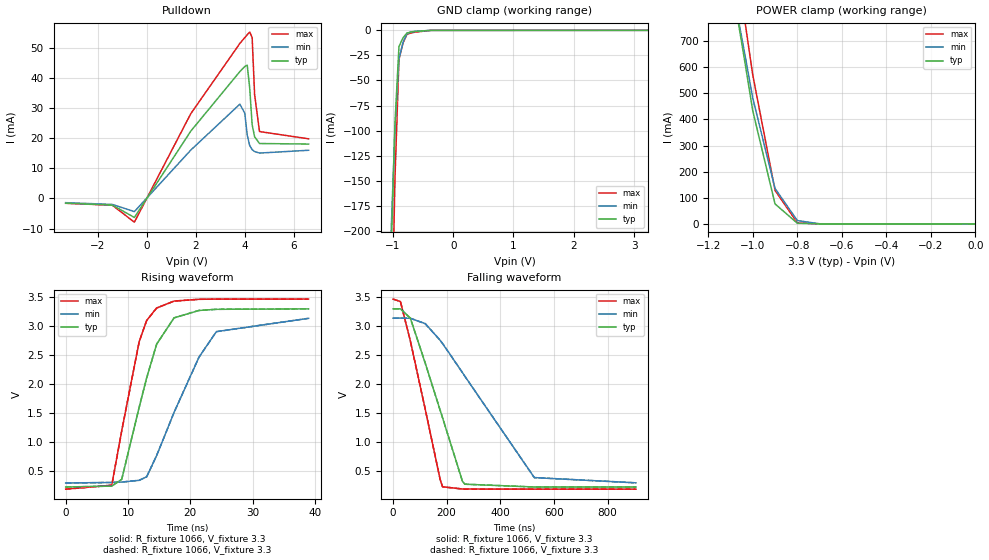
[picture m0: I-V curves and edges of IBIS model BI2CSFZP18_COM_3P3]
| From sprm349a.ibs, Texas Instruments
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|   Model Cell BI2CSFZP18_COM_3P3
[Model]   BI2CSFZP18_COM_3P3
Model_type   I/O_open_drain
Polarity   Non-Inverting
Enable   Active-Low
Vinl =  0.99
Vinh =  2.31
Cref =  400pF
Rref =  1.066k
Vref =  1.8V
Vmeas =  1.65
C_comp   1.488594p   1.343646p   1.625598p
[Model Spec]
Vinl   0.99   0.942   1.041
Vinh   2.31   2.198   2.429
[Temperature Range]   25   105   0
[Voltage Range]   3.3   3.14   3.47
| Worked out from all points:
|   slope of the pulldown table from 0 to 0.495 V, typ, clamps not added: 76.9 ohm
|   GND clamp passes 1 mA (typ) near -0.62 V on its own axis
|   POWER clamp passes 1 mA (typ) near -0.73 V on its own axis
|   rising waveform, R_fixture 1066, V_fixture 3.3: 20-80 % time 4.47ns typ, 6.96ns min, 3.58ns max; typ from 0.221 V to 3.3 V
|   rising waveform, R_fixture 1066, V_fixture 3.3: 20-80 % time 4.47ns typ, 6.96ns min, 3.58ns max; typ from 0.221 V to 3.3 V
|   falling waveform, R_fixture 1066, V_fixture 3.3: 20-80 % time 126ns typ, 248ns min, 92.5ns max; typ from 3.3 V to 0.221 V
|   falling waveform, R_fixture 1066, V_fixture 3.3: 20-80 % time 126ns typ, 248ns min, 92.5ns max; typ from 3.3 V to 0.221 V
[POWER_clamp]
|   voltage   I(typ)   I(min)   I(max)
-3.3V     15.05A     13.75A     15.99A
-1.067V   781.2mA    793mA      954.4mA
-1.033V   606.9mA    637.3mA    762.2mA
-1V       432.7mA    481.5mA    570mA
-900mV    76.75mA    135.8mA    128.5mA
-800mV    2.774mA    12.97mA    4.49mA
-700mV    66.53uA    739.3uA    77.17uA
-11.55fV  40.21nA    28.69nA    188.6nA
[Pulldown]
|   voltage   I(typ)   I(min)   I(max)
-3.3V     -1.585mA   -1.413mA   -1.619mA
-1.4V     -2.214mA   -1.997mA   -2.244mA
-500mV    -6.316mA   -4.377mA   -7.884mA
1.8V      22.32mA    16.03mA    28.1mA
3.8V      42.06mA    31.25mA    51.39mA
4V        43.73mA    28.23mA    53.32mA
4.1V      44.15mA    20.94mA    54.26mA
4.2V      36.62mA    17.54mA    55.14mA
4.3V      24.45mA    16.18mA    53.34mA
4.4V      20.43mA    15.54mA    34.42mA
4.6V      18.2mA     15.03mA    22.16mA
6.6V      18.02mA    15.96mA    19.76mA
[GND_clamp]
|   voltage   I(typ)   I(min)   I(max)
-3.3V     -17.3A     -15.81A    -18.24A
-1.033V   -228.3mA   -206mA     -345.7mA
-966.7mV  -93.1mA    -99.19mA   -148.6mA
-900mV    -16.17mA   -28.6mA    -29.03mA
-833.3mV  -7.484mA   -12.28mA   -12.72mA
-766.7mV  -2.666mA   -3.264mA   -3.923mA
-700mV    -1.72mA    -1.56mA    -2.645mA
-633.3mV  -1.119mA   -1.016mA   -1.818mA
-366.7mV  -16.93uA   -31.45uA   -52.75uA
3.233V    39.65nA    29.26nA    179.4nA
[Ramp]
| variable   typ   min   max
dV/dt_f   1.855402/0.1268571u   1.714812/0.249363u   1.982765/92.97102n
dV/dt_r  21.68196m/1.223917n   14.55153m/2.251652n   24.65348m/0.9062145n
R_load = 1.066k
[Rising Waveform]
R_fixture = 1066
V_fixture = 3.3
V_fixture_min = 3.14
V_fixture_max = 3.47
|   time   V(typ)   V(min)   V(max)
0s        220.8mV    289.7mV    183.5mV
7.4ns     236.5mV    299.5mV    251.6mV
9ns       354.2mV    306mV      1.193V
11.8ns    1.598V     336.9mV    2.733V
13ns      2.105V     396.7mV    3.099V
14.6ns    2.689V     763.2mV    3.315V
17.4ns    3.145V     1.51V      3.435V
21.4ns    3.273V     2.465V     3.466V
24.2ns    3.293V     2.907V     3.469V
39ns      3.3V       3.137V     3.47V
[Rising Waveform]
R_fixture = 1066
V_fixture = 3.3
V_fixture_min = 3.14
V_fixture_max = 3.47
|   time   V(typ)   V(min)   V(max)
0s        220.8mV    289.7mV    183.5mV
7.4ns     236.5mV    299.5mV    251.6mV
9ns       354.2mV    306mV      1.193V
11.8ns    1.598V     336.9mV    2.733V
13ns      2.105V     396.7mV    3.099V
14.6ns    2.689V     763.2mV    3.315V
17.4ns    3.145V     1.51V      3.435V
21.4ns    3.273V     2.465V     3.466V
24.2ns    3.293V     2.907V     3.469V
39ns      3.3V       3.137V     3.47V
[Falling Waveform]
R_fixture = 1066
V_fixture = 3.3
V_fixture_min = 3.14
V_fixture_max = 3.47
|   time   V(typ)   V(min)   V(max)
0s        3.3V       3.14V      3.47V
27.6ns    3.302V     3.141V     3.427V
64.4ns    3.141V     3.138V     2.75V
120ns     2.363V     3.045V     1.566V
175.4ns   1.551V     2.759V     356mV
184.6ns   1.419V     2.702V     224.4mV
258.6ns   321.1mV    2.2V       186.3mV
267.8ns   269.4mV    2.135V     185.8mV
526.6ns   221mV      383.5mV    183.5mV
905.4ns   220.8mV    292.9mV    183.5mV
[Falling Waveform]
R_fixture = 1066
V_fixture = 3.3
V_fixture_min = 3.14
V_fixture_max = 3.47
|   time   V(typ)   V(min)   V(max)
0s        3.3V       3.14V      3.47V
27.6ns    3.302V     3.141V     3.427V
64.4ns    3.141V     3.138V     2.75V
120ns     2.363V     3.045V     1.566V
175.4ns   1.551V     2.759V     356mV
184.6ns   1.419V     2.702V     224.4mV
258.6ns   321.1mV    2.2V       186.3mV
267.8ns   269.4mV    2.135V     185.8mV
526.6ns   221mV      383.5mV    183.5mV
905.4ns   220.8mV    292.9mV    183.5mV
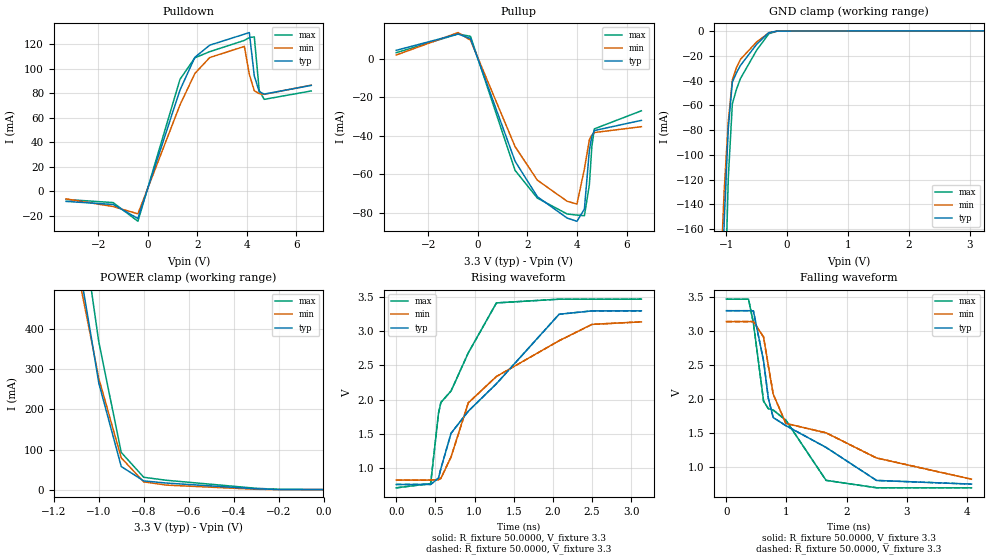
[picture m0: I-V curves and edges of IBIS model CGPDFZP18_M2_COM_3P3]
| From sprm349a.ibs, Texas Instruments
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|BUFFER OPERATING IN NORMAL MODE AT IND TEMP
|IND AND COM ARE TWO TEMP MODES WITH DIFF TEMP RANGE
|PI IS PULLDOWN PIN.
|   Model Cell CGPDFZP18_M2_COM_3P3
[Model]   CGPDFZP18_M2_COM_3P3
Model_type   I/O
Polarity   Non-Inverting
Enable   Active-Low
Vinl =  0.8
Vinh =  2.0
Cref =  10.0000pF
Rref =  50.0000
Vref =  1.5V
Vmeas =  1.5
C_comp   2.231182p   2.070767p   2.288404p
[Temperature Range]   25   105   0
[Voltage Range]   3.3   3.14   3.47
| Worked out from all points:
|   slope of the pulldown table from 0 to 0.495 V, typ, clamps not added: 14.8 ohm
|   slope of the pullup table from 0 to 0.495 V, typ, clamps not added: 25.3 ohm
|   GND clamp passes 1 mA (typ) near -0.27 V on its own axis
|   POWER clamp passes 1 mA (typ) near -0.24 V on its own axis
|   rising waveform, R_fixture 50.0000, V_fixture 3.3: 20-80 % time 1.07ns typ, 1.09ns min, 526ps max; typ from 0.758 V to 3.3 V
|   rising waveform, R_fixture 50.0000, V_fixture 3.3: 20-80 % time 1.07ns typ, 1.09ns min, 526ps max; typ from 0.758 V to 3.3 V
|   falling waveform, R_fixture 50.0000, V_fixture 3.3: 20-80 % time 1.11ns typ, 1.51ns min, 844ps max; typ from 3.3 V to 0.755 V
|   falling waveform, R_fixture 50.0000, V_fixture 3.3: 20-80 % time 1.11ns typ, 1.51ns min, 844ps max; typ from 3.3 V to 0.755 V
[POWER_clamp]
|   voltage   I(typ)   I(min)   I(max)
-3.3V     9.989A     8.641A     10.98A
-1.1V     604.8mA    564.8mA    758mA
-1.067V   491.9mA    469.1mA    628.3mA
-1.033V   379.1mA    373.5mA    498.7mA
-1V       266.2mA    277.8mA    369mA
-900mV    57.71mA    79.31mA    92.84mA
-800mV    21.76mA    19.36mA    30.85mA
-700mV    16.48mA    11.32mA    23.4mA
-300mV    2.029mA    849.9uA    3.357mA
-200mV    392.4uA    158.3uA    756.2uA
-11.55fV  102.4uA    62.72uA    147.1uA
[Pulldown]
|   voltage   I(typ)   I(min)   I(max)
-3.3V     -8.456mA   -6.412mA   -6.88mA
-1.4V     -10.96mA   -12.65mA   -9.431mA
-400mV    -22.4mA    -18.63mA   -24.71mA
1.3V      82.47mA    70.34mA    91.2mA
1.9V      109.2mA    95.96mA    108.8mA
2.5V      119.1mA    109mA      113.8mA
3.9V      128.1mA    118.1mA    123mA
4.1V      129.4mA    95.25mA    125.3mA
4.3V      94.04mA    81.92mA    125.9mA
4.5V      81.16mA    79.48mA    82.05mA
4.7V      79.16mA    78.96mA    74.86mA
6.6V      86.26mA    86.47mA    81.73mA
[Pullup]
|   voltage   I(typ)   I(min)   I(max)
-3.3V     4.286mA    1.847mA    3.065mA
-800mV    12.73mA    13.5mA     12.77mA
-300mV    10.41mA    9.538mA    11.56mA
1.5V      -53.19mA   -45.63mA   -57.95mA
2.4V      -71.6mA    -63.02mA   -72.32mA
3.6V      -82.66mA   -73.94mA   -80.54mA
4V        -84.35mA   -75.4mA    -81.13mA
4.3V      -77.99mA   -57.15mA   -81.46mA
4.5V      -47.49mA   -42.07mA   -65.43mA
4.6V      -40.38mA   -39.67mA   -45.58mA
4.7V      -37.3mA    -38.33mA   -36.43mA
6.6V      -32.02mA   -35.3mA    -27.05mA
[GND_clamp]
|   voltage   I(typ)   I(min)   I(max)
-3.3V     -13.5A     -11.63A    -14.67A
-1.1V     -264.6mA   -203.9mA   -421mA
-1.033V   -153.2mA   -128.3mA   -240mA
-966.7mV  -78.84mA   -73.47mA   -119.3mA
-900mV    -41.39mA   -39.57mA   -58.92mA
-833.3mV  -33.86mA   -29.78mA   -47.28mA
-766.7mV  -27.82mA   -22.88mA   -38.44mA
-500mV    -10.72mA   -8.846mA   -15.5mA
-300mV    -1.324mA   -1.478mA   -2.222mA
-166.7mV  -97.17uA   -154.9uA   -180.7uA
-100mV    -31.73uA   -28.57uA   -80.76uA
3.233V    102.2uA    74.43uA    145.9uA
[Ramp]
| variable   typ   min   max
dV/dt_f   1.526672/1.114159n   1.396267/1.538971n   1.660851/0.8434568n
dV/dt_r   1.293742/1.220363n   1.17001/1.321445n   1.422753/0.6798938n
R_load = 50
[Rising Waveform]
R_fixture = 50.0000
V_fixture = 3.3
V_fixture_min = 3.14
V_fixture_max = 3.47
|   time   V(typ)   V(min)   V(max)
0s        758.4mV    823.3mV    709.3mV
440ps     759.6mV    823.7mV    772.1mV
540ps     852.1mV    829.5mV    1.799V
570ps     988.9mV    846.9mV    1.957V
700ps     1.507V     1.161V     2.125V
920ps     1.829V     1.951V     2.682V
1.28ns    2.232V     2.338V     3.413V
2.08ns    3.247V     2.86V      3.467V
2.5ns     3.296V     3.099V     3.467V
3.13ns    3.297V     3.136V     3.468V
[Rising Waveform]
R_fixture = 50.0000
V_fixture = 3.3
V_fixture_min = 3.14
V_fixture_max = 3.47
|   time   V(typ)   V(min)   V(max)
0s        758.4mV    823.3mV    709.3mV
440ps     759.6mV    823.7mV    772.1mV
540ps     852.1mV    829.5mV    1.799V
570ps     988.9mV    846.9mV    1.957V
700ps     1.507V     1.161V     2.125V
920ps     1.829V     1.951V     2.682V
1.28ns    2.232V     2.338V     3.413V
2.08ns    3.247V     2.86V      3.467V
2.5ns     3.296V     3.099V     3.467V
3.13ns    3.297V     3.136V     3.468V
[Falling Waveform]
R_fixture = 50.0000
V_fixture = 3.3
V_fixture_min = 3.14
V_fixture_max = 3.47
|   time   V(typ)   V(min)   V(max)
0s        3.298V     3.139V     3.468V
370ps     3.298V     3.139V     3.467V
450ps     3.296V     3.139V     3.121V
620ps     2.559V     2.911V     1.971V
700ps     2.009V     2.486V     1.861V
780ps     1.731V     2.076V     1.841V
990ps     1.613V     1.645V     1.693V
1.66ns    1.293V     1.507V     809.9mV
2.5ns     808.7mV    1.138V     701.2mV
4.08ns    754.7mV    827.1mV    699.9mV
[Falling Waveform]
R_fixture = 50.0000
V_fixture = 3.3
V_fixture_min = 3.14
V_fixture_max = 3.47
|   time   V(typ)   V(min)   V(max)
0s        3.298V     3.139V     3.468V
370ps     3.298V     3.139V     3.467V
450ps     3.296V     3.139V     3.121V
620ps     2.559V     2.911V     1.971V
700ps     2.009V     2.486V     1.861V
780ps     1.731V     2.076V     1.841V
990ps     1.613V     1.645V     1.693V
1.66ns    1.293V     1.507V     809.9mV
2.5ns     808.7mV    1.138V     701.2mV
4.08ns    754.7mV    827.1mV    699.9mV
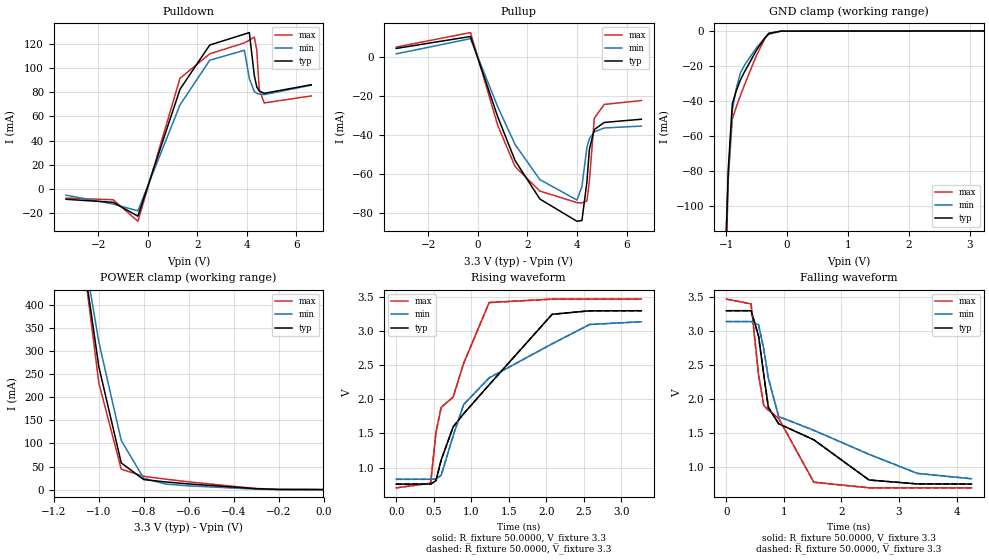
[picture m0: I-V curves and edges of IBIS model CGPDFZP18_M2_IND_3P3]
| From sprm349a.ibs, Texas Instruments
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|   Model Cell CGPDFZP18_M2_IND_3P3
[Model]   CGPDFZP18_M2_IND_3P3
Model_type   I/O
Polarity   Non-Inverting
Enable   Active-Low
Vinl =  0.8
Vinh =  2.0
Cref =  10.0000pF
Rref =  50.0000
Vref =  1.5V
Vmeas =  1.5
C_comp   2.231182p   2.070688p   2.311083p
[Temperature Range]   25   125   -40
[Voltage Range]   3.3   3.14   3.47
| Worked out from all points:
|   slope of the pulldown table from 0 to 0.495 V, typ, clamps not added: 14.8 ohm
|   slope of the pullup table from 0 to 0.495 V, typ, clamps not added: 25.3 ohm
|   GND clamp passes 1 mA (typ) near -0.27 V on its own axis
|   POWER clamp passes 1 mA (typ) near -0.24 V on its own axis
|   rising waveform, R_fixture 50.0000, V_fixture 3.3: 20-80 % time 1.06ns typ, 1.14ns min, 507ps max; typ from 0.759 V to 3.3 V
|   rising waveform, R_fixture 50.0000, V_fixture 3.3: 20-80 % time 1.06ns typ, 1.14ns min, 507ps max; typ from 0.759 V to 3.3 V
|   falling waveform, R_fixture 50.0000, V_fixture 3.3: 20-80 % time 1.11ns typ, 1.59ns min, 719ps max; typ from 3.3 V to 0.755 V
|   falling waveform, R_fixture 50.0000, V_fixture 3.3: 20-80 % time 1.11ns typ, 1.59ns min, 719ps max; typ from 3.3 V to 0.755 V
[POWER_clamp]
|   voltage   I(typ)   I(min)   I(max)
-3.3V     9.989A     8.515A     11.3A
-1.067V   491.9mA    510.8mA    488.4mA
-1.033V   379.1mA    415.3mA    359.7mA
-1V       266.2mA    319.7mA    231mA
-900mV    57.71mA    106.4mA    44.24mA
-800mV    21.75mA    24.35mA    28.73mA
-700mV    16.48mA    11.91mA    22.61mA
-600mV    12.37mA    8.231mA    16.78mA
-300mV    2.026mA    990.7uA    2.509mA
-200mV    389.8uA    196.9uA    460.9uA
-11.55fV  99.83uA    62.74uA    165uA
[Pulldown]
|   voltage   I(typ)   I(min)   I(max)
-3.3V     -8.447mA   -5.044mA   -7.456mA
-1.4V     -10.95mA   -12.3mA    -8.83mA
-400mV    -22.39mA   -18.01mA   -26.63mA
1.3V      82.43mA    69.53mA    91.5mA
2.5V      119mA      106.4mA    111.7mA
3.9V      128mA      114.7mA    120.8mA
4.1V      129.3mA    91.31mA    123mA
4.3V      93.96mA    80.57mA    125.6mA
4.4V      84.37mA    79.15mA    115mA
4.5V      81.1mA     78.45mA    82.37mA
4.7V      79.1mA     78.02mA    71.14mA
6.6V      86.2mA     85.83mA    76.96mA
[Pullup]
|   voltage   I(typ)   I(min)   I(max)
-3.3V     4.286mA    1.496mA    4.988mA
-300mV    10.41mA    9.296mA    12.42mA
800mV     -30.78mA   -25.65mA   -35.19mA
1.5V      -53.19mA   -44.94mA   -56.28mA
2.5V      -72.91mA   -62.97mA   -68.85mA
4V        -84.34mA   -73.44mA   -74.76mA
4.2V      -83.95mA   -66.45mA   -74.95mA
4.4V      -64.26mA   -46.53mA   -73.94mA
4.5V      -47.49mA   -42.04mA   -63.86mA
4.7V      -37.3mA    -38.48mA   -31.51mA
5.1V      -33.66mA   -36.49mA   -24.42mA
6.6V      -32.01mA   -35.52mA   -22.44mA
[GND_clamp]
|   voltage   I(typ)   I(min)   I(max)
-3.3V     -13.5A     -11.41A    -15.22A
-1.033V   -153.2mA   -142mA     -175.6mA
-966.7mV  -78.84mA   -82.94mA   -84.21mA
-900mV    -41.39mA   -45.29mA   -49.98mA
-833.3mV  -33.86mA   -32.48mA   -43.1mA
-766.7mV  -27.82mA   -23.87mA   -36.67mA
-700mV    -23.25mA   -19.45mA   -30.66mA
-500mV    -10.72mA   -9.351mA   -13.63mA
-366.7mV  -3.934mA   -3.986mA   -4.53mA
-300mV    -1.324mA   -1.811mA   -1.163mA
-100mV    -31.61uA   -39.44uA   -46.87uA
3.233V    99.59uA    80.68uA    164.5uA
[Ramp]
| variable   typ   min   max
dV/dt_f   1.526544/1.113073n   1.393242/1.618247n   1.66137/0.7197431n
dV/dt_r   1.293759/1.219096n   1.164049/1.393901n   1.410053/0.6646706n
R_load = 50
[Rising Waveform]
R_fixture = 50.0000
V_fixture = 3.3
V_fixture_min = 3.14
V_fixture_max = 3.47
|   time   V(typ)   V(min)   V(max)
0s        758.6mV    829.2mV    704.1mV
460ps     760.2mV    830mV      772.5mV
530ps     808.8mV    834mV      1.519V
600ps     1.112V     888.9mV    1.883V
760ps     1.597V     1.468V     2.034V
900ps     1.79V      1.925V     2.528V
1.24ns    2.213V     2.314V     3.417V
2.08ns    3.245V     2.813V     3.467V
2.58ns    3.296V     3.096V     3.467V
3.27ns    3.297V     3.136V     3.467V
[Rising Waveform]
R_fixture = 50.0000
V_fixture = 3.3
V_fixture_min = 3.14
V_fixture_max = 3.47
|   time   V(typ)   V(min)   V(max)
0s        758.6mV    829.2mV    704.1mV
460ps     760.2mV    830mV      772.5mV
530ps     808.8mV    834mV      1.519V
600ps     1.112V     888.9mV    1.883V
760ps     1.597V     1.468V     2.034V
900ps     1.79V      1.925V     2.528V
1.24ns    2.213V     2.314V     3.417V
2.08ns    3.245V     2.813V     3.467V
2.58ns    3.296V     3.096V     3.467V
3.27ns    3.297V     3.136V     3.467V
[Falling Waveform]
R_fixture = 50.0000
V_fixture = 3.3
V_fixture_min = 3.14
V_fixture_max = 3.47
|   time   V(typ)   V(min)   V(max)
0s        3.298V     3.139V     3.468V
430ps     3.298V     3.139V     3.398V
560ps     2.926V     3.092V     2.358V
650ps     2.361V     2.739V     1.909V
730ps     1.881V     2.306V     1.841V
910ps     1.639V     1.745V     1.718V
1.52ns    1.404V     1.543V     781.3mV
2.48ns    813.9mV    1.191V     699.3mV
3.32ns    756.7mV    911mV      698.9mV
4.26ns    754.8mV    832.7mV    698.8mV
[Falling Waveform]
R_fixture = 50.0000
V_fixture = 3.3
V_fixture_min = 3.14
V_fixture_max = 3.47
|   time   V(typ)   V(min)   V(max)
0s        3.298V     3.139V     3.468V
430ps     3.298V     3.139V     3.398V
560ps     2.926V     3.092V     2.358V
650ps     2.361V     2.739V     1.909V
730ps     1.881V     2.306V     1.841V
910ps     1.639V     1.745V     1.718V
1.52ns    1.404V     1.543V     781.3mV
2.48ns    813.9mV    1.191V     699.3mV
3.32ns    756.7mV    911mV      698.9mV
4.26ns    754.8mV    832.7mV    698.8mV
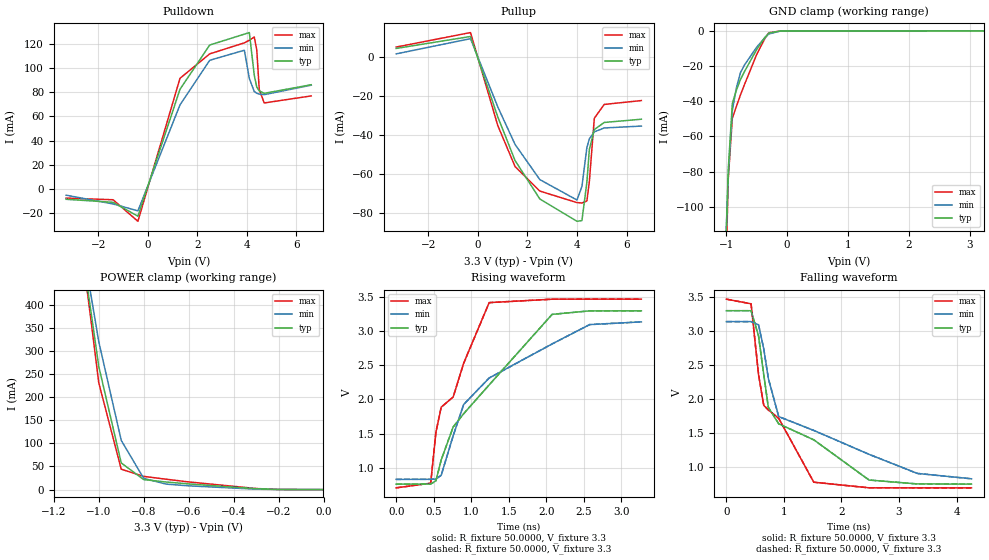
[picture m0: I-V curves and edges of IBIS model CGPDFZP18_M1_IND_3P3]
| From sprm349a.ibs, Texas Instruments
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|   Model Cell CGPDFZP18_M1_IND_3P3
[Model]   CGPDFZP18_M1_IND_3P3
Model_type   I/O
Polarity   Non-Inverting
Enable   Active-Low
Vinl =  0.8
Vinh =  2.0
Cref =  10.0000pF
Rref =  50.0000
Vref =  1.5V
Vmeas =  1.5
C_comp   2.231182p   2.070688p   2.311083p
[Temperature Range]   25   125   -40
[Voltage Range]   3.3   3.14   3.47
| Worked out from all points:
|   slope of the pulldown table from 0 to 0.495 V, typ, clamps not added: 14.8 ohm
|   slope of the pullup table from 0 to 0.495 V, typ, clamps not added: 25.3 ohm
|   GND clamp passes 1 mA (typ) near -0.28 V on its own axis
|   POWER clamp passes 1 mA (typ) near -0.24 V on its own axis
|   rising waveform, R_fixture 50.0000, V_fixture 3.3: 20-80 % time 1.06ns typ, 1.14ns min, 507ps max; typ from 0.76 V to 3.3 V
|   rising waveform, R_fixture 50.0000, V_fixture 3.3: 20-80 % time 1.06ns typ, 1.14ns min, 507ps max; typ from 0.76 V to 3.3 V
|   falling waveform, R_fixture 50.0000, V_fixture 3.3: 20-80 % time 1.11ns typ, 1.59ns min, 719ps max; typ from 3.3 V to 0.756 V
|   falling waveform, R_fixture 50.0000, V_fixture 3.3: 20-80 % time 1.11ns typ, 1.59ns min, 719ps max; typ from 3.3 V to 0.756 V
[POWER_clamp]
|   voltage   I(typ)   I(min)   I(max)
-3.3V     9.989A     8.515A     11.3A
-1.067V   491.9mA    510.8mA    488.3mA
-1.033V   379mA      415.2mA    359.6mA
-1V       266.2mA    319.7mA    230.9mA
-900mV    57.62mA    106.4mA    44.09mA
-800mV    21.66mA    24.29mA    28.58mA
-700mV    16.38mA    11.85mA    22.45mA
-600mV    12.27mA    8.172mA    16.62mA
-300mV    1.929mA    931.9uA    2.35mA
-200mV    292.8uA    138.1uA    301.8uA
-11.55fV  2.899uA    3.969uA    5.984uA
[Pulldown]
|   voltage   I(typ)   I(min)   I(max)
-3.3V     -8.447mA   -5.044mA   -7.456mA
-1.4V     -10.95mA   -12.3mA    -8.83mA
-400mV    -22.4mA    -18.01mA   -26.63mA
1.3V      82.43mA    69.53mA    91.5mA
2.5V      119mA      106.4mA    111.7mA
3.9V      128mA      114.7mA    120.8mA
4.1V      129.3mA    91.31mA    123mA
4.3V      93.96mA    80.57mA    125.6mA
4.4V      84.37mA    79.15mA    115mA
4.5V      81.1mA     78.45mA    82.37mA
4.7V      79.1mA     78.02mA    71.14mA
6.6V      86.2mA     85.83mA    76.96mA
[Pullup]
|   voltage   I(typ)   I(min)   I(max)
-3.3V     4.286mA    1.496mA    4.988mA
-300mV    10.41mA    9.296mA    12.42mA
800mV     -30.78mA   -25.65mA   -35.19mA
1.5V      -53.19mA   -44.94mA   -56.28mA
2.5V      -72.91mA   -62.97mA   -68.85mA
4V        -84.34mA   -73.43mA   -74.76mA
4.2V      -83.95mA   -66.45mA   -74.95mA
4.4V      -64.26mA   -46.53mA   -73.94mA
4.5V      -47.49mA   -42.04mA   -63.85mA
4.7V      -37.3mA    -38.48mA   -31.51mA
5.1V      -33.66mA   -36.49mA   -24.42mA
6.6V      -32.01mA   -35.52mA   -22.44mA
[GND_clamp]
|   voltage   I(typ)   I(min)   I(max)
-3.3V     -13.5A     -11.41A    -15.22A
-1.033V   -153.2mA   -141.9mA   -175.4mA
-966.7mV  -78.76mA   -82.92mA   -84.05mA
-900mV    -41.29mA   -45.27mA   -49.79mA
-833.3mV  -33.75mA   -32.45mA   -42.92mA
-766.7mV  -27.7mA    -23.83mA   -36.48mA
-700mV    -23.13mA   -19.4mA    -30.49mA
-500mV    -10.62mA   -9.294mA   -13.49mA
-366.7mV  -3.864mA   -3.942mA   -4.427mA
-300mV    -1.267mA   -1.775mA   -1.079mA
-100mV    -13.31uA   -28.11uA   -19.56uA
3.233V    2.696uA    21.88uA    5.645uA
[Ramp]
| variable   typ   min   max
dV/dt_f   1.526863/1.113107n   1.39345/1.618004n   1.66186/0.7200728n
dV/dt_r   1.294858/1.218775n   1.164769/1.393565n   1.411889/0.6642447n
R_load = 50
[Rising Waveform]
R_fixture = 50.0000
V_fixture = 3.3
V_fixture_min = 3.14
V_fixture_max = 3.47
|   time   V(typ)   V(min)   V(max)
0s        759.7mV    830mV      705.6mV
460ps     761.3mV    830.7mV    774mV
530ps     809.9mV    834.8mV    1.522V
600ps     1.114V     889.7mV    1.887V
760ps     1.598V     1.469V     2.037V
900ps     1.792V     1.927V     2.532V
1.24ns    2.214V     2.315V     3.419V
2.08ns    3.247V     2.814V     3.469V
2.58ns    3.298V     3.097V     3.47V
3.27ns    3.299V     3.137V     3.47V
[Rising Waveform]
R_fixture = 50.0000
V_fixture = 3.3
V_fixture_min = 3.14
V_fixture_max = 3.47
|   time   V(typ)   V(min)   V(max)
0s        759.7mV    830mV      705.6mV
460ps     761.3mV    830.7mV    774mV
530ps     809.9mV    834.8mV    1.522V
600ps     1.114V     889.7mV    1.887V
760ps     1.598V     1.469V     2.037V
900ps     1.792V     1.927V     2.532V
1.24ns    2.214V     2.315V     3.419V
2.08ns    3.247V     2.814V     3.469V
2.58ns    3.298V     3.097V     3.47V
3.27ns    3.299V     3.137V     3.47V
[Falling Waveform]
R_fixture = 50.0000
V_fixture = 3.3
V_fixture_min = 3.14
V_fixture_max = 3.47
|   time   V(typ)   V(min)   V(max)
0s        3.3V       3.14V      3.47V
430ps     3.3V       3.14V      3.401V
560ps     2.928V     3.093V     2.36V
650ps     2.363V     2.74V      1.911V
730ps     1.883V     2.307V     1.844V
910ps     1.64V      1.746V     1.721V
1.52ns    1.405V     1.543V     783.1mV
2.48ns    815mV      1.192V     700.8mV
3.32ns    757.7mV    911.8mV    700.3mV
4.26ns    755.8mV    833.5mV    700.2mV
[Falling Waveform]
R_fixture = 50.0000
V_fixture = 3.3
V_fixture_min = 3.14
V_fixture_max = 3.47
|   time   V(typ)   V(min)   V(max)
0s        3.3V       3.14V      3.47V
430ps     3.3V       3.14V      3.401V
560ps     2.928V     3.093V     2.36V
650ps     2.363V     2.74V      1.911V
730ps     1.883V     2.307V     1.844V
910ps     1.64V      1.746V     1.721V
1.52ns    1.405V     1.543V     783.1mV
2.48ns    815mV      1.192V     700.8mV
3.32ns    757.7mV    911.8mV    700.3mV
4.26ns    755.8mV    833.5mV    700.2mV
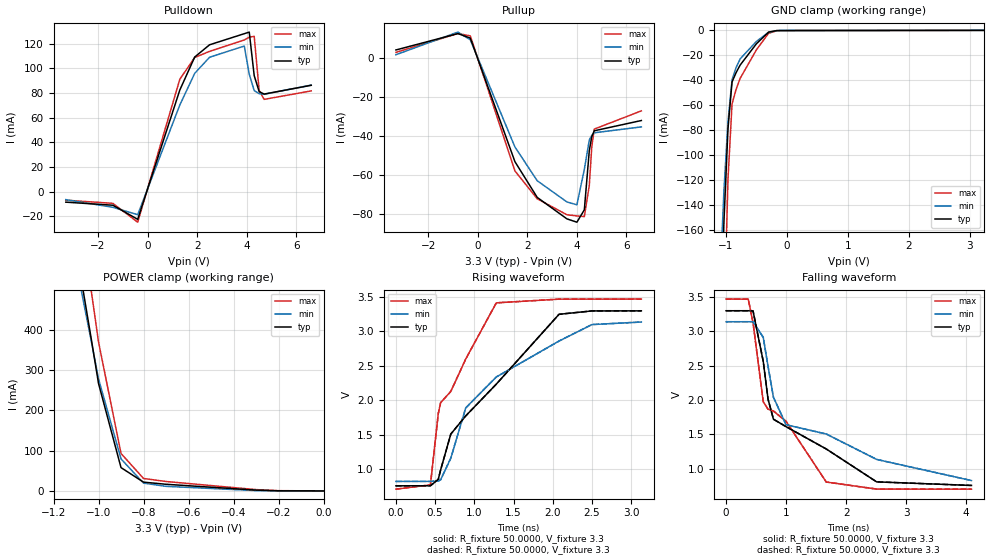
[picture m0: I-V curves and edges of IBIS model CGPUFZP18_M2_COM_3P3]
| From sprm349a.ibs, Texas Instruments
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|BUFFER OPERATING IN NORMAL MODE AT IND TEMP
|IND AND COM ARE TWO TEMP MODES WITH  DIFF TEMP RANGE
|PI IS PULLUP PIN.
|   Model Cell CGPUFZP18_M2_COM_3P3
[Model]   CGPUFZP18_M2_COM_3P3
Model_type   I/O
Polarity   Non-Inverting
Enable   Active-Low
Vinl =  0.8
Vinh =  2.0
Cref =  10.0000pF
Rref =  50.0000
Vref =  1.5V
Vmeas =  1.5
C_comp   2.224866p   2.063663p   2.283104p
[Temperature Range]   25   105   0
[Voltage Range]   3.3   3.14   3.47
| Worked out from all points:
|   slope of the pulldown table from 0 to 0.495 V, typ, clamps not added: 14.8 ohm
|   slope of the pullup table from 0 to 0.495 V, typ, clamps not added: 25.3 ohm
|   GND clamp passes 1 mA (typ) near -0.27 V on its own axis
|   POWER clamp passes 1 mA (typ) near -0.24 V on its own axis
|   rising waveform, R_fixture 50.0000, V_fixture 3.3: 20-80 % time 1.07ns typ, 1.09ns min, 526ps max; typ from 0.761 V to 3.3 V
|   rising waveform, R_fixture 50.0000, V_fixture 3.3: 20-80 % time 1.07ns typ, 1.09ns min, 526ps max; typ from 0.761 V to 3.3 V
|   falling waveform, R_fixture 50.0000, V_fixture 3.3: 20-80 % time 1.11ns typ, 1.52ns min, 844ps max; typ from 3.3 V to 0.757 V
|   falling waveform, R_fixture 50.0000, V_fixture 3.3: 20-80 % time 1.11ns typ, 1.52ns min, 844ps max; typ from 3.3 V to 0.757 V
[POWER_clamp]
|   voltage   I(typ)   I(min)   I(max)
-3.3V     9.989A     8.641A     10.98A
-1.1V     604.8mA    564.9mA    758mA
-1.067V   492mA      469.2mA    628.4mA
-1.033V   379.1mA    373.5mA    498.7mA
-1V       266.3mA    277.8mA    369.1mA
-900mV    57.75mA    79.33mA    92.87mA
-800mV    21.77mA    19.37mA    30.86mA
-700mV    16.49mA    11.32mA    23.39mA
-300mV    1.972mA    816.1uA    3.271mA
-200mV    320.7uA    115.3uA    651.6uA
-11.55fV  2.899uA    2.516uA    6.988uA
[Pulldown]
|   voltage   I(typ)   I(min)   I(max)
-3.3V     -8.456mA   -6.412mA   -6.88mA
-1.4V     -10.96mA   -12.65mA   -9.431mA
-400mV    -22.4mA    -18.63mA   -24.71mA
1.3V      82.47mA    70.34mA    91.21mA
1.9V      109.2mA    95.96mA    108.8mA
2.5V      119.1mA    109mA      113.8mA
3.9V      128.1mA    118.1mA    123mA
4.1V      129.4mA    95.25mA    125.3mA
4.3V      94.04mA    81.92mA    125.9mA
4.5V      81.16mA    79.48mA    82.05mA
4.7V      79.15mA    78.96mA    74.86mA
6.6V      86.26mA    86.47mA    81.72mA
[Pullup]
|   voltage   I(typ)   I(min)   I(max)
-3.3V     4.286mA    1.848mA    3.065mA
-800mV    12.73mA    13.5mA     12.77mA
-300mV    10.41mA    9.538mA    11.56mA
1.5V      -53.19mA   -45.63mA   -57.95mA
2.4V      -71.6mA    -63.02mA   -72.32mA
3.6V      -82.66mA   -73.95mA   -80.54mA
4V        -84.35mA   -75.4mA    -81.13mA
4.3V      -78mA      -57.15mA   -81.46mA
4.5V      -47.49mA   -42.07mA   -65.43mA
4.6V      -40.38mA   -39.67mA   -45.57mA
4.7V      -37.3mA    -38.33mA   -36.43mA
6.6V      -32.02mA   -35.3mA    -27.05mA
[GND_clamp]
|   voltage   I(typ)   I(min)   I(max)
-3.3V     -13.5A     -11.63A    -14.67A
-1.1V     -264.6mA   -203.8mA   -420.9mA
-1.033V   -153.2mA   -128.2mA   -240mA
-966.7mV  -78.78mA   -73.4mA    -119.3mA
-900mV    -41.35mA   -39.51mA   -58.88mA
-833.3mV  -33.83mA   -29.74mA   -47.26mA
-766.7mV  -27.8mA    -22.85mA   -38.43mA
-500mV    -10.75mA   -8.851mA   -15.57mA
-300mV    -1.401mA   -1.51mA    -2.335mA
-166.7mV  -200.5uA   -204.3uA   -327.5uA
-100mV    -147.8uA   -86.41uA   -243.9uA
3.233V    -6.103uA   22.14uA    -32.71uA
[Ramp]
| variable   typ   min   max
dV/dt_f   1.526002/1.114528n   1.395878/1.539021n   1.660072/0.8438863n
dV/dt_r   1.295241/1.21899n   1.170964/1.320117n   1.424794/0.6791072n
R_load = 50
[Rising Waveform]
R_fixture = 50.0000
V_fixture = 3.3
V_fixture_min = 3.14
V_fixture_max = 3.47
|   time   V(typ)   V(min)   V(max)
0s        761.1mV    825.1mV    712.7mV
440ps     762.3mV    825.5mV    775.2mV
540ps     854.8mV    831.3mV    1.808V
570ps     991.7mV    848.8mV    1.967V
700ps     1.512V     1.163V     2.131V
890ps     1.775V     1.891V     2.6V
1.28ns    2.236V     2.34V      3.415V
2.08ns    3.249V     2.861V     3.469V
2.5ns     3.298V     3.1V       3.469V
3.13ns    3.299V     3.137V     3.47V
[Rising Waveform]
R_fixture = 50.0000
V_fixture = 3.3
V_fixture_min = 3.14
V_fixture_max = 3.47
|   time   V(typ)   V(min)   V(max)
0s        761.1mV    825.1mV    712.7mV
440ps     762.3mV    825.5mV    775.2mV
540ps     854.8mV    831.3mV    1.808V
570ps     991.7mV    848.8mV    1.967V
700ps     1.512V     1.163V     2.131V
890ps     1.775V     1.891V     2.6V
1.28ns    2.236V     2.34V      3.415V
2.08ns    3.249V     2.861V     3.469V
2.5ns     3.298V     3.1V       3.469V
3.13ns    3.299V     3.137V     3.47V
[Falling Waveform]
R_fixture = 50.0000
V_fixture = 3.3
V_fixture_min = 3.14
V_fixture_max = 3.47
|   time   V(typ)   V(min)   V(max)
0s        3.3V       3.14V      3.47V
370ps     3.3V       3.14V      3.469V
450ps     3.297V     3.14V      3.125V
620ps     2.562V     2.913V     1.976V
700ps     2.013V     2.489V     1.867V
790ps     1.721V     2.04V      1.84V
1ns       1.613V     1.641V     1.691V
1.67ns    1.288V     1.506V     807.2mV
2.51ns    809.3mV    1.136V     704.5mV
4.09ns    757.5mV    828.4mV    703.2mV
[Falling Waveform]
R_fixture = 50.0000
V_fixture = 3.3
V_fixture_min = 3.14
V_fixture_max = 3.47
|   time   V(typ)   V(min)   V(max)
0s        3.3V       3.14V      3.47V
370ps     3.3V       3.14V      3.469V
450ps     3.297V     3.14V      3.125V
620ps     2.562V     2.913V     1.976V
700ps     2.013V     2.489V     1.867V
790ps     1.721V     2.04V      1.84V
1ns       1.613V     1.641V     1.691V
1.67ns    1.288V     1.506V     807.2mV
2.51ns    809.3mV    1.136V     704.5mV
4.09ns    757.5mV    828.4mV    703.2mV
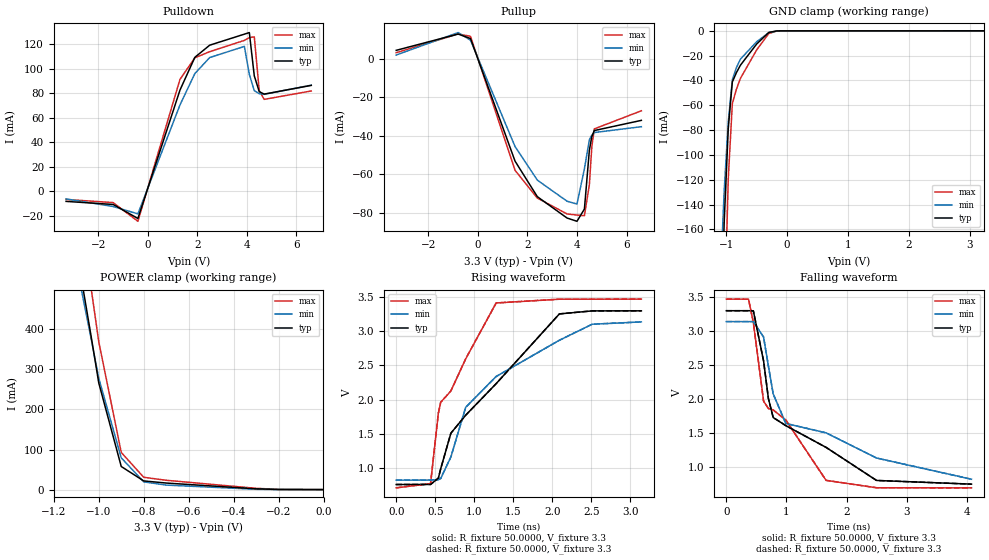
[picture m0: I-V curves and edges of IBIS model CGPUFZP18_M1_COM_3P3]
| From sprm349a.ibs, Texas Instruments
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|   Model Cell CGPUFZP18_M1_COM_3P3
[Model]   CGPUFZP18_M1_COM_3P3
Model_type   I/O
Polarity   Non-Inverting
Enable   Active-Low
Vinl =  0.8
Vinh =  2.0
Cref =  10.0000pF
Rref =  50.0000
Vref =  1.5V
Vmeas =  1.5
C_comp   2.224866p   2.063663p   2.283104p
[Temperature Range]   25   105   0
[Voltage Range]   3.3   3.14   3.47
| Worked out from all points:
|   slope of the pulldown table from 0 to 0.495 V, typ, clamps not added: 14.8 ohm
|   slope of the pullup table from 0 to 0.495 V, typ, clamps not added: 25.3 ohm
|   GND clamp passes 1 mA (typ) near -0.28 V on its own axis
|   POWER clamp passes 1 mA (typ) near -0.24 V on its own axis
|   rising waveform, R_fixture 50.0000, V_fixture 3.3: 20-80 % time 1.07ns typ, 1.09ns min, 527ps max; typ from 0.759 V to 3.3 V
|   rising waveform, R_fixture 50.0000, V_fixture 3.3: 20-80 % time 1.07ns typ, 1.09ns min, 527ps max; typ from 0.759 V to 3.3 V
|   falling waveform, R_fixture 50.0000, V_fixture 3.3: 20-80 % time 1.11ns typ, 1.51ns min, 844ps max; typ from 3.3 V to 0.756 V
|   falling waveform, R_fixture 50.0000, V_fixture 3.3: 20-80 % time 1.11ns typ, 1.51ns min, 844ps max; typ from 3.3 V to 0.756 V
[POWER_clamp]
|   voltage   I(typ)   I(min)   I(max)
-3.3V     9.989A     8.641A     10.98A
-1.1V     604.8mA    564.9mA    758mA
-1.067V   491.9mA    469.2mA    628.3mA
-1.033V   379.1mA    373.5mA    498.6mA
-1V       266.2mA    277.8mA    369mA
-900mV    57.67mA    79.31mA    92.76mA
-800mV    21.68mA    19.33mA    30.74mA
-700mV    16.4mA     11.27mA    23.28mA
-300mV    1.93mA     789.8uA    3.217mA
-200mV    292.9uA    98.03uA    616.1uA
-11.55fV  2.899uA    2.516uA    6.989uA
[Pulldown]
|   voltage   I(typ)   I(min)   I(max)
-3.3V     -8.456mA   -6.412mA   -6.88mA
-1.4V     -10.96mA   -12.65mA   -9.431mA
-400mV    -22.4mA    -18.63mA   -24.71mA
1.3V      82.47mA    70.34mA    91.21mA
1.9V      109.2mA    95.96mA    108.8mA
2.5V      119.1mA    109mA      113.8mA
3.9V      128.1mA    118.1mA    123mA
4.1V      129.4mA    95.25mA    125.3mA
4.3V      94.03mA    81.92mA    125.9mA
4.5V      81.16mA    79.48mA    82.05mA
4.7V      79.15mA    78.96mA    74.85mA
6.6V      86.26mA    86.47mA    81.72mA
[Pullup]
|   voltage   I(typ)   I(min)   I(max)
-3.3V     4.286mA    1.848mA    3.065mA
-800mV    12.73mA    13.5mA     12.77mA
-300mV    10.41mA    9.538mA    11.56mA
1.5V      -53.19mA   -45.63mA   -57.95mA
2.4V      -71.6mA    -63.02mA   -72.32mA
3.6V      -82.66mA   -73.95mA   -80.54mA
4V        -84.35mA   -75.4mA    -81.13mA
4.3V      -77.99mA   -57.15mA   -81.46mA
4.5V      -47.49mA   -42.07mA   -65.42mA
4.6V      -40.38mA   -39.67mA   -45.57mA
4.7V      -37.3mA    -38.33mA   -36.43mA
6.6V      -32.02mA   -35.3mA    -27.05mA
[GND_clamp]
|   voltage   I(typ)   I(min)   I(max)
-3.3V     -13.5A     -11.63A    -14.67A
-1.1V     -264.5mA   -203.8mA   -420.8mA
-1.033V   -153.1mA   -128.1mA   -239.8mA
-966.7mV  -78.66mA   -73.34mA   -119.1mA
-900mV    -41.22mA   -39.45mA   -58.71mA
-833.3mV  -33.7mA    -29.68mA   -47.08mA
-766.7mV  -27.67mA   -22.78mA   -38.25mA
-500mV    -10.62mA   -8.781mA   -15.38mA
-300mV    -1.267mA   -1.44mA    -2.148mA
-166.7mV  -65.66uA   -134.5uA   -139.9uA
-100mV    -13.04uA   -16.59uA   -56.37uA
3.233V    2.696uA    14.19uA    5.949uA
[Ramp]
| variable   typ   min   max
dV/dt_f   1.527007/1.114153n   1.396481/1.538757n   1.661306/0.8434225n
dV/dt_r   1.29488/1.21961n   1.170741/1.320598n   1.424305/0.6798213n
R_load = 50
[Rising Waveform]
R_fixture = 50.0000
V_fixture = 3.3
V_fixture_min = 3.14
V_fixture_max = 3.47
|   time   V(typ)   V(min)   V(max)
0s        759.5mV    824.1mV    710.6mV
440ps     760.6mV    824.5mV    772.9mV
540ps     852.9mV    830.3mV    1.804V
570ps     989.8mV    847.7mV    1.962V
700ps     1.509V     1.162V     2.127V
890ps     1.773V     1.889V     2.597V
1.28ns    2.234V     2.339V     3.414V
2.09ns    3.254V     2.869V     3.469V
2.51ns    3.298V     3.103V     3.469V
3.14ns    3.299V     3.137V     3.47V
[Rising Waveform]
R_fixture = 50.0000
V_fixture = 3.3
V_fixture_min = 3.14
V_fixture_max = 3.47
|   time   V(typ)   V(min)   V(max)
0s        759.5mV    824.1mV    710.6mV
440ps     760.6mV    824.5mV    772.9mV
540ps     852.9mV    830.3mV    1.804V
570ps     989.8mV    847.7mV    1.962V
700ps     1.509V     1.162V     2.127V
890ps     1.773V     1.889V     2.597V
1.28ns    2.234V     2.339V     3.414V
2.09ns    3.254V     2.869V     3.469V
2.51ns    3.298V     3.103V     3.469V
3.14ns    3.299V     3.137V     3.47V
[Falling Waveform]
R_fixture = 50.0000
V_fixture = 3.3
V_fixture_min = 3.14
V_fixture_max = 3.47
|   time   V(typ)   V(min)   V(max)
0s        3.3V       3.14V      3.47V
370ps     3.3V       3.14V      3.469V
450ps     3.297V     3.14V      3.125V
620ps     2.562V     2.913V     1.974V
700ps     2.012V     2.489V     1.865V
780ps     1.733V     2.079V     1.844V
990ps     1.614V     1.646V     1.696V
1.66ns    1.295V     1.508V     811.3mV
2.5ns     809.8mV    1.139V     702.5mV
4.08ns    755.8mV    827.8mV    701.2mV
[Falling Waveform]
R_fixture = 50.0000
V_fixture = 3.3
V_fixture_min = 3.14
V_fixture_max = 3.47
|   time   V(typ)   V(min)   V(max)
0s        3.3V       3.14V      3.47V
370ps     3.3V       3.14V      3.469V
450ps     3.297V     3.14V      3.125V
620ps     2.562V     2.913V     1.974V
700ps     2.012V     2.489V     1.865V
780ps     1.733V     2.079V     1.844V
990ps     1.614V     1.646V     1.696V
1.66ns    1.295V     1.508V     811.3mV
2.5ns     809.8mV    1.139V     702.5mV
4.08ns    755.8mV    827.8mV    701.2mV
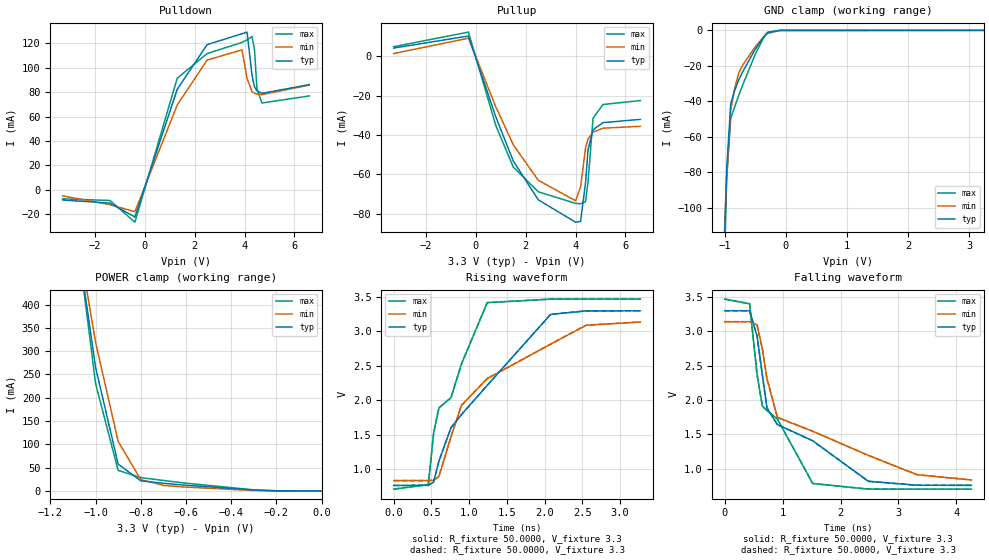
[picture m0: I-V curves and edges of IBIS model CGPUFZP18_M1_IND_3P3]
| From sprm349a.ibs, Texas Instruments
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|   Model Cell CGPUFZP18_M1_IND_3P3
[Model]   CGPUFZP18_M1_IND_3P3
Model_type   I/O
Polarity   Non-Inverting
Enable   Active-Low
Vinl =  0.8
Vinh =  2.0
Cref =  10.0000pF
Rref =  50.0000
Vref =  1.5V
Vmeas =  1.5
C_comp   2.224866p   2.063469p   2.306731p
[Temperature Range]   25   125   -40
[Voltage Range]   3.3   3.14   3.47
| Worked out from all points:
|   slope of the pulldown table from 0 to 0.495 V, typ, clamps not added: 14.8 ohm
|   slope of the pullup table from 0 to 0.495 V, typ, clamps not added: 25.3 ohm
|   GND clamp passes 1 mA (typ) near -0.28 V on its own axis
|   POWER clamp passes 1 mA (typ) near -0.24 V on its own axis
|   rising waveform, R_fixture 50.0000, V_fixture 3.3: 20-80 % time 1.06ns typ, 1.14ns min, 508ps max; typ from 0.76 V to 3.3 V
|   rising waveform, R_fixture 50.0000, V_fixture 3.3: 20-80 % time 1.06ns typ, 1.14ns min, 508ps max; typ from 0.76 V to 3.3 V
|   falling waveform, R_fixture 50.0000, V_fixture 3.3: 20-80 % time 1.11ns typ, 1.59ns min, 719ps max; typ from 3.3 V to 0.756 V
|   falling waveform, R_fixture 50.0000, V_fixture 3.3: 20-80 % time 1.11ns typ, 1.59ns min, 719ps max; typ from 3.3 V to 0.756 V
[POWER_clamp]
|   voltage   I(typ)   I(min)   I(max)
-3.3V     9.989A     8.515A     11.31A
-1.067V   491.9mA    510.8mA    488.3mA
-1.033V   379.1mA    415.3mA    359.6mA
-1V       266.2mA    319.8mA    231mA
-900mV    57.67mA    106.4mA    44.12mA
-800mV    21.68mA    24.33mA    28.6mA
-700mV    16.4mA     11.87mA    22.47mA
-600mV    12.28mA    8.18mA     16.63mA
-300mV    1.93mA     932.1uA    2.351mA
-200mV    292.9uA    138.2uA    301.8uA
-11.55fV  2.9uA      3.97uA     5.984uA
[Pulldown]
|   voltage   I(typ)   I(min)   I(max)
-3.3V     -8.447mA   -5.043mA   -7.456mA
-1.4V     -10.95mA   -12.3mA    -8.83mA
-400mV    -22.4mA    -18.01mA   -26.63mA
1.3V      82.43mA    69.53mA    91.5mA
2.5V      119mA      106.4mA    111.7mA
3.9V      128mA      114.7mA    120.8mA
4.1V      129.3mA    91.31mA    123mA
4.3V      93.96mA    80.57mA    125.6mA
4.4V      84.37mA    79.15mA    115mA
4.5V      81.1mA     78.45mA    82.36mA
4.7V      79.09mA    78.02mA    71.14mA
6.6V      86.19mA    85.82mA    76.95mA
[Pullup]
|   voltage   I(typ)   I(min)   I(max)
-3.3V     4.286mA    1.496mA    4.989mA
-300mV    10.41mA    9.296mA    12.42mA
800mV     -30.78mA   -25.65mA   -35.19mA
1.5V      -53.19mA   -44.94mA   -56.28mA
2.5V      -72.91mA   -62.97mA   -68.85mA
4V        -84.34mA   -73.44mA   -74.76mA
4.2V      -83.95mA   -66.45mA   -74.95mA
4.4V      -64.26mA   -46.53mA   -73.94mA
4.5V      -47.49mA   -42.04mA   -63.86mA
4.7V      -37.3mA    -38.48mA   -31.51mA
5.1V      -33.66mA   -36.49mA   -24.42mA
6.6V      -32.01mA   -35.52mA   -22.44mA
[GND_clamp]
|   voltage   I(typ)   I(min)   I(max)
-3.3V     -13.5A     -11.41A    -15.22A
-1.033V   -153.1mA   -141.8mA   -175.3mA
-966.7mV  -78.66mA   -82.81mA   -83.96mA
-900mV    -41.22mA   -45.17mA   -49.73mA
-833.3mV  -33.7mA    -32.38mA   -42.87mA
-766.7mV  -27.67mA   -23.78mA   -36.45mA
-700mV    -23.11mA   -19.37mA   -30.46mA
-500mV    -10.62mA   -9.29mA    -13.49mA
-366.7mV  -3.863mA   -3.941mA   -4.426mA
-300mV    -1.267mA   -1.775mA   -1.078mA
-100mV    -13.04uA   -28.1uA    -18.91uA
3.233V    2.696uA    21.88uA    5.645uA
[Ramp]
| variable   typ   min   max
dV/dt_f   1.526866/1.113051n   1.393453/1.61805n   1.661864/0.7198011n
dV/dt_r   1.294868/1.218347n   1.164769/1.393058n   1.411905/0.6645727n
R_load = 50
[Rising Waveform]
R_fixture = 50.0000
V_fixture = 3.3
V_fixture_min = 3.14
V_fixture_max = 3.47
|   time   V(typ)   V(min)   V(max)
0s        759.7mV    830mV      705.6mV
460ps     761.3mV    830.7mV    773.4mV
530ps     809.7mV    834.8mV    1.524V
600ps     1.114V     889.7mV    1.888V
760ps     1.599V     1.469V     2.037V
900ps     1.792V     1.926V     2.53V
1.24ns    2.214V     2.314V     3.418V
2.08ns    3.247V     2.814V     3.469V
2.55ns    3.298V     3.089V     3.47V
3.27ns    3.299V     3.137V     3.47V
[Rising Waveform]
R_fixture = 50.0000
V_fixture = 3.3
V_fixture_min = 3.14
V_fixture_max = 3.47
|   time   V(typ)   V(min)   V(max)
0s        759.7mV    830mV      705.6mV
460ps     761.3mV    830.7mV    773.4mV
530ps     809.7mV    834.8mV    1.524V
600ps     1.114V     889.7mV    1.888V
760ps     1.599V     1.469V     2.037V
900ps     1.792V     1.926V     2.53V
1.24ns    2.214V     2.314V     3.418V
2.08ns    3.247V     2.814V     3.469V
2.55ns    3.298V     3.089V     3.47V
3.27ns    3.299V     3.137V     3.47V
[Falling Waveform]
R_fixture = 50.0000
V_fixture = 3.3
V_fixture_min = 3.14
V_fixture_max = 3.47
|   time   V(typ)   V(min)   V(max)
0s        3.3V       3.14V      3.47V
430ps     3.3V       3.14V      3.401V
560ps     2.929V     3.093V     2.363V
650ps     2.364V     2.742V     1.912V
730ps     1.884V     2.309V     1.844V
910ps     1.641V     1.746V     1.722V
1.52ns    1.405V     1.544V     783mV
2.48ns    814.9mV    1.192V     700.8mV
3.32ns    757.7mV    911.8mV    700.3mV
4.26ns    755.8mV    833.5mV    700.2mV
[Falling Waveform]
R_fixture = 50.0000
V_fixture = 3.3
V_fixture_min = 3.14
V_fixture_max = 3.47
|   time   V(typ)   V(min)   V(max)
0s        3.3V       3.14V      3.47V
430ps     3.3V       3.14V      3.401V
560ps     2.929V     3.093V     2.363V
650ps     2.364V     2.742V     1.912V
730ps     1.884V     2.309V     1.844V
910ps     1.641V     1.746V     1.722V
1.52ns    1.405V     1.544V     783mV
2.48ns    814.9mV    1.192V     700.8mV
3.32ns    757.7mV    911.8mV    700.3mV
4.26ns    755.8mV    833.5mV    700.2mV
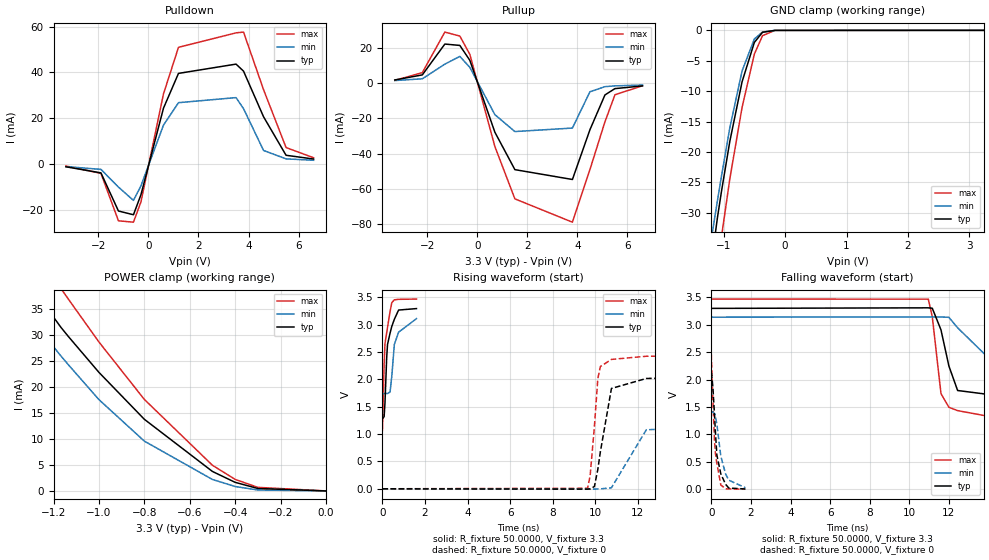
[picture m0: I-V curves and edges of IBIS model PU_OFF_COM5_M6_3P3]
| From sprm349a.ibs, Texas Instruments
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|PU_ON_IND5_M3_3P3BUFFER OPERATING AT 100UA IN SLOWEST MODE WITH INDTEMP AT
| PLUS OR MINUS 5PERCENT VDDS WITH PULLDOWN ON
|COM AND IND ARE TWO DIFFERENT TEMP MODES
|COM IS 25,0,105(NOM,STRONG,WEAK)
|IND IS 25,-40,125(NOM,STRONG,WEAK)
|   Model Cell PU_OFF_COM5_M6_3P3
|PU_OFF_COM5_M6_3P3
[Model]   PU_OFF_COM5_M6_3P3
Model_type   I/O
Polarity   Non-Inverting
Enable   Active-Low
Vinl =  0.8V
Vinh =  2V
Cref =  15.0000pF
Rref =  100.0000M
Vref =  0V
Vmeas =  1.65
C_comp   2.519588p   2.445246p   2.584934p
[Model Spec]
Vinl   0.8V   0.8V   0.8V
Vinh   2V   2V   2V
[Temperature Range]   25   105   0
[Voltage Range]   3.3   3.14   3.47
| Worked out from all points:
|   slope of the pulldown table from 0 to 0.495 V, typ, clamps not added: 24.1 ohm
|   slope of the pullup table from 0 to 0.495 V, typ, clamps not added: 24.3 ohm
|   GND clamp passes 1 mA (typ) near -0.44 V on its own axis
|   POWER clamp passes 1 mA (typ) near -0.34 V on its own axis
|   rising waveform, R_fixture 50.0000, V_fixture 3.3: 20-80 % time 257ps typ, 302ps min, 226ps max; typ from 1.28 V to 3.29 V
|   rising waveform, R_fixture 50.0000, V_fixture 0: 20-80 % time 495ps typ, 2.36ns min, 289ps max; typ from 0 V to 2.12 V
|   falling waveform, R_fixture 50.0000, V_fixture 3.3: 20-80 % time 3.47ns typ, 15.5ns min, 602ps max; typ from 3.3 V to 1.28 V
|   falling waveform, R_fixture 50.0000, V_fixture 0: 20-80 % time 272ps typ, 399ps min, 231ps max; typ from 2.13 V to 0.005 V
[POWER_clamp]
|   voltage   I(typ)   I(min)   I(max)
-3.3V     190.9mA    146.8mA    233.2mA
-1.4V     46.49mA    38.72mA    55.95mA
-1.367V   44.17mA    36.85mA    53.27mA
-1.267V   37.42mA    31.31mA    45.61mA
-1.167V   31.42mA    25.92mA    38.88mA
-1.133V   29.6mA     24.17mA    36.77mA
-1V       22.79mA    17.55mA    28.63mA
-800mV    13.77mA    9.575mA    17.59mA
-500mV    3.742mA    2.2mA      4.932mA
-400mV    1.65mA     851uA      2.218mA
-300mV    469.7uA    179.7uA    684.1uA
0V        124.7nA    166.8nA    588.5nA
[Pulldown]
|   voltage   I(typ)   I(min)   I(max)
-3.3V     -1.263mA   -1.167mA   -922.1uA
-1.9V     -3.924mA   -2.399mA   -4.147mA
-1.2V     -20.61mA   -10.14mA   -24.89mA
-600mV    -22.25mA   -15.98mA   -25.5mA
-300mV    -13.47mA   -9.578mA   -16.6mA
600mV     24.37mA    16.97mA    30.6mA
1.2V      39.59mA    26.78mA    51mA
3.5V      43.65mA    29mA       57.32mA
3.8V      40.58mA    24.17mA    57.66mA
4.6V      20.62mA    5.881mA    32.48mA
5.5V      3.772mA    2.2mA      7.146mA
6.6V      2.132mA    1.586mA    2.693mA
[Pullup]
|   voltage   I(typ)   I(min)   I(max)
-3.3V     1.672mA    1.34mA     1.437mA
-2.2V     4.543mA    2.334mA    5.823mA
-1.3V     21.99mA    10.63mA    28.76mA
-700mV    21.21mA    15.01mA    26.51mA
-300mV    12.75mA    8.771mA    16.13mA
700mV     -27.88mA   -17.95mA   -35.98mA
1.5V      -49.06mA   -27.52mA   -65.59mA
3.8V      -54.63mA   -25.53mA   -78.79mA
4.5V      -26.49mA   -5.02mA    -49.01mA
5.1V      -6.796mA   -2.11mA    -22mA
5.5V      -3.223mA   -1.669mA   -6.707mA
6.6V      -1.699mA   -1.186mA   -1.605mA
[GND_clamp]
|   voltage   I(typ)   I(min)   I(max)
-3.3V     -223.6mA   -173.6mA   -271.7mA
-1.3V     -46.73mA   -40.89mA   -56mA
-1.233V   -41.16mA   -36.54mA   -49.77mA
-1.167V   -35.84mA   -32.24mA   -44mA
-1.1V     -30.78mA   -27.99mA   -38.7mA
-1.033V   -26.39mA   -23.89mA   -33.85mA
-900mV    -18.31mA   -16.08mA   -24.5mA
-700mV    -8.481mA   -6.7mA     -12.7mA
-500mV    -1.993mA   -1.431mA   -3.916mA
-366.7mV  -323.4uA   -261.5uA   -875.2uA
-166.7mV  -8.585uA   -8.498uA   -17.12uA
3.233V    68.5nA     2.549uA    371.7nA
[Ramp]
| variable   typ   min   max
dV/dt_f   1.21957/3.417756n   0.8412576/17.38326n   1.449408/0.5796782n
dV/dt_r   1.281429/0.4915n   0.8431001/1.377618n   1.485004/0.2887618n
R_load = 50
[Rising Waveform]
R_fixture = 50.0000
V_fixture = 3.3
V_fixture_min = 3.14
V_fixture_max = 3.47
|   time   V(typ)   V(min)   V(max)
0s        1.28V      1.739V     1.068V
80ps      1.319V     1.742V     2.271V
120ps     1.568V     1.742V     2.652V
200ps     2.397V     1.742V     2.853V
240ps     2.638V     1.741V     2.951V
360ps     2.847V     1.771V     3.241V
440ps     2.968V     2.057V     3.402V
560ps     3.098V     2.639V     3.454V
760ps     3.267V     2.863V     3.463V
1.6ns     3.294V     3.11V      3.468V
[Rising Waveform]
R_fixture = 50.0000
V_fixture = 0
V_fixture_min = 0
V_fixture_max = 0
|   time   V(typ)   V(min)   V(max)
0s        53.38uV    40.43uV    72.38uV
9.64ns    -6.813mV   66.54uV    9.391mV
9.76ns    -2.941mV   -1.679mV   240.1mV
9.96ns    42.46mV    -6.49mV    1.14V
10.12ns   352.6mV    -2.994mV   2.012V
10.24ns   676.9mV    -1.661mV   2.235V
10.76ns   1.834V     18.59mV    2.365V
12.4ns    2.017V     1.079V     2.423V
31.92ns   2.096V     1.363V     2.454V
246.8ns   2.125V     1.384V     2.466V
[Falling Waveform]
R_fixture = 50.0000
V_fixture = 3.3
V_fixture_min = 3.14
V_fixture_max = 3.47
|   time   V(typ)   V(min)   V(max)
0s        3.3V       3.14V      3.47V
10.96ns   3.31V      3.144V     3.468V
11.16ns   3.303V     3.144V     3.149V
11.6ns    2.908V     3.143V     1.745V
12ns      2.248V     3.137V     1.496V
12.44ns   1.802V     2.946V     1.435V
14.64ns   1.7V       2.171V     1.288V
23.12ns   1.527V     2.078V     1.142V
84.12ns   1.313V     1.863V     1.071V
294.4ns   1.281V     1.764V     1.068V
[Falling Waveform]
R_fixture = 50.0000
V_fixture = 0
V_fixture_min = 0
V_fixture_max = 0
|   time   V(typ)   V(min)   V(max)
0s        2.127V     1.409V     2.466V
40ps      2.012V     1.414V     1.981V
80ps      1.855V     1.41V      1.635V
160ps     1.371V     1.379V     897.2mV
200ps     1.084V     1.342V     677.3mV
280ps     623.9mV    1.188V     474.8mV
480ps     281.3mV    602.5mV    77.91mV
720ps     91.42mV    280.9mV    9.441mV
880ps     22.75mV    165.7mV    6.122mV
1.72ns    5.012mV    28.47mV    1.944mV
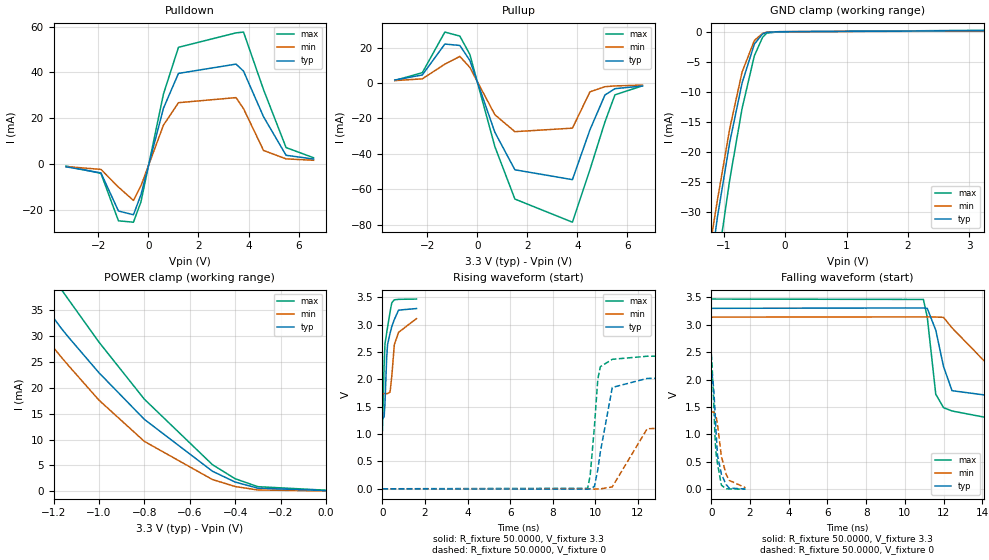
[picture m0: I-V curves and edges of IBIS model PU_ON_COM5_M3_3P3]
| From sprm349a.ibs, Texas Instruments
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|   Model Cell PU_ON_COM5_M3_3P3
|PU_ON_COM5_M3_3P3
[Model]   PU_ON_COM5_M3_3P3
Model_type   I/O
Polarity   Non-Inverting
Enable   Active-Low
Vinl =  0.8V
Vinh =  2V
Cref =  15.0000pF
Rref =  100.0000M
Vref =  0V
Vmeas =  1.65
C_comp   2.519588p   2.445246p   2.584934p
[Model Spec]
Vinl   0.8V   0.8V   0.8V
Vinh   2V   2V   2V
[Temperature Range]   25   105   0
[Voltage Range]   3.3   3.14   3.47
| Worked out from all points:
|   slope of the pulldown table from 0 to 0.495 V, typ, clamps not added: 24.1 ohm
|   slope of the pullup table from 0 to 0.495 V, typ, clamps not added: 24.3 ohm
|   GND clamp passes 1 mA (typ) near -0.43 V on its own axis
|   POWER clamp passes 1 mA (typ) near -0.33 V on its own axis
|   rising waveform, R_fixture 50.0000, V_fixture 3.3: 20-80 % time 258ps typ, 303ps min, 228ps max; typ from 1.27 V to 3.29 V
|   rising waveform, R_fixture 50.0000, V_fixture 0: 20-80 % time 497ps typ, 1.63ns min, 290ps max; typ from 0 V to 2.12 V
|   falling waveform, R_fixture 50.0000, V_fixture 3.3: 20-80 % time 3.42ns typ, 15.5ns min, 594ps max; typ from 3.3 V to 1.28 V
|   falling waveform, R_fixture 50.0000, V_fixture 0: 20-80 % time 270ps typ, 398ps min, 229ps max; typ from 2.12 V to 0.005 V
[POWER_clamp]
|   voltage   I(typ)   I(min)   I(max)
-3.3V     191.2mA    146.9mA    233.5mA
-1.4V     46.64mA    38.8mA     56.18mA
-1.367V   44.31mA    36.93mA    53.5mA
-1.267V   37.57mA    31.39mA    45.84mA
-1.167V   31.57mA    26mA       39.1mA
-1.133V   29.74mA    24.25mA    37mA
-1V       22.93mA    17.63mA    28.85mA
-800mV    13.91mA    9.651mA    17.81mA
-500mV    3.879mA    2.275mA    5.145mA
-400mV    1.787mA    926.4uA    2.43mA
-300mV    605.5uA    254.9uA    895.5uA
0V        134.8uA    74.72uA    210uA
[Pulldown]
|   voltage   I(typ)   I(min)   I(max)
-3.3V     -1.263mA   -1.167mA   -922.1uA
-1.9V     -3.924mA   -2.399mA   -4.147mA
-1.2V     -20.61mA   -10.14mA   -24.9mA
-600mV    -22.25mA   -15.98mA   -25.5mA
-300mV    -13.47mA   -9.578mA   -16.6mA
600mV     24.37mA    16.97mA    30.6mA
1.2V      39.59mA    26.78mA    51mA
3.5V      43.65mA    29mA       57.32mA
3.8V      40.58mA    24.17mA    57.66mA
4.6V      20.62mA    5.881mA    32.48mA
5.5V      3.772mA    2.2mA      7.146mA
6.6V      2.132mA    1.586mA    2.693mA
[Pullup]
|   voltage   I(typ)   I(min)   I(max)
-3.3V     1.672mA    1.34mA     1.437mA
-2.2V     4.543mA    2.334mA    5.824mA
-1.3V     21.99mA    10.63mA    28.76mA
-700mV    21.21mA    15.01mA    26.51mA
-300mV    12.75mA    8.771mA    16.13mA
700mV     -27.88mA   -17.95mA   -35.98mA
1.5V      -49.06mA   -27.52mA   -65.6mA
3.8V      -54.63mA   -25.53mA   -78.68mA
4.5V      -26.49mA   -5.02mA    -49.01mA
5.1V      -6.796mA   -2.11mA    -22mA
5.5V      -3.223mA   -1.669mA   -6.707mA
6.6V      -1.699mA   -1.186mA   -1.605mA
[GND_clamp]
|   voltage   I(typ)   I(min)   I(max)
-3.3V     -223.6mA   -173.6mA   -271.7mA
-1.3V     -46.75mA   -40.9mA    -56.02mA
-1.233V   -41.19mA   -36.55mA   -49.81mA
-1.167V   -35.89mA   -32.26mA   -44.06mA
-1.1V     -30.85mA   -28.01mA   -38.79mA
-900mV    -18.42mA   -16.13mA   -24.64mA
-700mV    -8.593mA   -6.769mA   -12.84mA
-500mV    -2.09mA    -1.494mA   -4.038mA
-366.7mV  -404.4uA   -314.1uA   -977.1uA
-300mV    -126.1uA   -104.8uA   -272.1uA
-100mV    -30.7uA    -20.8uA    -40.82uA
3.233V    134.5uA    77.26uA    208.9uA
[Ramp]
| variable   typ   min   max
dV/dt_f   1.219953/3.379852n   0.8417753/17.38262n   1.448506/0.5730812n
dV/dt_r   1.279649/0.4932032n  0.8411185/1.38199n   1.482911/0.2897101n
R_load = 50
[Rising Waveform]
R_fixture = 50.0000
V_fixture = 3.3
V_fixture_min = 3.14
V_fixture_max = 3.47
|   time   V(typ)   V(min)   V(max)
0s        1.275V     1.736V     1.064V
80ps      1.314V     1.739V     2.262V
120ps     1.562V     1.739V     2.644V
200ps     2.391V     1.738V     2.847V
240ps     2.633V     1.738V     2.944V
360ps     2.842V     1.768V     3.233V
440ps     2.962V     2.053V     3.397V
560ps     3.092V     2.636V     3.451V
760ps     3.263V     2.859V     3.46V
1.6ns     3.292V     3.107V     3.465V
[Rising Waveform]
R_fixture = 50.0000
V_fixture = 0
V_fixture_min = 0
V_fixture_max = 0
|   time   V(typ)   V(min)   V(max)
0s        53.39uV    40.42uV    72.49uV
9.64ns    -6.764mV   66.46uV    9.427mV
9.76ns    -2.887mV   -1.678mV   239.3mV
9.96ns    42.43mV    -6.468mV   1.134V
10.12ns   351.5mV    -2.964mV   2.004V
10.24ns   674.1mV    -1.637mV   2.23V
10.8ns    1.851V     35.18mV    2.365V
12.44ns   2.016V     1.097V     2.421V
31.96ns   2.093V     1.36V      2.45V
246.8ns   2.122V     1.38V      2.462V
[Falling Waveform]
R_fixture = 50.0000
V_fixture = 3.3
V_fixture_min = 3.14
V_fixture_max = 3.47
|   time   V(typ)   V(min)   V(max)
0s        3.298V     3.138V     3.467V
10.96ns   3.305V     3.142V     3.46V
11.16ns   3.297V     3.142V     3.14V
11.6ns    2.901V     3.139V     1.733V
12ns      2.239V     3.134V     1.488V
12.44ns   1.797V     2.942V     1.427V
14.56ns   1.698V     2.175V     1.284V
23.08ns   1.522V     2.075V     1.137V
84.08ns   1.308V     1.86V      1.067V
294.4ns   1.276V     1.761V     1.064V
[Falling Waveform]
R_fixture = 50.0000
V_fixture = 0
V_fixture_min = 0
V_fixture_max = 0
|   time   V(typ)   V(min)   V(max)
0s        2.124V     1.405V     2.463V
40ps      2.087V     1.41V      2.257V
120ps     1.852V     1.407V     1.629V
200ps     1.366V     1.376V     887.4mV
240ps     1.077V     1.338V     670.6mV
320ps     618.8mV    1.184V     467.4mV
520ps     276.3mV    599.1mV    75.23mV
760ps     89mV       277.9mV    9.314mV
920ps     22.18mV    163.2mV    6.05mV
1.76ns    4.958mV    27.98mV    1.925mV
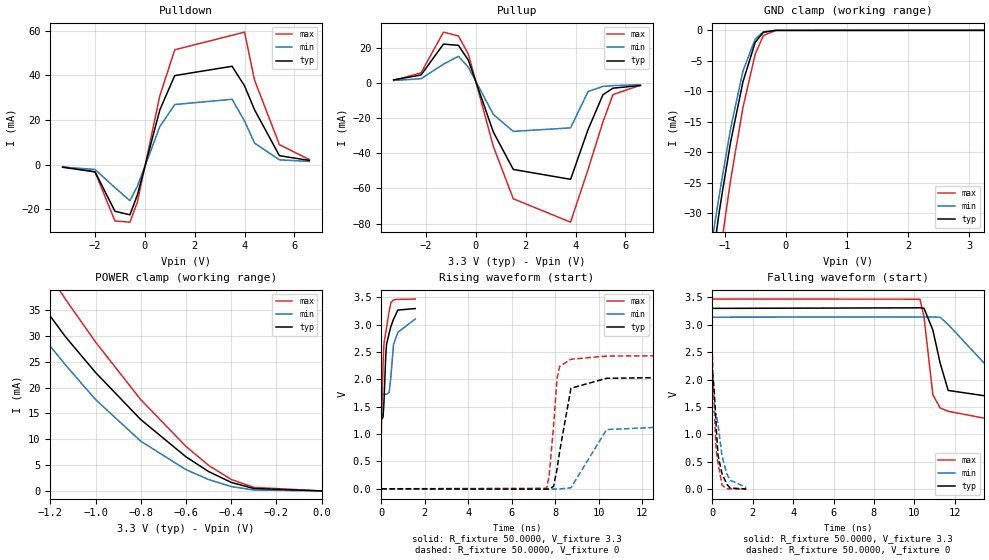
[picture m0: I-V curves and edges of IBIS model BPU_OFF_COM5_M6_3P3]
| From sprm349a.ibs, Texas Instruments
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|BPU_ON_IND5_M3_3P3BUFFER OPERATING AT 100UA IN SLOWEST MODE WITH INDTEMP AT
| PLUS OR MINUS 5PERCENT VDDS WITH PULLUP ON
|COM AND IND ARE TWO DIFFERENT TEMP MODES
|COM IS 25,0,105(NOM,STRONG,WEAK)
|IND IS 25,-40,125(NOM,STRONG,WEAK)
|   Model Cell BPU_OFF_COM5_M6_3P3
|BPU_OFF_COM5_M6_3P3
[Model]   BPU_OFF_COM5_M6_3P3
Model_type   I/O
Polarity   Non-Inverting
Enable   Active-Low
Vinl =  0.8V
Vinh =  2V
Cref =  15.0000pF
Rref =  100.0000M
Vref =  0V
Vmeas =  1.65
C_comp   2.525228p   2.451532p   2.589111p
[Model Spec]
Vinl   0.8V   0.8V   0.8V
Vinh   2V   2V   2V
[Temperature Range]   25   105   0
[Voltage Range]   3.3   3.14   3.47
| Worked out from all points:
|   slope of the pulldown table from 0 to 0.495 V, typ, clamps not added: 23.9 ohm
|   slope of the pullup table from 0 to 0.495 V, typ, clamps not added: 24.3 ohm
|   GND clamp passes 1 mA (typ) near -0.44 V on its own axis
|   POWER clamp passes 1 mA (typ) near -0.34 V on its own axis
|   rising waveform, R_fixture 50.0000, V_fixture 3.3: 20-80 % time 257ps typ, 298ps min, 227ps max; typ from 1.27 V to 3.29 V
|   rising waveform, R_fixture 50.0000, V_fixture 0: 20-80 % time 493ps typ, 2.11ns min, 289ps max; typ from 0 V to 2.12 V
|   falling waveform, R_fixture 50.0000, V_fixture 3.3: 20-80 % time 3.29ns typ, 15.3ns min, 567ps max; typ from 3.3 V to 1.27 V
|   falling waveform, R_fixture 50.0000, V_fixture 0: 20-80 % time 272ps typ, 396ps min, 231ps max; typ from 2.13 V to 0.005 V
[POWER_clamp]
|   voltage   I(typ)   I(min)   I(max)
-3.3V     193.2mA    148.3mA    236.6mA
-1.4V     47.03mA    39.12mA    56.71mA
-1.367V   44.66mA    37.23mA    53.98mA
-1.267V   37.82mA    31.62mA    46.15mA
-1.133V   29.86mA    24.41mA    37.13mA
-1V       22.94mA    17.7mA     28.84mA
-800mV    13.82mA    9.628mA    17.68mA
-600mV    6.603mA    4.127mA    8.619mA
-500mV    3.754mA    2.205mA    4.951mA
-400mV    1.654mA    852.6uA    2.224mA
-300mV    470.4uA    179.9uA    685.4uA
0V        124.8nA    164.6nA    589.3nA
[Pulldown]
|   voltage   I(typ)   I(min)   I(max)
-3.3V     -1.114mA   -1.069mA   -794.7uA
-2V       -3.148mA   -2.085mA   -3.182mA
-1.2V     -20.83mA   -10.24mA   -25.18mA
-600mV    -22.41mA   -16.07mA   -25.72mA
-300mV    -13.56mA   -9.625mA   -16.74mA
600mV     24.55mA    17.07mA    30.86mA
1.2V      39.96mA    26.99mA    51.51mA
3.5V      44.12mA    29.34mA    57.99mA
4V        35.35mA    19.62mA    59.44mA
4.4V      24.67mA    9.708mA    37.95mA
5.4V      4.076mA    2.22mA     9.002mA
6.6V      1.947mA    1.489mA    2.337mA
[Pullup]
|   voltage   I(typ)   I(min)   I(max)
-3.3V     1.643mA    1.325mA    1.402mA
-2.2V     4.461mA    2.313mA    5.651mA
-1.3V     21.98mA    10.59mA    28.8mA
-700mV    21.27mA    15.04mA    26.61mA
-300mV    12.78mA    8.788mA    16.19mA
700mV     -27.95mA   -17.98mA   -36.12mA
1.5V      -49.2mA    -27.58mA   -65.86mA
3.8V      -54.82mA   -25.6mA    -79.16mA
4.5V      -26.58mA   -4.984mA   -49.27mA
5.1V      -6.729mA   -2.034mA   -22.14mA
5.5V      -3.06mA    -1.59mA    -6.676mA
6.6V      -1.531mA   -1.11mA    -1.421mA
[GND_clamp]
|   voltage   I(typ)   I(min)   I(max)
-3.3V     -222.4mA   -172.9mA   -269.9mA
-1.3V     -46.48mA   -40.71mA   -55.68mA
-1.233V   -40.94mA   -36.38mA   -49.53mA
-1.167V   -35.67mA   -32.1mA    -43.83mA
-1.1V     -30.65mA   -27.86mA   -38.58mA
-1.033V   -26.29mA   -23.78mA   -33.77mA
-900mV    -18.25mA   -16.01mA   -24.45mA
-700mV    -8.44mA    -6.663mA   -12.66mA
-500mV    -1.97mA    -1.412mA   -3.89mA
-366.7mV  -314.2uA   -253.8uA   -862.5uA
-166.7mV  -8.153uA   -8.203uA   -16.19uA
3.233V    68.23nA    2.55uA     370.5nA
[Ramp]
| variable   typ   min   max
dV/dt_f   1.227954/3.243605n   0.8482777/17.43574n   1.455161/0.5558657n
dV/dt_r   1.282984/0.4903379n  0.8448822/1.379774n   1.486971/0.2885259n
R_load = 50
[Rising Waveform]
R_fixture = 50.0000
V_fixture = 3.3
V_fixture_min = 3.14
V_fixture_max = 3.47
|   time   V(typ)   V(min)   V(max)
0s        1.266V     1.727V     1.059V
80ps      1.31V      1.73V      2.269V
120ps     1.569V     1.73V      2.649V
200ps     2.4V       1.73V      2.85V
240ps     2.638V     1.729V     2.948V
360ps     2.845V     1.761V     3.24V
440ps     2.966V     2.052V     3.402V
560ps     3.097V     2.637V     3.454V
760ps     3.267V     2.86V      3.463V
1.56ns    3.294V     3.103V     3.468V
[Rising Waveform]
R_fixture = 50.0000
V_fixture = 0
V_fixture_min = 0
V_fixture_max = 0
|   time   V(typ)   V(min)   V(max)
0s        48.63uV    39.89uV    62.84uV
7.6ns     -6.806mV   36.29uV    9.551mV
7.72ns    -2.921mV   -1.72mV    242.3mV
7.92ns    43.74mV    -6.511mV   1.145V
8.08ns    356.7mV    -2.992mV   2.017V
8.2ns     681.4mV    -1.662mV   2.237V
8.72ns    1.838V     19.05mV    2.368V
10.36ns   2.02V      1.082V     2.426V
25.76ns   2.096V     1.359V     2.455V
195.4ns   2.125V     1.383V     2.469V
[Falling Waveform]
R_fixture = 50.0000
V_fixture = 3.3
V_fixture_min = 3.14
V_fixture_max = 3.47
|   time   V(typ)   V(min)   V(max)
0s        3.3V       3.14V      3.47V
10.28ns   3.31V      3.144V     3.468V
10.48ns   3.303V     3.144V     3.147V
10.92ns   2.905V     3.143V     1.725V
11.28ns   2.302V     3.138V     1.484V
11.68ns   1.803V     3.004V     1.423V
13.72ns   1.693V     2.199V     1.279V
21.52ns   1.52V      2.078V     1.137V
80ns      1.301V     1.859V     1.062V
277.9ns   1.267V     1.756V     1.059V
[Falling Waveform]
R_fixture = 50.0000
V_fixture = 0
V_fixture_min = 0
V_fixture_max = 0
|   time   V(typ)   V(min)   V(max)
0s        2.13V      1.412V     2.469V
40ps      2.014V     1.417V     1.983V
80ps      1.856V     1.413V     1.638V
160ps     1.371V     1.382V     898.2mV
200ps     1.082V     1.344V     677.7mV
280ps     622.5mV    1.188V     474.4mV
480ps     280.7mV    601.3mV    76.16mV
720ps     90.69mV    279.7mV    9.358mV
880ps     22.37mV    164.8mV    6.08mV
1.68ns    5.186mV    32.47mV    2.049mV
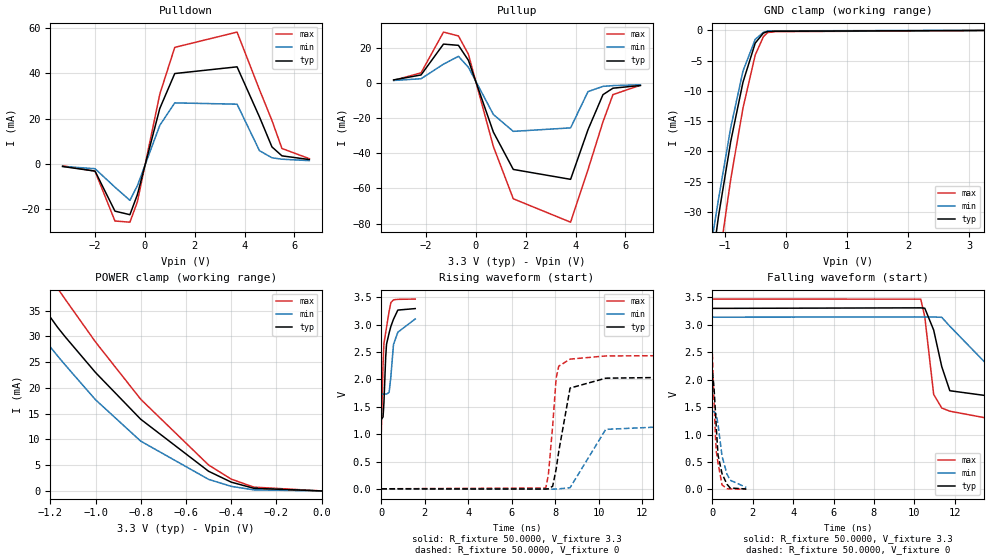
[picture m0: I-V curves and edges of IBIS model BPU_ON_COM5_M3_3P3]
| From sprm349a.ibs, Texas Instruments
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|   Model Cell BPU_ON_COM5_M3_3P3
|BPU_ON_COM5_M3_3P3
[Model]   BPU_ON_COM5_M3_3P3
Model_type   I/O
Polarity   Non-Inverting
Enable   Active-Low
Vinl =  0.8V
Vinh =  2V
Cref =  15.0000pF
Rref =  100.0000M
Vref =  0V
Vmeas =  1.65
C_comp   2.525228p   2.451532p   2.589111p
[Model Spec]
Vinl   0.8V   0.8V   0.8V
Vinh   2V   2V   2V
[Temperature Range]   25   105   0
[Voltage Range]   3.3   3.14   3.47
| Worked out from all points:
|   slope of the pulldown table from 0 to 0.495 V, typ, clamps not added: 23.9 ohm
|   slope of the pullup table from 0 to 0.495 V, typ, clamps not added: 24.3 ohm
|   GND clamp passes 1 mA (typ) near -0.42 V on its own axis
|   POWER clamp passes 1 mA (typ) near -0.34 V on its own axis
|   rising waveform, R_fixture 50.0000, V_fixture 3.3: 20-80 % time 255ps typ, 297ps min, 225ps max; typ from 1.27 V to 3.29 V
|   rising waveform, R_fixture 50.0000, V_fixture 0: 20-80 % time 492ps typ, 2ns min, 289ps max; typ from 0.002 V to 2.13 V
|   falling waveform, R_fixture 50.0000, V_fixture 3.3: 20-80 % time 3.36ns typ, 15.3ns min, 578ps max; typ from 3.3 V to 1.27 V
|   falling waveform, R_fixture 50.0000, V_fixture 0: 20-80 % time 273ps typ, 396ps min, 232ps max; typ from 2.13 V to 0.007 V
[POWER_clamp]
|   voltage   I(typ)   I(min)   I(max)
-3.3V     193.3mA    148.3mA    236.6mA
-1.4V     47.04mA    39.12mA    56.72mA
-1.367V   44.68mA    37.24mA    53.99mA
-1.267V   37.83mA    31.63mA    46.17mA
-1.167V   31.74mA    26.18mA    39.31mA
-1.133V   29.88mA    24.41mA    37.17mA
-1V       23mA       17.71mA    28.93mA
-800mV    13.92mA    9.668mA    17.8mA
-500mV    3.821mA    2.247mA    5.036mA
-400mV    1.709mA    887.2uA    2.294mA
-300mV    512.2uA    206.1uA    738.6uA
0V        124.4nA    164.5nA    588.4nA
[Pulldown]
|   voltage   I(typ)   I(min)   I(max)
-3.3V     -1.114mA   -1.069mA   -794.7uA
-2V       -3.148mA   -2.085mA   -3.182mA
-1.2V     -20.83mA   -10.24mA   -25.19mA
-600mV    -22.41mA   -16.07mA   -25.72mA
-300mV    -13.56mA   -9.625mA   -16.74mA
600mV     24.54mA    17.07mA    30.86mA
1.2V      39.96mA    26.99mA    51.51mA
3.7V      42.92mA    26.42mA    58.27mA
4.6V      20.77mA    5.867mA    32.81mA
5.1V      7.536mA    2.738mA    19.22mA
5.5V      3.599mA    2.106mA    6.854mA
6.6V      1.947mA    1.489mA    2.337mA
[Pullup]
|   voltage   I(typ)   I(min)   I(max)
-3.3V     1.643mA    1.325mA    1.402mA
-2.2V     4.461mA    2.313mA    5.651mA
-1.3V     21.98mA    10.59mA    28.8mA
-700mV    21.27mA    15.04mA    26.61mA
-300mV    12.78mA    8.788mA    16.19mA
700mV     -27.95mA   -17.98mA   -36.11mA
1.5V      -49.2mA    -27.58mA   -65.86mA
3.8V      -54.82mA   -25.6mA    -79.16mA
4.5V      -26.58mA   -4.984mA   -49.27mA
5.1V      -6.729mA   -2.034mA   -22.14mA
5.5V      -3.06mA    -1.59mA    -6.676mA
6.6V      -1.531mA   -1.11mA    -1.421mA
[GND_clamp]
|   voltage   I(typ)   I(min)   I(max)
-3.3V     -222.6mA   -172.9mA   -270.1mA
-1.3V     -46.6mA    -40.78mA   -55.86mA
-1.233V   -41.07mA   -36.44mA   -49.7mA
-1.167V   -35.79mA   -32.16mA   -44.01mA
-1.1V     -30.77mA   -27.93mA   -38.76mA
-900mV    -18.38mA   -16.07mA   -24.63mA
-700mV    -8.573mA   -6.731mA   -12.85mA
-500mV    -2.105mA   -1.482mA   -4.078mA
-366.7mV  -449.6uA   -324.1uA   -1.051mA
-300mV    -187.6uA   -125.9uA   -365.7uA
-166.7mV  -143.3uA   -78.27uA   -204.4uA
3.233V    -8.693uA   10.44uA    -38.25uA
[Ramp]
| variable   typ   min   max
dV/dt_f   1.225063/3.316251n   0.8462889/17.53206n   1.452745/0.5644956n
dV/dt_r   1.282485/0.4887767n  0.8455408/1.375629n   1.485823/0.2877262n
R_load = 50
[Rising Waveform]
R_fixture = 50.0000
V_fixture = 3.3
V_fixture_min = 3.14
V_fixture_max = 3.47
|   time   V(typ)   V(min)   V(max)
0s        1.27V      1.731V     1.063V
80ps      1.315V     1.734V     2.278V
120ps     1.574V     1.734V     2.656V
200ps     2.406V     1.733V     2.855V
240ps     2.643V     1.733V     2.954V
360ps     2.85V      1.764V     3.244V
440ps     2.97V      2.055V     3.403V
560ps     3.1V       2.639V     3.454V
760ps     3.267V     2.863V     3.463V
1.56ns    3.294V     3.104V     3.468V
[Rising Waveform]
R_fixture = 50.0000
V_fixture = 0
V_fixture_min = 0
V_fixture_max = 0
|   time   V(typ)   V(min)   V(max)
0s        2.107mV    1.385mV    2.503mV
7.56ns    -2.298mV   1.381mV    17.27mV
7.68ns    2.664mV    -356.2uV   250.3mV
7.88ns    49.9mV     -4.162mV   1.153V
8.04ns    362.8mV    -33.78uV   2.026V
8.16ns    687.2mV    1.512mV    2.242V
8.68ns    1.842V     22.44mV    2.371V
10.32ns   2.023V     1.088V     2.429V
25.68ns   2.099V     1.362V     2.458V
194.5ns   2.128V     1.386V     2.471V
[Falling Waveform]
R_fixture = 50.0000
V_fixture = 3.3
V_fixture_min = 3.14
V_fixture_max = 3.47
|   time   V(typ)   V(min)   V(max)
0s        3.3V       3.14V      3.47V
10.32ns   3.31V      3.144V     3.468V
10.52ns   3.303V     3.144V     3.147V
10.96ns   2.905V     3.143V     1.732V
11.36ns   2.239V     3.137V     1.484V
11.76ns   1.799V     2.975V     1.426V
13.84ns   1.696V     2.187V     1.283V
21.64ns   1.526V     2.081V     1.141V
80.16ns   1.306V     1.862V     1.066V
278.3ns   1.272V     1.759V     1.063V
[Falling Waveform]
R_fixture = 50.0000
V_fixture = 0
V_fixture_min = 0
V_fixture_max = 0
|   time   V(typ)   V(min)   V(max)
0s        2.132V     1.415V     2.471V
40ps      2.017V     1.42V      1.987V
80ps      1.86V      1.416V     1.642V
160ps     1.376V     1.385V     905.7mV
200ps     1.088V     1.347V     683.4mV
280ps     627.6mV    1.192V     481.4mV
480ps     286.9mV    604.6mV    81.94mV
720ps     96.78mV    283.1mV    12.15mV
880ps     25.76mV    168.3mV    8.764mV
1.68ns    7.473mV    35.67mV    4.659mV
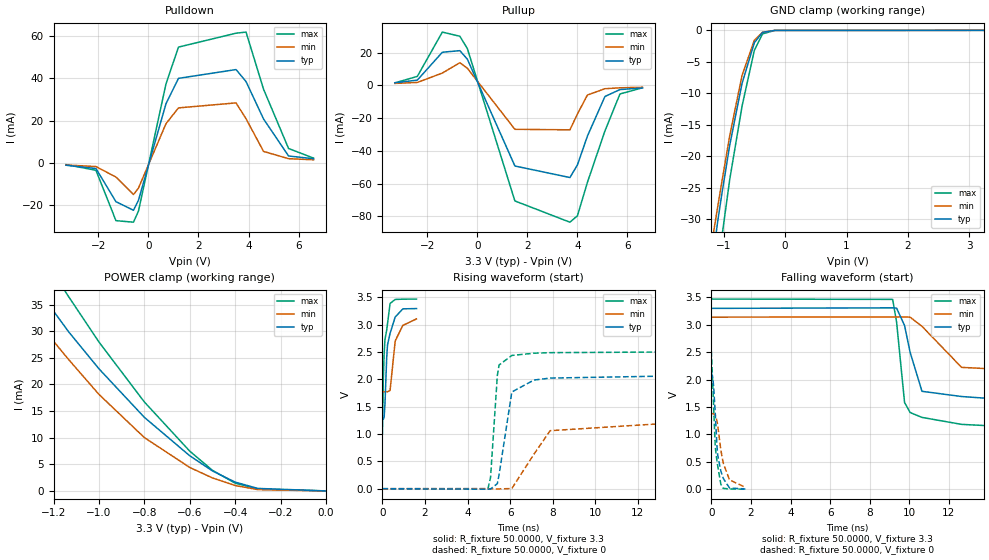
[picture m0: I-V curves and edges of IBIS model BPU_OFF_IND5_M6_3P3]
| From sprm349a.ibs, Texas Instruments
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|   Model Cell BPU_OFF_IND5_M6_3P3
|BPU_OFF_IND5_M6_3P3
[Model]   BPU_OFF_IND5_M6_3P3
Model_type   I/O
Polarity   Non-Inverting
Enable   Active-Low
Vinl =  0.8V
Vinh =  2V
Cref =  15.0000pF
Rref =  100.0000M
Vref =  0V
Vmeas =  1.65
C_comp   2.525228p   2.457323p   2.5883p
[Model Spec]
Vinl   0.8V   0.8V   0.8V
Vinh   2V   2V   2V
[Temperature Range]   25   125   -40
[Voltage Range]   3.3   3.14   3.47
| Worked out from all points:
|   slope of the pulldown table from 0 to 0.495 V, typ, clamps not added: 23.9 ohm
|   slope of the pullup table from 0 to 0.495 V, typ, clamps not added: 24.3 ohm
|   GND clamp passes 1 mA (typ) near -0.44 V on its own axis
|   POWER clamp passes 1 mA (typ) near -0.34 V on its own axis
|   rising waveform, R_fixture 50.0000, V_fixture 3.3: 20-80 % time 258ps typ, 305ps min, 205ps max; typ from 1.27 V to 3.29 V
|   rising waveform, R_fixture 50.0000, V_fixture 0: 20-80 % time 491ps typ, 1.74ns min, 249ps max; typ from 0 V to 2.12 V
|   falling waveform, R_fixture 50.0000, V_fixture 3.3: 20-80 % time 3.3ns typ, 13.4ns min, 480ps max; typ from 3.3 V to 1.27 V
|   falling waveform, R_fixture 50.0000, V_fixture 0: 20-80 % time 272ps typ, 406ps min, 227ps max; typ from 2.13 V to 0.005 V
[POWER_clamp]
|   voltage   I(typ)   I(min)   I(max)
-3.3V     193.2mA    143.1mA    237mA
-1.367V   44.66mA    36.94mA    52.43mA
-1.267V   37.82mA    31.58mA    45.28mA
-1.233V   35.69mA    29.81mA    43.03mA
-1.133V   29.86mA    24.65mA    36.45mA
-1V       22.94mA    18.13mA    27.97mA
-800mV    13.82mA    10.02mA    16.71mA
-600mV    6.603mA    4.409mA    7.469mA
-500mV    3.754mA    2.442mA    3.871mA
-400mV    1.654mA    1.017mA    1.458mA
-300mV    470.4uA    244.3uA    357uA
0V        124.8nA    283.5nA    244.8nA
[Pulldown]
|   voltage   I(typ)   I(min)   I(max)
-3.3V     -1.114mA   -1.012mA   -823.1uA
-2.1V     -2.679mA   -1.748mA   -3.506mA
-1.3V     -18.35mA   -6.707mA   -27.33mA
-600mV    -22.41mA   -14.98mA   -28.06mA
-400mV    -17.7mA    -11.92mA   -22.83mA
700mV     27.97mA    18.52mA    37.33mA
1.2V      39.96mA    26mA       54.75mA
3.5V      44.13mA    28.36mA    61.33mA
3.9V      38.45mA    20.87mA    61.85mA
4.6V      20.77mA    5.42mA     34.85mA
5.6V      3.253mA    1.971mA    6.797mA
6.6V      1.947mA    1.463mA    2.247mA
[Pullup]
|   voltage   I(typ)   I(min)   I(max)
-3.3V     1.643mA    1.25mA     1.577mA
-2.4V     3.267mA    1.842mA    5.538mA
-1.4V     20.3mA     7.59mA     32.61mA
-700mV    21.27mA    13.88mA    30.06mA
-400mV    16.07mA    10.5mA     22.53mA
1.5V      -49.2mA    -26.79mA   -70.55mA
3.7V      -56.25mA   -27.1mA    -83.53mA
4V        -48.55mA   -17.42mA   -79.6mA
4.4V      -30.91mA   -5.837mA   -59.17mA
5.1V      -6.727mA   -1.984mA   -27.77mA
5.7V      -2.505mA   -1.435mA   -5.194mA
6.6V      -1.531mA   -1.098mA   -1.42mA
[GND_clamp]
|   voltage   I(typ)   I(min)   I(max)
-3.3V     -222.4mA   -166.8mA   -270.5mA
-1.3V     -46.48mA   -40.6mA    -53.7mA
-1.233V   -40.94mA   -36.46mA   -48.38mA
-1.167V   -35.67mA   -32.36mA   -43.2mA
-1.1V     -30.65mA   -28.29mA   -38.14mA
-1.033V   -26.29mA   -24.35mA   -33.2mA
-900mV    -18.25mA   -16.74mA   -23.69mA
-700mV    -8.44mA    -7.173mA   -12.06mA
-500mV    -1.97mA    -1.571mA   -3.186mA
-366.7mV  -314.2uA   -311.1uA   -556.3uA
-166.7mV  -8.153uA   -10.52uA   -9.993uA
3.233V    68.23nA    4.312uA    201.3nA
[Ramp]
| variable   typ   min   max
dV/dt_f   1.228027/3.277183n   0.8228747/15.5442n   1.490897/0.4512973n
dV/dt_r   1.282964/0.4904672n  0.8243823/1.382582n   1.520633/0.2479827n
R_load = 50
[Rising Waveform]
R_fixture = 50.0000
V_fixture = 3.3
V_fixture_min = 3.14
V_fixture_max = 3.47
|   time   V(typ)   V(min)   V(max)
0s        1.266V     1.771V     999.7mV
40ps      1.268V     1.773V     1.969V
80ps      1.305V     1.774V     2.468V
120ps     1.554V     1.774V     2.73V
200ps     2.388V     1.773V     2.898V
240ps     2.632V     1.773V     3.02V
360ps     2.842V     1.797V     3.388V
600ps     3.139V     2.702V     3.461V
960ps     3.289V     2.987V     3.466V
1.6ns     3.294V     3.105V     3.468V
[Rising Waveform]
R_fixture = 50.0000
V_fixture = 0
V_fixture_min = 0
V_fixture_max = 0
|   time   V(typ)   V(min)   V(max)
0s        48.63uV    42.54uV    58.52uV
4.96ns    -8.473mV   100.1uV    728.9uV
5.08ns    -5.456mV   -11.8uV    206.7mV
5.4ns     93.31mV    -5.743mV   2.071V
5.48ns    252.1mV    -3.893mV   2.261V
6.08ns    1.769V     3.246mV    2.437V
7.12ns    1.987V     631.9mV    2.478V
7.88ns    2.023V     1.061V     2.488V
18.08ns   2.092V     1.311V     2.51V
130.1ns   2.12V      1.348V     2.524V
[Falling Waveform]
R_fixture = 50.0000
V_fixture = 3.3
V_fixture_min = 3.14
V_fixture_max = 3.47
|   time   V(typ)   V(min)   V(max)
0s        3.3V       3.14V      3.47V
9.16ns    3.31V      3.144V     3.464V
9.36ns    3.303V     3.144V     3.043V
9.76ns    2.987V     3.144V     1.584V
10.04ns   2.5V       3.14V      1.4V
10.64ns   1.787V     2.973V     1.311V
12.64ns   1.692V     2.224V     1.184V
18.16ns   1.553V     2.123V     1.081V
71.28ns   1.308V     1.9V       1.002V
247.6ns   1.268V     1.799V     999.7mV
[Falling Waveform]
R_fixture = 50.0000
V_fixture = 0
V_fixture_min = 0
V_fixture_max = 0
|   time   V(typ)   V(min)   V(max)
0s        2.13V      1.376V     2.525V
80ps      2.017V     1.381V     1.863V
120ps     1.861V     1.377V     1.469V
200ps     1.378V     1.348V     766.5mV
280ps     817.5mV    1.258V     530.3mV
320ps     625.7mV    1.174V     431.6mV
480ps     333.8mV    718.6mV    94.14mV
600ps     200.5mV    479.1mV    16.37mV
920ps     22.63mV    171.3mV    5.16mV
1.72ns    5.191mV    34.22mV    1.635mV
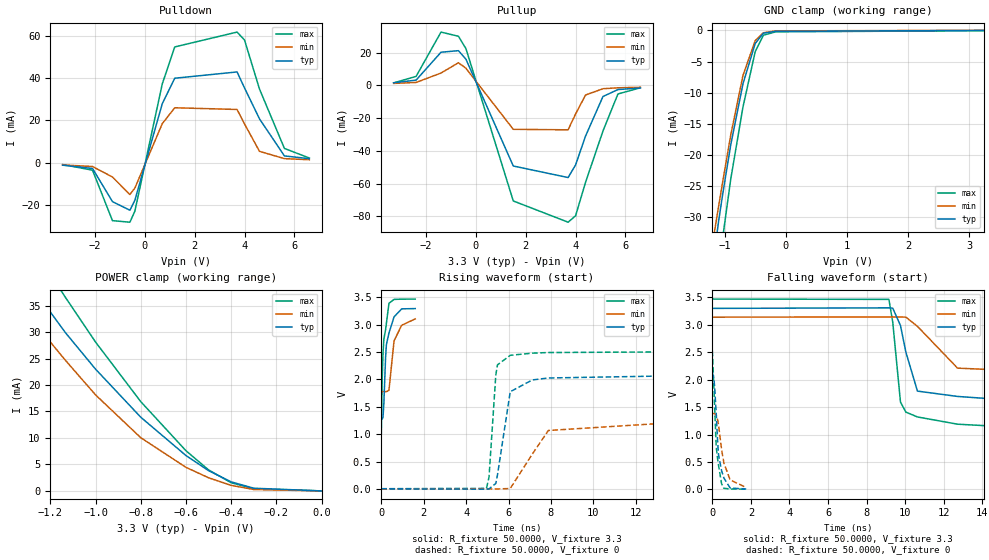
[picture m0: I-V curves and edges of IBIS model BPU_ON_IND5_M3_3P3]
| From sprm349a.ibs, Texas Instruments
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|   Model Cell BPU_ON_IND5_M3_3P3
|BPU_ON_IND5_M3_3P3
[Model]   BPU_ON_IND5_M3_3P3
Model_type   I/O
Polarity   Non-Inverting
Enable   Active-Low
Vinl =  0.8V
Vinh =  2V
Cref =  15.0000pF
Rref =  100.0000M
Vref =  0V
Vmeas =  1.65
C_comp   2.525228p   2.457323p   2.5883p
[Model Spec]
Vinl   0.8V   0.8V   0.8V
Vinh   2V   2V   2V
[Temperature Range]   25   125   -40
[Voltage Range]   3.3   3.14   3.47
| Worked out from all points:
|   slope of the pulldown table from 0 to 0.495 V, typ, clamps not added: 23.9 ohm
|   slope of the pullup table from 0 to 0.495 V, typ, clamps not added: 24.3 ohm
|   GND clamp passes 1 mA (typ) near -0.42 V on its own axis
|   POWER clamp passes 1 mA (typ) near -0.34 V on its own axis
|   rising waveform, R_fixture 50.0000, V_fixture 3.3: 20-80 % time 255ps typ, 304ps min, 203ps max; typ from 1.27 V to 3.29 V
|   rising waveform, R_fixture 50.0000, V_fixture 0: 20-80 % time 490ps typ, 1.67ns min, 249ps max; typ from 0.002 V to 2.12 V
|   falling waveform, R_fixture 50.0000, V_fixture 3.3: 20-80 % time 3.37ns typ, 13.4ns min, 485ps max; typ from 3.3 V to 1.27 V
|   falling waveform, R_fixture 50.0000, V_fixture 0: 20-80 % time 273ps typ, 409ps min, 229ps max; typ from 2.13 V to 0.007 V
[POWER_clamp]
|   voltage   I(typ)   I(min)   I(max)
-3.3V     193.3mA    143.1mA    237mA
-1.367V   44.68mA    36.95mA    52.45mA
-1.267V   37.83mA    31.58mA    45.31mA
-1.233V   35.71mA    29.82mA    43.08mA
-1.133V   29.88mA    24.66mA    36.54mA
-1V       23mA       18.14mA    28.12mA
-800mV    13.92mA    10.05mA    16.86mA
-600mV    6.68mA     4.453mA    7.588mA
-500mV    3.821mA    2.481mA    3.973mA
-400mV    1.709mA    1.049mA    1.541mA
-300mV    512.2uA    269.1uA    419.9uA
0V        124.4nA    283.2nA    244.9nA
[Pulldown]
|   voltage   I(typ)   I(min)   I(max)
-3.3V     -1.114mA   -1.012mA   -823uA
-2.1V     -2.679mA   -1.748mA   -3.506mA
-1.3V     -18.35mA   -6.707mA   -27.33mA
-600mV    -22.41mA   -14.98mA   -28.06mA
-400mV    -17.7mA    -11.92mA   -22.83mA
700mV     27.96mA    18.52mA    37.33mA
1.2V      39.96mA    26mA       54.75mA
3.7V      42.93mA    25.2mA     61.76mA
4V        35.36mA    18.36mA    58mA
4.6V      20.77mA    5.42mA     34.85mA
5.6V      3.253mA    1.971mA    6.797mA
6.6V      1.947mA    1.463mA    2.247mA
[Pullup]
|   voltage   I(typ)   I(min)   I(max)
-3.3V     1.643mA    1.25mA     1.577mA
-2.4V     3.267mA    1.842mA    5.538mA
-1.4V     20.3mA     7.59mA     32.61mA
-700mV    21.26mA    13.88mA    30.06mA
-400mV    16.07mA    10.5mA     22.53mA
1.5V      -49.2mA    -26.79mA   -70.55mA
3.7V      -56.25mA   -27.1mA    -83.53mA
4V        -48.55mA   -17.42mA   -79.6mA
4.4V      -30.91mA   -5.837mA   -59.18mA
5.1V      -6.727mA   -1.984mA   -27.78mA
5.7V      -2.505mA   -1.435mA   -5.194mA
6.6V      -1.531mA   -1.098mA   -1.42mA
[GND_clamp]
|   voltage   I(typ)   I(min)   I(max)
-3.3V     -222.6mA   -166.9mA   -270.7mA
-1.3V     -46.6mA    -40.66mA   -53.91mA
-1.233V   -41.07mA   -36.52mA   -48.59mA
-1.167V   -35.79mA   -32.42mA   -43.4mA
-1.1V     -30.77mA   -28.35mA   -38.35mA
-1.033V   -26.41mA   -24.41mA   -33.41mA
-900mV    -18.38mA   -16.81mA   -23.9mA
-700mV    -8.573mA   -7.237mA   -12.29mA
-500mV    -2.105mA   -1.638mA   -3.408mA
-366.7mV  -449.6uA   -378.4uA   -778.1uA
-166.7mV  -143.3uA   -77.62uA   -231.6uA
3.233V    -8.695uA   11.82uA    -45.03uA
[Ramp]
| variable   typ   min   max
dV/dt_f   1.225136/3.348076n   0.8209858/15.61952n   1.488323/0.4565335n
dV/dt_r   1.282465/0.4889542n  0.8250069/1.378678n   1.519228/0.2471564n
R_load = 50
[Rising Waveform]
R_fixture = 50.0000
V_fixture = 3.3
V_fixture_min = 3.14
V_fixture_max = 3.47
|   time   V(typ)   V(min)   V(max)
0s        1.27V      1.774V     1.004V
40ps      1.273V     1.777V     1.978V
80ps      1.31V      1.777V     2.478V
120ps     1.559V     1.777V     2.737V
200ps     2.394V     1.776V     2.904V
240ps     2.637V     1.776V     3.026V
360ps     2.847V     1.8V       3.39V
600ps     3.142V     2.705V     3.462V
960ps     3.289V     2.989V     3.466V
1.6ns     3.294V     3.106V     3.468V
[Rising Waveform]
R_fixture = 50.0000
V_fixture = 0
V_fixture_min = 0
V_fixture_max = 0
|   time   V(typ)   V(min)   V(max)
0s        2.107mV    1.369mV    2.824mV
4.96ns    -5.414mV   1.427mV    9.116mV
5.08ns    -511uV     1.315mV    215.7mV
5.4ns     99.42mV    -3.33mV    2.081V
5.48ns    258.2mV    -1.185mV   2.267V
6.08ns    1.775V     6.513mV    2.44V
7.12ns    1.99V      635.4mV    2.48V
7.88ns    2.026V     1.067V     2.491V
18.04ns   2.094V     1.314V     2.512V
129.8ns   2.123V     1.351V     2.526V
[Falling Waveform]
R_fixture = 50.0000
V_fixture = 3.3
V_fixture_min = 3.14
V_fixture_max = 3.47
|   time   V(typ)   V(min)   V(max)
0s        3.3V       3.14V      3.47V
9.16ns    3.31V      3.144V     3.464V
9.36ns    3.303V     3.144V     3.044V
9.76ns    2.988V     3.144V     1.592V
10.04ns   2.502V     3.14V      1.409V
10.64ns   1.792V     2.973V     1.321V
12.72ns   1.695V     2.211V     1.189V
18.2ns    1.559V     2.125V     1.086V
71.36ns   1.314V     1.903V     1.007V
247.9ns   1.273V     1.802V     1.004V
[Falling Waveform]
R_fixture = 50.0000
V_fixture = 0
V_fixture_min = 0
V_fixture_max = 0
|   time   V(typ)   V(min)   V(max)
0s        2.132V     1.379V     2.527V
80ps      2.019V     1.384V     1.867V
120ps     1.864V     1.38V      1.474V
200ps     1.383V     1.351V     774.5mV
280ps     823.6mV    1.261V     538.2mV
320ps     630.7mV    1.177V     440.3mV
480ps     339.7mV    721.9mV    101.5mV
600ps     206.9mV    481.7mV    19.94mV
920ps     26.13mV    174.7mV    8.159mV
1.76ns    7.27mV     32.99mV    4.471mV
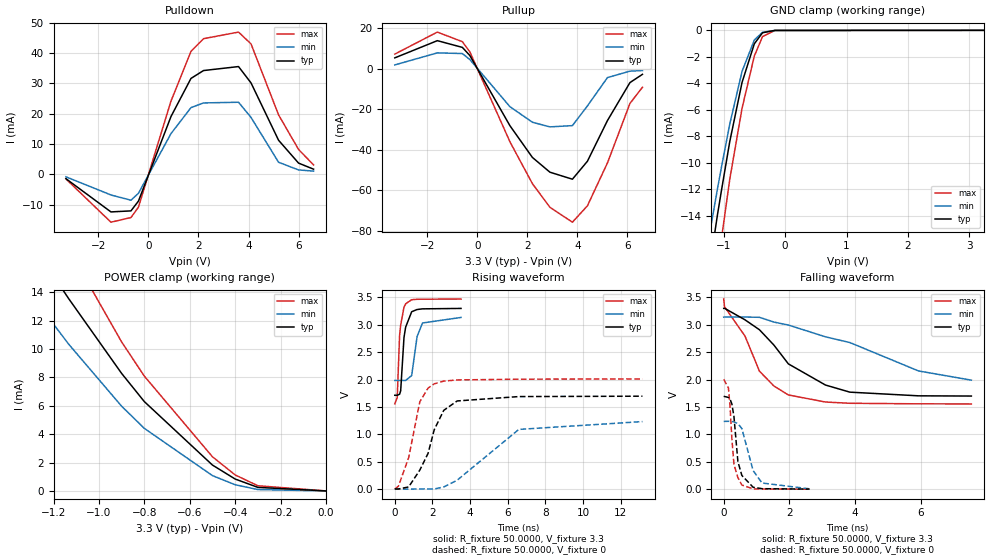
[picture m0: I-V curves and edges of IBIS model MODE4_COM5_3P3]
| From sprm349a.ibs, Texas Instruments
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|   Model Cell MODE4_COM5_3P3
|MODE4_COM5_3P3
[Model]   MODE4_COM5_3P3
Model_type   I/O
Polarity   Non-Inverting
Enable   Active-Low
Vinl =  0.8V
Vinh =  2V
Cref =  15.0000pF
Rref =  100.0000M
Vref =  0V
Vmeas =  1.65
C_comp   1.505368p   1.470769p   1.543249p
[Model Spec]
Vinl   0.8V   0.8V   0.8V
Vinh   2V   2V   2V
[Temperature Range]   25   105   0
[Voltage Range]   3.3   3.14   3.47
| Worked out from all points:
|   slope of the pulldown table from 0 to 0.495 V, typ, clamps not added: 45.6 ohm
|   slope of the pullup table from 0 to 0.495 V, typ, clamps not added: 44.5 ohm
|   GND clamp passes 1 mA (typ) near -0.50 V on its own axis
|   POWER clamp passes 1 mA (typ) near -0.42 V on its own axis
|   rising waveform, R_fixture 50.0000, V_fixture 3.3: 20-80 % time 215ps typ, 313ps min, 176ps max; typ from 1.71 V to 3.3 V
|   rising waveform, R_fixture 50.0000, V_fixture 0: 20-80 % time 1.12ns typ, 2.25ns min, 778ps max; typ from 0 V to 1.7 V
|   falling waveform, R_fixture 50.0000, V_fixture 3.3: 20-80 % time 1.76ns typ, 3.12ns min, 1.1ns max; typ from 3.3 V to 1.7 V
|   falling waveform, R_fixture 50.0000, V_fixture 0: 20-80 % time 188ps typ, 353ps min, 151ps max; typ from 1.7 V to 0.002 V
[POWER_clamp]
|   voltage   I(typ)   I(min)   I(max)
-3.3V     77.66mA    59.58mA    94.92mA
-1.467V   22.04mA    17.65mA    27.25mA
-1.433V   21.11mA    16.89mA    26.17mA
-1.3V     17.58mA    13.9mA     22.02mA
-1.267V   16.76mA    13.17mA    21.02mA
-1.133V   13.55mA    10.34mA    17.06mA
-900mV    8.283mA    5.971mA    10.5mA
-800mV    6.297mA    4.41mA     8.092mA
-500mV    1.823mA    1.08mA     2.408mA
-400mV    839.2uA    436.8uA    1.129mA
-300mV    250.4uA    97.14uA    364.9uA
0V        111.9nA    124.3nA    531nA
[Pulldown]
|   voltage   I(typ)   I(min)   I(max)
-3.3V     -1.458mA   -835.8uA   -1.527mA
-1.5V     -12.42mA   -6.829mA   -15.81mA
-700mV    -12.08mA   -8.564mA   -14.28mA
-400mV    -8.847mA   -6.265mA   -10.85mA
900mV     19.04mA    13.41mA    24.14mA
1.7V      31.62mA    21.98mA    40.55mA
2.2V      34.21mA    23.53mA    44.72mA
3.6V      35.53mA    23.76mA    46.9mA
4.1V      30.13mA    18.74mA    43mA
5.2V      11.23mA    3.964mA    19.6mA
6V        3.677mA    1.429mA    8.174mA
6.6V      1.68mA     1.044mA    3.085mA
[Pullup]
|   voltage   I(typ)   I(min)   I(max)
-3.3V     5.462mA    1.977mA    7.321mA
-1.6V     13.96mA    7.929mA    18.2mA
-600mV    10.64mA    7.595mA    13.46mA
-300mV    6.621mA    4.642mA    8.418mA
1.3V      -28.03mA   -18.64mA   -35.96mA
2.2V      -43.74mA   -26.36mA   -56.69mA
2.9V      -51.03mA   -28.64mA   -68.37mA
3.8V      -54.5mA    -28.02mA   -75.74mA
4.4V      -45.61mA   -18.27mA   -67.62mA
5.2V      -25.52mA   -4.294mA   -46.47mA
6.1V      -6.753mA   -1.088mA   -17.05mA
6.6V      -2.667mA   -792.5uA   -9.051mA
[GND_clamp]
|   voltage   I(typ)   I(min)   I(max)
-3.3V     -92.32mA   -71.66mA   -112mA
-1.367V   -22.52mA   -19.07mA   -27.73mA
-1.3V     -20.2mA    -17.26mA   -25.12mA
-1.233V   -18.02mA   -15.47mA   -22.69mA
-1.1V     -13.91mA   -11.95mA   -17.94mA
-1.033V   -12.02mA   -10.27mA   -15.65mA
-900mV    -8.388mA   -7.071mA   -11.23mA
-700mV    -3.928mA   -3.096mA   -5.88mA
-500mV    -1.013mA   -728.6uA   -1.937mA
-366.7mV  -181uA     -146.2uA   -469.5uA
-166.7mV  -5.4uA     -4.986uA   -10.95uA
3.233V    80.14nA    1.447uA    400.1nA
[Ramp]
| variable   typ   min   max
dV/dt_f  0.9685267/1.779134n   0.742183/3.39646n   1.160033/1.115746n
dV/dt_r   1.022261/1.127122n   0.7543207/2.318294n   1.210182/0.7820198n
R_load = 50
[Rising Waveform]
R_fixture = 50.0000
V_fixture = 3.3
V_fixture_min = 3.14
V_fixture_max = 3.47
|   time   V(typ)   V(min)   V(max)
0s        1.712V     1.983V     1.556V
128ps     1.711V     1.983V     1.669V
256ps     1.732V     1.983V     2.816V
312ps     1.793V     1.983V     2.996V
488ps     2.769V     1.983V     3.321V
576ps     2.957V     1.983V     3.384V
896ps     3.238V     2.072V     3.458V
1.184ns   3.279V     2.786V     3.466V
1.472ns   3.291V     3.033V     3.468V
3.52ns    3.299V     3.134V     3.47V
[Rising Waveform]
R_fixture = 50.0000
V_fixture = 0
V_fixture_min = 0
V_fixture_max = 0
|   time   V(typ)   V(min)   V(max)
0s        45.63uV    22.73uV    74.16uV
192ps     -1.3mV     -594.6uV   49.39mV
736ps     36.74mV    -4.106mV   572.5mV
1.328ns   343.7mV    -78.42uV   1.594V
1.768ns   650.8mV    -6.552uV   1.843V
2.096ns   1.083V     328.8uV    1.921V
2.6ns     1.436V     35.46mV    1.971V
3.312ns   1.608V     159.7mV    1.992V
6.592ns   1.688V     1.088V     2.006V
13.16ns   1.695V     1.231V     2.01V
[Falling Waveform]
R_fixture = 50.0000
V_fixture = 3.3
V_fixture_min = 3.14
V_fixture_max = 3.47
|   time   V(typ)   V(min)   V(max)
0s        3.3V       3.14V      3.47V
24ps      3.302V     3.143V     3.331V
648ps     3.091V     3.142V     2.794V
1.088ns   2.91V      3.137V     2.154V
1.528ns   2.63V      3.05V      1.883V
1.968ns   2.287V     2.996V     1.72V
3.096ns   1.901V     2.781V     1.591V
3.84ns    1.771V     2.676V     1.568V
5.928ns   1.704V     2.158V     1.558V
7.536ns   1.7V       1.99V      1.556V
[Falling Waveform]
R_fixture = 50.0000
V_fixture = 0
V_fixture_min = 0
V_fixture_max = 0
|   time   V(typ)   V(min)   V(max)
0s        1.695V     1.237V     2.007V
144ps     1.675V     1.239V     1.848V
192ps     1.643V     1.238V     1.519V
248ps     1.558V     1.235V     930.1mV
312ps     1.324V     1.228V     450.1mV
432ps     503.6mV    1.197V     212mV
552ps     251.3mV    1.107V     75.75mV
896ps     35.04mV    337.7mV    6.173mV
1.168ns   9.031mV    112.8mV    3.087mV
2.616ns   1.749mV    6.347mV    443.8uV
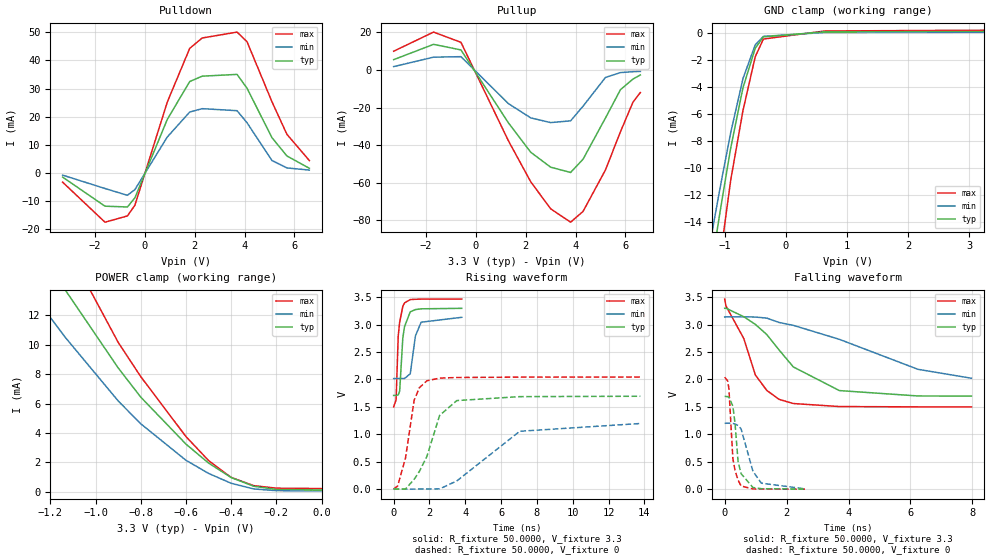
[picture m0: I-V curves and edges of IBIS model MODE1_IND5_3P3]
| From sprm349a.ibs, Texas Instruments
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|   Model Cell MODE1_IND5_3P3
|MODE1_IND5_3P3
[Model]   MODE1_IND5_3P3
Model_type   I/O
Polarity   Non-Inverting
Enable   Active-Low
Vinl =  0.8V
Vinh =  2V
Cref =  15.0000pF
Rref =  100.0000M
Vref =  0V
Vmeas =  1.65
C_comp   1.505368p   1.470825p   1.542832p
[Model Spec]
Vinl   0.8V   0.8V   0.8V
Vinh   2V   2V   2V
[Temperature Range]   25   125   -40
[Voltage Range]   3.3   3.14   3.47
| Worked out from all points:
|   slope of the pulldown table from 0 to 0.495 V, typ, clamps not added: 45.6 ohm
|   slope of the pullup table from 0 to 0.495 V, typ, clamps not added: 44.5 ohm
|   GND clamp passes 1 mA (typ) near -0.49 V on its own axis
|   POWER clamp passes 1 mA (typ) near -0.40 V on its own axis
|   rising waveform, R_fixture 50.0000, V_fixture 3.3: 20-80 % time 216ps typ, 320ps min, 170ps max; typ from 1.71 V to 3.3 V
|   rising waveform, R_fixture 50.0000, V_fixture 0: 20-80 % time 1.12ns typ, 2.39ns min, 626ps max; typ from 0 V to 1.69 V
|   falling waveform, R_fixture 50.0000, V_fixture 3.3: 20-80 % time 1.77ns typ, 3.22ns min, 903ps max; typ from 3.3 V to 1.7 V
|   falling waveform, R_fixture 50.0000, V_fixture 0: 20-80 % time 186ps typ, 363ps min, 142ps max; typ from 1.69 V to 0.002 V
[POWER_clamp]
|   voltage   I(typ)   I(min)   I(max)
-3.3V     77.9mA     57.63mA    95.03mA
-1.433V   21.27mA    16.78mA    26.06mA
-1.267V   16.91mA    13.21mA    20.88mA
-1.133V   13.69mA    10.48mA    16.82mA
-900mV    8.425mA    6.183mA    10.16mA
-800mV    6.437mA    4.629mA    7.826mA
-600mV    3.248mA    2.149mA    3.759mA
-500mV    1.961mA    1.259mA    2.13mA
-400mV    975.9uA    588.8uA    987.4uA
-300mV    386.7uA    204.1uA    427.4uA
-200mV    168.8uA    89.69uA    256.3uA
0V        135.2uA    73.11uA    232.2uA
[Pulldown]
|   voltage   I(typ)   I(min)   I(max)
-3.3V     -1.459mA   -754.7uA   -3.261mA
-1.6V     -11.8mA    -5.515mA   -17.49mA
-700mV    -12.08mA   -7.934mA   -15.27mA
-400mV    -8.847mA   -5.917mA   -11.47mA
900mV     19.04mA    12.79mA    25.2mA
1.8V      32.51mA    21.67mA    44.31mA
2.3V      34.42mA    22.87mA    47.99mA
3.7V      35.05mA    22.15mA    50.09mA
4.1V      30.14mA    17.86mA    46.67mA
5.1V      12.56mA    4.446mA    25.33mA
5.7V      6.053mA    1.803mA    13.75mA
6.6V      1.68mA     1.035mA    4.434mA
[Pullup]
|   voltage   I(typ)   I(min)   I(max)
-3.3V     5.462mA    1.756mA    9.935mA
-1.7V     13.59mA    6.784mA    20.11mA
-600mV    10.64mA    7.053mA    14.67mA
1.3V      -28.03mA   -17.84mA   -37.53mA
2.2V      -43.74mA   -25.48mA   -59.43mA
3V        -51.68mA   -27.98mA   -73.8mA
3.8V      -54.49mA   -27.05mA   -80.91mA
4.3V      -47.44mA   -19.28mA   -75.18mA
5.2V      -25.52mA   -3.988mA   -53.13mA
5.8V      -10.51mA   -1.411mA   -32.89mA
6.3V      -4.864mA   -936.6uA   -17.2mA
6.6V      -2.666mA   -790.5uA   -12mA
[GND_clamp]
|   voltage   I(typ)   I(min)   I(max)
-3.3V     -92.32mA   -69.2mA    -111.6mA
-1.3V     -20.22mA   -17.2mA    -24.85mA
-1.233V   -18.05mA   -15.49mA   -22.44mA
-1.167V   -15.97mA   -13.8mA    -20.05mA
-1.1V     -13.98mA   -12.12mA   -17.67mA
-1.033V   -12.11mA   -10.49mA   -15.34mA
-900mV    -8.502mA   -7.365mA   -10.89mA
-700mV    -4.041mA   -3.36mA    -5.732mA
-500mV    -1.111mA   -859uA     -1.741mA
-366.7mV  -262.4uA   -226uA     -425.3uA
633.3mV   110.1uA    61.95uA    173.6uA
3.233V    135uA      75.49uA    231.1uA
[Ramp]
| variable   typ   min   max
dV/dt_f  0.9681548/1.780889n   0.7193844/3.515417n   1.189569/0.912397n
dV/dt_r   1.02031/1.127056n   0.7317725/2.462979n   1.230418/0.6280915n
R_load = 50
[Rising Waveform]
R_fixture = 50.0000
V_fixture = 3.3
V_fixture_min = 3.14
V_fixture_max = 3.47
|   time   V(typ)   V(min)   V(max)
0s        1.707V     2.015V     1.5V
136ps     1.707V     2.016V     1.625V
256ps     1.716V     2.016V     2.797V
336ps     1.786V     2.016V     3.043V
512ps     2.756V     2.016V     3.332V
608ps     2.963V     2.015V     3.395V
928ps     3.233V     2.104V     3.456V
1.216ns   3.273V     2.793V     3.461V
1.536ns   3.287V     3.043V     3.464V
3.8ns     3.296V     3.132V     3.465V
[Rising Waveform]
R_fixture = 50.0000
V_fixture = 0
V_fixture_min = 0
V_fixture_max = 0
|   time   V(typ)   V(min)   V(max)
0s        45.68uV    24.29uV    74.31uV
224ps     -3.064mV   -185.4uV   54.15mV
664ps     842uV      -2.218mV   569mV
1.144ns   176.3mV    -1.202mV   1.618V
1.432ns   318.4mV    -132.6uV   1.846V
1.856ns   593.8mV    35.2uV     1.974V
2.568ns   1.343V     2.212mV    2.023V
3.528ns   1.613V     147.1mV    2.034V
7.04ns    1.685V     1.053V     2.041V
13.78ns   1.692V     1.195V     2.043V
[Falling Waveform]
R_fixture = 50.0000
V_fixture = 3.3
V_fixture_min = 3.14
V_fixture_max = 3.47
|   time   V(typ)   V(min)   V(max)
0s        3.297V     3.138V     3.465V
40ps      3.299V     3.14V      3.34V
616ps     3.143V     3.142V     2.746V
992ps     3.003V     3.137V     2.079V
1.36ns    2.818V     3.118V     1.8V
1.752ns   2.541V     3.039V     1.638V
2.216ns   2.228V     2.986V     1.561V
3.704ns   1.797V     2.731V     1.506V
6.24ns    1.699V     2.185V     1.5V
7.968ns   1.696V     2.022V     1.499V
[Falling Waveform]
R_fixture = 50.0000
V_fixture = 0
V_fixture_min = 0
V_fixture_max = 0
|   time   V(typ)   V(min)   V(max)
0s        1.692V     1.201V     2.041V
96ps      1.686V     1.202V     1.974V
136ps     1.675V     1.202V     1.833V
264ps     1.514V     1.197V     555.5mV
336ps     1.187V     1.188V     338.8mV
432ps     502.4mV    1.161V     165.5mV
528ps     283.9mV    1.101V     57.81mV
912ps     30.91mV    326.2mV    4.411mV
1.184ns   8.478mV    109.6mV    2.409mV
2.592ns   1.704mV    6.394mV    320.8uV
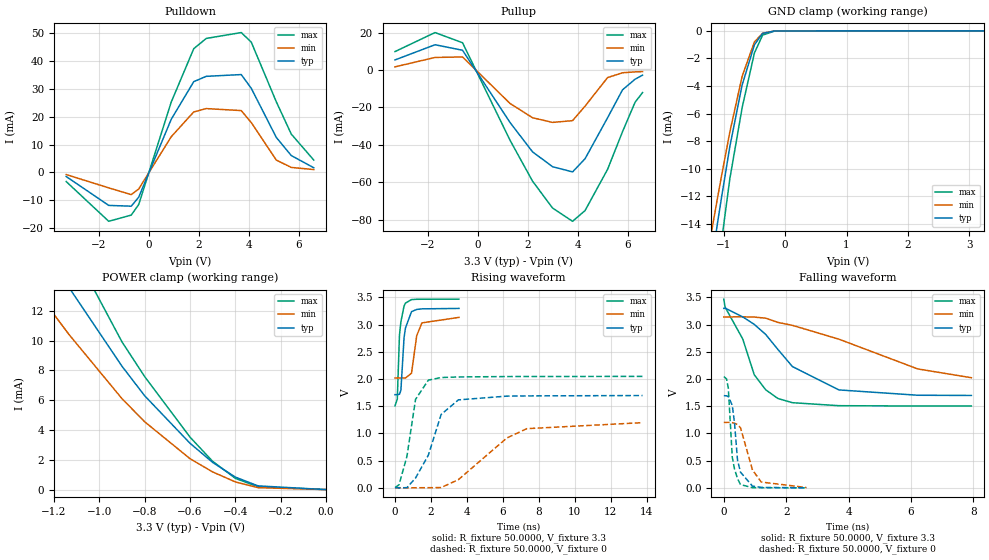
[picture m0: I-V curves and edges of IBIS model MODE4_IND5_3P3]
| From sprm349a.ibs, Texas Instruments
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|   Model Cell MODE4_IND5_3P3
|MODE4_IND5_3P3
[Model]   MODE4_IND5_3P3
Model_type   I/O
Polarity   Non-Inverting
Enable   Active-Low
Vinl =  0.8V
Vinh =  2V
Cref =  15.0000pF
Rref =  100.0000M
Vref =  0V
Vmeas =  1.65
C_comp   1.505368p   1.470825p   1.542832p
[Model Spec]
Vinl   0.8V   0.8V   0.8V
Vinh   2V   2V   2V
[Temperature Range]   25   125   -40
[Voltage Range]   3.3   3.14   3.47
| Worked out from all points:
|   slope of the pulldown table from 0 to 0.495 V, typ, clamps not added: 45.6 ohm
|   slope of the pullup table from 0 to 0.495 V, typ, clamps not added: 44.5 ohm
|   GND clamp passes 1 mA (typ) near -0.50 V on its own axis
|   POWER clamp passes 1 mA (typ) near -0.42 V on its own axis
|   rising waveform, R_fixture 50.0000, V_fixture 3.3: 20-80 % time 215ps typ, 319ps min, 168ps max; typ from 1.71 V to 3.3 V
|   rising waveform, R_fixture 50.0000, V_fixture 0: 20-80 % time 1.12ns typ, 2.39ns min, 625ps max; typ from 0 V to 1.7 V
|   falling waveform, R_fixture 50.0000, V_fixture 3.3: 20-80 % time 1.76ns typ, 3.22ns min, 900ps max; typ from 3.3 V to 1.7 V
|   falling waveform, R_fixture 50.0000, V_fixture 0: 20-80 % time 188ps typ, 364ps min, 145ps max; typ from 1.7 V to 0.002 V
[POWER_clamp]
|   voltage   I(typ)   I(min)   I(max)
-3.3V     77.66mA    57.5mA     94.63mA
-1.433V   21.11mA    16.69mA    25.79mA
-1.267V   16.76mA    13.13mA    20.62mA
-1.233V   15.94mA    12.43mA    19.6mA
-1.133V   13.55mA    10.4mA     16.57mA
-900mV    8.283mA    6.107mA    9.917mA
-800mV    6.297mA    4.554mA    7.585mA
-600mV    3.11mA     2.075mA    3.521mA
-500mV    1.823mA    1.185mA    1.894mA
-400mV    839.2uA    515.2uA    752.3uA
-300mV    250.4uA    130.7uA    193.1uA
0V        111.9nA    205nA      235.8nA
[Pulldown]
|   voltage   I(typ)   I(min)   I(max)
-3.3V     -1.459mA   -754.7uA   -3.261mA
-1.6V     -11.8mA    -5.515mA   -17.49mA
-700mV    -12.08mA   -7.934mA   -15.27mA
-400mV    -8.848mA   -5.918mA   -11.47mA
900mV     19.04mA    12.79mA    25.2mA
1.8V      32.51mA    21.67mA    44.31mA
2.3V      34.42mA    22.87mA    47.99mA
3.7V      35.05mA    22.15mA    50.09mA
4.1V      30.14mA    17.85mA    46.67mA
5.1V      12.56mA    4.445mA    25.33mA
5.7V      6.052mA    1.803mA    13.74mA
6.6V      1.68mA     1.035mA    4.433mA
[Pullup]
|   voltage   I(typ)   I(min)   I(max)
-3.3V     5.462mA    1.756mA    9.935mA
-1.7V     13.59mA    6.784mA    20.11mA
-600mV    10.64mA    7.053mA    14.67mA
1.3V      -28.03mA   -17.84mA   -37.53mA
2.2V      -43.74mA   -25.48mA   -59.43mA
3V        -51.69mA   -27.98mA   -73.8mA
3.8V      -54.49mA   -27.05mA   -80.92mA
4.3V      -47.43mA   -19.28mA   -75.18mA
5.2V      -25.52mA   -3.988mA   -53.13mA
5.8V      -10.51mA   -1.411mA   -32.89mA
6.3V      -4.864mA   -936.6uA   -17.2mA
6.6V      -2.666mA   -790.5uA   -12mA
[GND_clamp]
|   voltage   I(typ)   I(min)   I(max)
-3.3V     -92.32mA   -69.2mA    -111.6mA
-1.3V     -20.2mA    -17.2mA    -24.8mA
-1.233V   -18.02mA   -15.48mA   -22.36mA
-1.167V   -15.93mA   -13.78mA   -19.93mA
-1.1V     -13.91mA   -12.1mA    -17.52mA
-1.033V   -12.02mA   -10.47mA   -15.18mA
-900mV    -8.388mA   -7.328mA   -10.72mA
-700mV    -3.928mA   -3.299mA   -5.573mA
-500mV    -1.013mA   -800.5uA   -1.602mA
-366.7mV  -181uA     -176.6uA   -310uA
-166.7mV  -5.4uA     -6.443uA   -7.331uA
3.233V    80.14nA    2.436uA    206.1nA
[Ramp]
| variable   typ   min   max
dV/dt_f  0.9685534/1.779388n   0.7196249/3.513988n   1.190375/0.9110003n
dV/dt_r   1.022261/1.127004n   0.733244/2.46074n   1.233227/0.6278675n
R_load = 50
[Rising Waveform]
R_fixture = 50.0000
V_fixture = 3.3
V_fixture_min = 3.14
V_fixture_max = 3.47
|   time   V(typ)   V(min)   V(max)
0s        1.712V     2.019V     1.505V
128ps     1.711V     2.019V     1.632V
248ps     1.72V      2.019V     2.806V
328ps     1.791V     2.019V     3.053V
504ps     2.762V     2.019V     3.343V
584ps     2.941V     2.018V     3.397V
920ps     3.24V      2.108V     3.462V
1.208ns   3.28V      2.796V     3.467V
1.496ns   3.291V     3.033V     3.468V
3.56ns    3.299V     3.134V     3.47V
[Rising Waveform]
R_fixture = 50.0000
V_fixture = 0
V_fixture_min = 0
V_fixture_max = 0
|   time   V(typ)   V(min)   V(max)
0s        45.63uV    24.22uV    74.31uV
224ps     -3.115mV   -185.7uV   54.38mV
664ps     838.9uV    -2.224mV   575.3mV
1.144ns   177.6mV    -1.22mV    1.626V
1.856ns   598.8mV    34.61uV    1.979V
2.568ns   1.348V     2.219mV    2.027V
3.528ns   1.616V     147.9mV    2.038V
6.224ns   1.685V     914.4mV    2.045V
7.336ns   1.689V     1.086V     2.046V
13.78ns   1.696V     1.197V     2.048V
[Falling Waveform]
R_fixture = 50.0000
V_fixture = 3.3
V_fixture_min = 3.14
V_fixture_max = 3.47
|   time   V(typ)   V(min)   V(max)
0s        3.3V       3.14V      3.47V
40ps      3.305V     3.142V     3.325V
608ps     3.143V     3.145V     2.736V
976ps     3.006V     3.14V      2.08V
1.344ns   2.82V      3.12V      1.803V
1.736ns   2.544V     3.042V     1.643V
2.2ns     2.23V      2.988V     1.566V
3.688ns   1.801V     2.734V     1.511V
6.216ns   1.703V     2.187V     1.505V
7.936ns   1.699V     2.025V     1.504V
[Falling Waveform]
R_fixture = 50.0000
V_fixture = 0
V_fixture_min = 0
V_fixture_max = 0
|   time   V(typ)   V(min)   V(max)
0s        1.695V     1.203V     2.046V
88ps      1.692V     1.204V     2.004V
144ps     1.679V     1.205V     1.839V
272ps     1.518V     1.199V     564.4mV
344ps     1.192V     1.19V      345.9mV
440ps     508mV      1.164V     170.6mV
536ps     288.4mV    1.104V     60.24mV
920ps     31.78mV    328.7mV    4.501mV
1.2ns     8.467mV    107.6mV    2.416mV
2.648ns   1.708mV    6.347mV    318.4uV
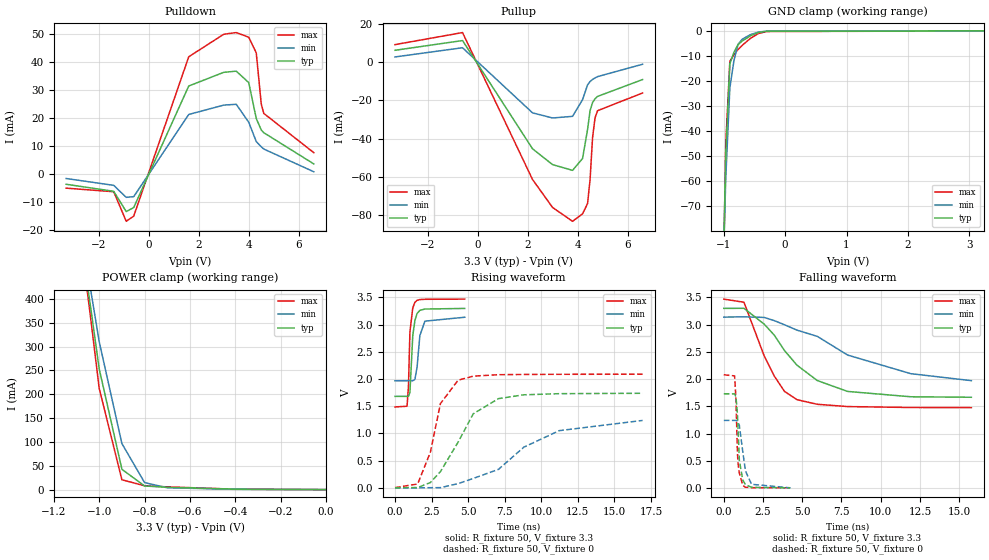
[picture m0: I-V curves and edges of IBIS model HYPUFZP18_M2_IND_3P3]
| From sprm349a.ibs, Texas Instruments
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|   Model Cell HYPUFZP18_M2_IND_3P3
[Model]   HYPUFZP18_M2_IND_3P3
Model_type   I/O
Polarity   Non-Inverting
Enable   Active-Low
Vinl =  0.8V
Vinh =  2V
Cref =  15.0000pF
Rref =  100.0000M
Vref =  0V
Vmeas =  1.65
C_comp   1.500963p   1.465915p   1.537982p
[Model Spec]
Vinl   0.8V   0.8V   0.8V
Vinh   2V   2V   2V
[Temperature Range]   25   125   -40
[Voltage Range]   3.3   3.14   3.47
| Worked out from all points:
|   slope of the pulldown table from 0 to 0.495 V, typ, clamps not added: 44 ohm
|   slope of the pullup table from 0 to 0.495 V, typ, clamps not added: 42.8 ohm
|   GND clamp passes 1 mA (typ) near -0.48 V on its own axis
|   POWER clamp passes 1 mA (typ) near -0.41 V on its own axis
|   rising waveform, R_fixture 50, V_fixture 3.3: 20-80 % time 216ps typ, 299ps min, 173ps max; typ from 1.68 V to 3.3 V
|   rising waveform, R_fixture 50, V_fixture 0: 20-80 % time 2.17ns typ, 4.41ns min, 1.2ns max; typ from 0.003 V to 1.74 V
|   falling waveform, R_fixture 50, V_fixture 3.3: 20-80 % time 3.15ns typ, 5.72ns min, 1.77ns max; typ from 3.3 V to 1.67 V
|   falling waveform, R_fixture 50, V_fixture 0: 20-80 % time 192ps typ, 363ps min, 151ps max; typ from 1.73 V to 0.004 V
[POWER_clamp]
|   voltage   I(typ)   I(min)   I(max)
-3.3V     9.961A     8.483A     11.27A
-1.067V   478.9mA    500.9mA    470.4mA
-1.033V   365.9mA    405.4mA    341.3mA
-1V       253mA      310mA      212.1mA
-900mV    42.61mA    96.48mA    20.62mA
-800mV    7.588mA    14.65mA    8.039mA
-700mV    4.837mA    3.903mA    5.737mA
-400mV    906.7uA    555.7uA    845.1uA
-11.55fV  111.6nA    200.5nA    235nA
[Pulldown]
|   voltage   I(typ)   I(min)   I(max)
-3.3V     -3.547mA   -1.486mA   -4.928mA
-1.4V     -6.057mA   -3.93mA    -6.213mA
-900mV    -13.28mA   -8.212mA   -16.76mA
-600mV    -11.85mA   -7.958mA   -14.91mA
1.6V      31.52mA    21.37mA    41.96mA
3V        36.41mA    24.71mA    50mA
3.5V      36.83mA    25mA       50.6mA
4V        32.72mA    18.58mA    48.93mA
4.3V      19.94mA    11.7mA     43.35mA
4.5V      15.84mA    9.852mA    25.09mA
4.6V      14.87mA    9.033mA    21.76mA
6.6V      3.718mA    925.6uA    7.735mA
[Pullup]
|   voltage   I(typ)   I(min)   I(max)
-3.3V     6.065mA    2.586mA    9.02mA
-600mV    11.14mA    7.39mA     15.31mA
2.2V      -45.34mA   -26.58mA   -61.36mA
3V        -53.58mA   -29.26mA   -75.93mA
3.8V      -56.58mA   -28.4mA    -83.16mA
4.2V      -50.4mA    -19.68mA   -79.27mA
4.4V      -35.28mA   -11.98mA   -73.9mA
4.5V      -25.43mA   -10.23mA   -61.47mA
4.6V      -21.24mA   -9.135mA   -39.55mA
4.7V      -19.23mA   -8.33mA    -29.16mA
4.8V      -18mA      -7.666mA   -25.45mA
6.6V      -9.206mA   -1.224mA   -16.21mA
[GND_clamp]
|   voltage   I(typ)   I(min)   I(max)
-3.3V     -13.48A    -11.37A    -15.19A
-1.033V   -124.2mA   -117.5mA   -138.8mA
-966.7mV  -49.48mA   -59.12mA   -45.28mA
-900mV    -13.25mA   -22.79mA   -12.17mA
-833.3mV  -8.552mA   -11.89mA   -9.57mA
-766.7mV  -5.5mA     -5.419mA   -7.456mA
-700mV    -4.097mA   -3.375mA   -5.833mA
-566.7mV  -2.008mA   -1.526mA   -3.032mA
-433.3mV  -632.5uA   -486.5uA   -1.039mA
-300mV    -165.9uA   -110.1uA   -270.3uA
3.233V    -8.733uA   9.998uA    -45.21uA
[Ramp]
| variable   typ   min   max
dV/dt_f   0.987955/3.175345n   0.7560235/6.596426n   1.204886/1.771364n
dV/dt_r   1.046462/2.184622n   0.7633212/4.598626n   1.254058/1.207037n
R_load = 50
[Rising Waveform]
R_fixture = 50
V_fixture = 3.3
V_fixture_min = 3.14
V_fixture_max = 3.47
|   time   V(typ)   V(min)   V(max)
0s        1.682V     1.969V     1.488V
824ps     1.682V     1.97V      1.501V
920ps     1.683V     1.97V      1.868V
1.02ns    1.753V     1.97V      2.865V
1.216ns   2.803V     1.97V      3.309V
1.36ns    3.075V     1.993V     3.41V
1.508ns   3.206V     2.215V     3.448V
1.7ns     3.263V     2.799V     3.462V
2.044ns   3.288V     3.065V     3.467V
4.768ns   3.299V     3.137V     3.47V
[Rising Waveform]
R_fixture = 50
V_fixture = 0
V_fixture_min = 0
V_fixture_max = 0
|   time   V(typ)   V(min)   V(max)
0s        3.148mV    1.894mV    4.433mV
1.552ns   5.807mV    357.6uV    71.65mV
2.416ns   97.49mV    3.247mV    652.5mV
3.108ns   299.5mV    3.999mV    1.55V
4.316ns   840.6mV    78.16mV    1.98V
5.352ns   1.362V     173.5mV    2.054V
7.08ns    1.641V     341.3mV    2.081V
8.808ns   1.711V     748mV      2.085V
11.23ns   1.732V     1.052V     2.088V
16.93ns   1.739V     1.24V      2.09V
[Falling Waveform]
R_fixture = 50
V_fixture = 3.3
V_fixture_min = 3.14
V_fixture_max = 3.47
|   time   V(typ)   V(min)   V(max)
0s        3.3V       3.14V      3.47V
1.284ns   3.302V     3.145V     3.413V
2.576ns   3.01V      3.134V     2.427V
3.22ns    2.808V     3.075V     2.056V
3.864ns   2.527V     3V         1.777V
4.668ns   2.256V     2.9V       1.623V
5.96ns    1.975V     2.786V     1.539V
7.892ns   1.775V     2.443V     1.497V
11.92ns   1.677V     2.101V     1.48V
15.78ns   1.668V     1.973V     1.478V
[Falling Waveform]
R_fixture = 50
V_fixture = 0
V_fixture_min = 0
V_fixture_max = 0
|   time   V(typ)   V(min)   V(max)
0s        1.732V     1.243V     2.081V
688ps     1.731V     1.243V     2.06V
776ps     1.674V     1.243V     1.644V
864ps     1.378V     1.228V     687.9mV
904ps     1.131V     1.214V     464mV
992ps     506.3mV    1.151V     271.7mV
1.208ns   150.4mV    672.1mV    51.58mV
1.38ns    63.51mV    314.2mV    16.12mV
1.772ns   14.58mV    69.66mV    8.052mV
4.244ns   4.403mV    5.039mV    4.691mV
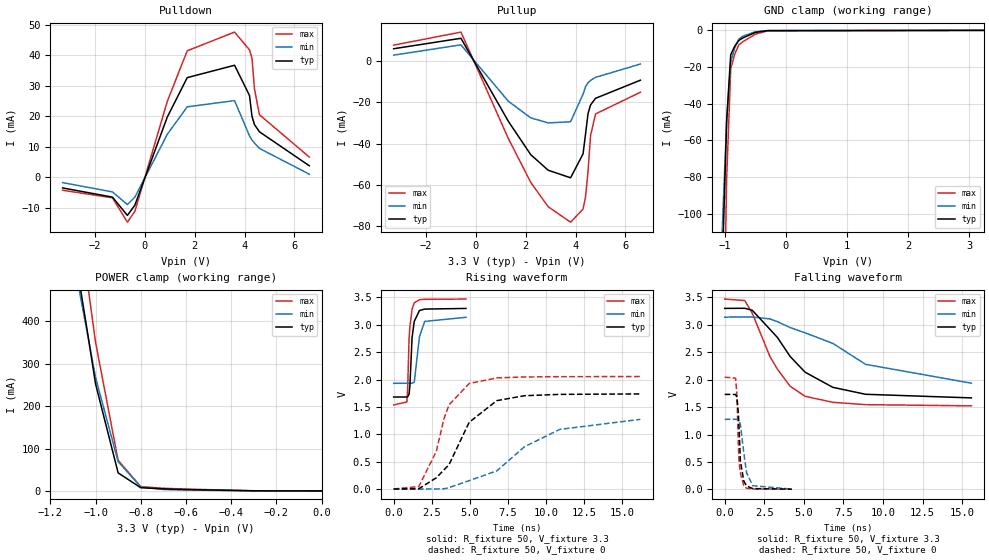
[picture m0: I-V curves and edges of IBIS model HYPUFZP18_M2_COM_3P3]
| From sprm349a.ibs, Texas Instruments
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|   Model Cell HYPUFZP18_M2_COM_3P3
[Model]   HYPUFZP18_M2_COM_3P3
Model_type   I/O
Polarity   Non-Inverting
Enable   Active-Low
Vinl =  0.8V
Vinh =  2V
Cref =  15.0000pF
Rref =  100.0000M
Vref =  0V
Vmeas =  1.65
C_comp   1.500963p   1.465463p   1.538477p
[Model Spec]
Vinl   0.8V   0.8V   0.8V
Vinh   2V   2V   2V
[Temperature Range]   25   105   0
[Voltage Range]   3.3   3.14   3.47
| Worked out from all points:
|   slope of the pulldown table from 0 to 0.495 V, typ, clamps not added: 44 ohm
|   slope of the pullup table from 0 to 0.495 V, typ, clamps not added: 42.8 ohm
|   GND clamp passes 1 mA (typ) near -0.48 V on its own axis
|   POWER clamp passes 1 mA (typ) near -0.41 V on its own axis
|   rising waveform, R_fixture 50, V_fixture 3.3: 20-80 % time 217ps typ, 294ps min, 178ps max; typ from 1.68 V to 3.3 V
|   rising waveform, R_fixture 50, V_fixture 0: 20-80 % time 2.16ns typ, 4.18ns min, 1.48ns max; typ from 0.003 V to 1.74 V
|   falling waveform, R_fixture 50, V_fixture 3.3: 20-80 % time 3.15ns typ, 5.68ns min, 2.07ns max; typ from 3.3 V to 1.67 V
|   falling waveform, R_fixture 50, V_fixture 0: 20-80 % time 192ps typ, 352ps min, 158ps max; typ from 1.73 V to 0.004 V
[POWER_clamp]
|   voltage   I(typ)   I(min)   I(max)
-3.3V     9.961A     8.611A     10.94A
-1.067V   478.9mA    459.3mA    610.8mA
-1.033V   365.9mA    363.6mA    481.1mA
-1V       253mA      268mA      351.4mA
-900mV    42.61mA    69.09mA    72.29mA
-800mV    7.588mA    9.637mA    10.15mA
-700mV    4.837mA    3.413mA    6.304mA
-600mV    3.264mA    2.054mA    4.281mA
-300mV    294.4uA    124uA      421.6uA
-11.55fV  111.6nA    122nA      530.8nA
[Pulldown]
|   voltage   I(typ)   I(min)   I(max)
-3.3V     -3.547mA   -1.801mA   -4.304mA
-1.3V     -6.559mA   -4.849mA   -6.791mA
-700mV    -12.57mA   -9.011mA   -14.79mA
-400mV    -9.185mA   -6.565mA   -11.22mA
900mV     19.72mA    14.04mA    24.85mA
1.7V      32.66mA    23.07mA    41.47mA
3.6V      36.72mA    25.12mA    47.61mA
4.2V      26.77mA    13.52mA    41.76mA
4.3V      19.94mA    12.18mA    38.97mA
4.4V      17.22mA    11.16mA    28.83mA
4.6V      14.87mA    9.427mA    20.47mA
6.6V      3.719mA    952.1uA    6.578mA
[Pullup]
|   voltage   I(typ)   I(min)   I(max)
-3.3V     6.064mA    2.952mA    7.802mA
-600mV    11.13mA    7.955mA    14.14mA
1.3V      -29.11mA   -19.4mA    -37.44mA
2.2V      -45.33mA   -27.49mA   -58.76mA
2.9V      -52.89mA   -29.93mA   -70.6mA
3.8V      -56.57mA   -29.4mA    -78.11mA
4.3V      -44.95mA   -15.96mA   -71.74mA
4.4V      -35.27mA   -12.34mA   -65.8mA
4.5V      -25.43mA   -10.47mA   -53.41mA
4.6V      -21.24mA   -9.331mA   -36.24mA
4.8V      -18mA      -7.836mA   -25.59mA
6.6V      -9.204mA   -1.361mA   -15.06mA
[GND_clamp]
|   voltage   I(typ)   I(min)   I(max)
-3.3V     -13.48A    -11.6A     -14.64A
-1.1V     -237.5mA   -179.6mA   -391mA
-1.033V   -124.2mA   -103.9mA   -204.6mA
-966.7mV  -49.48mA   -49.77mA   -81.21mA
-900mV    -13.25mA   -17.18mA   -20.95mA
-833.3mV  -8.552mA   -9.42mA    -12.82mA
-766.7mV  -5.5mA     -4.745mA   -7.884mA
-700mV    -4.097mA   -3.158mA   -6.131mA
-500mV    -1.138mA   -790.5uA   -2.124mA
-300mV    -165.9uA   -102.1uA   -289.6uA
3.233V    -8.734uA   9.394uA    -38.37uA
[Ramp]
| variable   typ   min   max
dV/dt_f   0.988002/3.175086n   0.7791854/6.518141n   1.17789/2.077727n
dV/dt_r   1.046458/2.184507n   0.7845616/4.355689n   1.234891/1.486891n
R_load = 50
[Rising Waveform]
R_fixture = 50
V_fixture = 3.3
V_fixture_min = 3.14
V_fixture_max = 3.47
|   time   V(typ)   V(min)   V(max)
0s        1.682V     1.932V     1.536V
868ps     1.682V     1.933V     1.593V
916ps     1.683V     1.933V     1.806V
1.012ns   1.738V     1.933V     2.754V
1.064ns   1.872V     1.933V     2.962V
1.208ns   2.766V     1.933V     3.286V
1.352ns   3.062V     1.953V     3.401V
1.692ns   3.261V     2.781V     3.459V
2.032ns   3.287V     3.062V     3.466V
4.744ns   3.299V     3.137V     3.47V
[Rising Waveform]
R_fixture = 50
V_fixture = 0
V_fixture_min = 0
V_fixture_max = 0
|   time   V(typ)   V(min)   V(max)
0s        3.147mV    1.931mV    3.849mV
1.648ns   6.46mV     -310.1uV   47.36mV
2.804ns   208.4mV    3.696mV    692.3mV
3.3ns     352.2mV    6.006mV    1.285V
3.632ns   445.9mV    27.85mV    1.538V
4.956ns   1.221V     155.4mV    1.929V
6.772ns   1.616V     334.4mV    2.031V
8.592ns   1.706V     775.7mV    2.048V
10.9ns    1.73V      1.091V     2.053V
16.19ns   1.738V     1.274V     2.056V
[Falling Waveform]
R_fixture = 50
V_fixture = 3.3
V_fixture_min = 3.14
V_fixture_max = 3.47
|   time   V(typ)   V(min)   V(max)
0s        3.3V       3.14V      3.47V
1.268ns   3.302V     3.144V     3.443V
1.744ns   3.265V     3.143V     3.211V
2.856ns   2.918V     3.108V     2.422V
3.332ns   2.769V     3.058V     2.19V
4.128ns   2.425V     2.951V     1.881V
5.08ns    2.136V     2.854V     1.697V
6.828ns   1.861V     2.662V     1.588V
8.896ns   1.734V     2.28V      1.545V
15.58ns   1.668V     1.936V     1.523V
[Falling Waveform]
R_fixture = 50
V_fixture = 0
V_fixture_min = 0
V_fixture_max = 0
|   time   V(typ)   V(min)   V(max)
0s        1.732V     1.277V     2.046V
688ps     1.731V     1.277V     2.028V
776ps     1.675V     1.278V     1.701V
864ps     1.382V     1.262V     792.6mV
908ps     1.107V     1.245V     494.1mV
992ps     509.8mV    1.18V      296.1mV
1.208ns   151mV      663.3mV    63.76mV
1.384ns   62.6mV     300.9mV    18.86mV
1.772ns   14.62mV    66.99mV    8.125mV
4.248ns   4.402mV    5.077mV    4.209mV
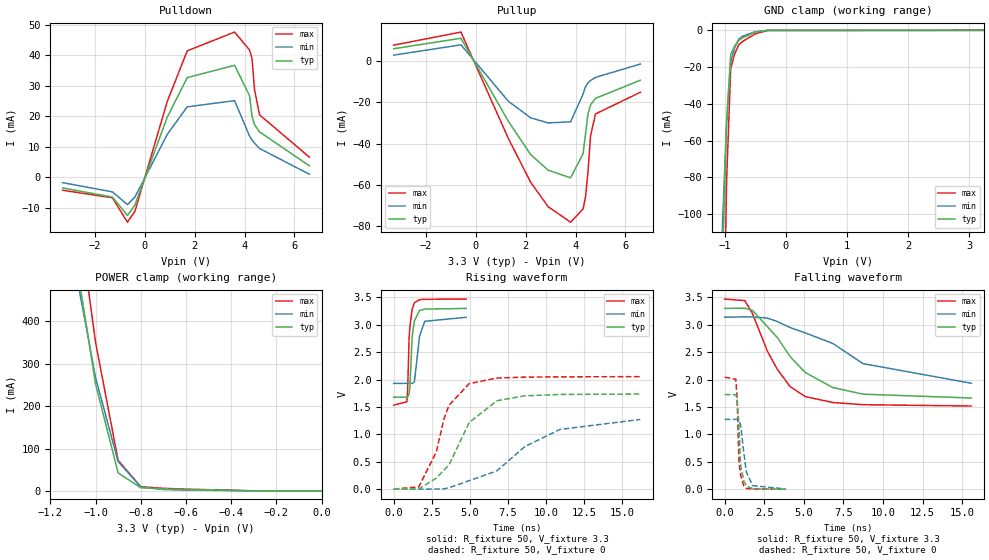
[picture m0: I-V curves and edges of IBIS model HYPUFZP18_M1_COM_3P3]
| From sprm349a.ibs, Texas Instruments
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|   Model Cell HYPUFZP18_M1_COM_3P3
[Model]   HYPUFZP18_M1_COM_3P3
Model_type   I/O
Polarity   Non-Inverting
Enable   Active-Low
Vinl =  0.8V
Vinh =  2V
Cref =  15.0000pF
Rref =  100.0000M
Vref =  0V
Vmeas =  1.65
C_comp   1.500963p   1.465463p   1.538477p
[Model Spec]
Vinl   0.8V   0.8V   0.8V
Vinh   2V   2V   2V
[Temperature Range]   25   105   0
[Voltage Range]   3.3   3.14   3.47
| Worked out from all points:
|   slope of the pulldown table from 0 to 0.495 V, typ, clamps not added: 44 ohm
|   slope of the pullup table from 0 to 0.495 V, typ, clamps not added: 42.8 ohm
|   GND clamp passes 1 mA (typ) near -0.50 V on its own axis
|   POWER clamp passes 1 mA (typ) near -0.41 V on its own axis
|   rising waveform, R_fixture 50, V_fixture 3.3: 20-80 % time 218ps typ, 296ps min, 179ps max; typ from 1.68 V to 3.3 V
|   rising waveform, R_fixture 50, V_fixture 0: 20-80 % time 2.16ns typ, 4.18ns min, 1.48ns max; typ from 0 V to 1.74 V
|   falling waveform, R_fixture 50, V_fixture 3.3: 20-80 % time 3.14ns typ, 5.68ns min, 2.06ns max; typ from 3.3 V to 1.66 V
|   falling waveform, R_fixture 50, V_fixture 0: 20-80 % time 192ps typ, 352ps min, 155ps max; typ from 1.73 V to 0.001 V
[POWER_clamp]
|   voltage   I(typ)   I(min)   I(max)
-3.3V     9.961A     8.611A     10.94A
-1.067V   478.8mA    459.2mA    610.8mA
-1.033V   365.9mA    363.6mA    481.1mA
-1V       253mA      268mA      351.3mA
-900mV    42.53mA    69.07mA    72.18mA
-800mV    7.492mA    9.597mA    10.03mA
-700mV    4.749mA    3.362mA    6.191mA
-600mV    3.186mA    2.005mA    4.182mA
-300mV    252.3uA    97.69uA    368uA
-11.55fV  112.1nA    122.2nA    532.1nA
[Pulldown]
|   voltage   I(typ)   I(min)   I(max)
-3.3V     -3.547mA   -1.801mA   -4.304mA
-1.3V     -6.559mA   -4.849mA   -6.791mA
-700mV    -12.57mA   -9.011mA   -14.79mA
-400mV    -9.185mA   -6.565mA   -11.22mA
900mV     19.72mA    14.04mA    24.85mA
1.7V      32.66mA    23.07mA    41.47mA
3.6V      36.72mA    25.12mA    47.62mA
4.2V      26.77mA    13.52mA    41.76mA
4.3V      19.94mA    12.18mA    38.97mA
4.4V      17.22mA    11.16mA    28.83mA
4.6V      14.87mA    9.427mA    20.47mA
6.6V      3.719mA    952.1uA    6.578mA
[Pullup]
|   voltage   I(typ)   I(min)   I(max)
-3.3V     6.064mA    2.952mA    7.802mA
-600mV    11.14mA    7.955mA    14.14mA
1.3V      -29.11mA   -19.4mA    -37.44mA
2.2V      -45.33mA   -27.49mA   -58.77mA
2.9V      -52.89mA   -29.93mA   -70.6mA
3.8V      -56.57mA   -29.4mA    -78.11mA
4.3V      -44.95mA   -15.96mA   -71.74mA
4.4V      -35.27mA   -12.34mA   -65.8mA
4.5V      -25.43mA   -10.47mA   -53.41mA
4.6V      -21.24mA   -9.331mA   -36.23mA
4.8V      -18mA      -7.836mA   -25.59mA
6.6V      -9.204mA   -1.361mA   -15.06mA
[GND_clamp]
|   voltage   I(typ)   I(min)   I(max)
-3.3V     -13.48A    -11.6A     -14.64A
-1.1V     -237.4mA   -179.6mA   -390.9mA
-1.033V   -124.1mA   -103.9mA   -204.4mA
-966.7mV  -49.36mA   -49.7mA    -81.05mA
-900mV    -13.13mA   -17.12mA   -20.78mA
-833.3mV  -8.423mA   -9.354mA   -12.64mA
-766.7mV  -5.368mA   -4.678mA   -7.699mA
-700mV    -3.962mA   -3.09mA    -5.944mA
-500mV    -1.002mA   -719.9uA   -1.935mA
-300mV    -30.1uA    -31.66uA   -100.6uA
3.233V    79.91nA    1.447uA    399.7nA
[Ramp]
| variable   typ   min   max
dV/dt_f  0.9905563/3.164829n   0.780636/6.511354n   1.180878/2.069688n
dV/dt_r   1.047448/2.18267n   0.7847808/4.356655n   1.23643/1.485249n
R_load = 50
[Rising Waveform]
R_fixture = 50
V_fixture = 3.3
V_fixture_min = 3.14
V_fixture_max = 3.47
|   time   V(typ)   V(min)   V(max)
0s        1.677V     1.93V      1.531V
872ps     1.678V     1.93V      1.596V
920ps     1.679V     1.93V      1.83V
1.016ns   1.74V      1.93V      2.777V
1.068ns   1.885V     1.93V      2.966V
1.212ns   2.778V     1.93V      3.286V
1.36ns    3.07V      1.955V     3.402V
1.7ns     3.262V     2.794V     3.459V
2.04ns    3.287V     3.064V     3.466V
4.76ns    3.299V     3.137V     3.47V
[Rising Waveform]
R_fixture = 50
V_fixture = 0
V_fixture_min = 0
V_fixture_max = 0
|   time   V(typ)   V(min)   V(max)
0s        38.06uV    21.19uV    59.46uV
1.648ns   -202.9uV   -2.525mV   38.21mV
2.804ns   201.9mV    200.1uV    681.5mV
3.3ns     345.9mV    2.483mV    1.277V
3.632ns   439.4mV    24.39mV    1.531V
4.956ns   1.215V     152mV      1.925V
6.772ns   1.612V     331.1mV    2.027V
8.592ns   1.703V     772mV      2.044V
10.9ns    1.727V     1.088V     2.049V
16.19ns   1.735V     1.271V     2.053V
[Falling Waveform]
R_fixture = 50
V_fixture = 3.3
V_fixture_min = 3.14
V_fixture_max = 3.47
|   time   V(typ)   V(min)   V(max)
0s        3.3V       3.14V      3.47V
1.268ns   3.302V     3.144V     3.442V
1.744ns   3.265V     3.143V     3.21V
2.7ns     2.965V     3.123V     2.516V
3.336ns   2.764V     3.058V     2.182V
4.132ns   2.419V     2.95V      1.873V
5.084ns   2.13V      2.853V     1.69V
6.832ns   1.855V     2.659V     1.582V
8.74ns    1.734V     2.291V     1.542V
15.58ns   1.664V     1.933V     1.518V
[Falling Waveform]
R_fixture = 50
V_fixture = 0
V_fixture_min = 0
V_fixture_max = 0
|   time   V(typ)   V(min)   V(max)
0s        1.728V     1.274V     2.043V
704ps     1.724V     1.275V     2.006V
780ps     1.665V     1.275V     1.664V
900ps     1.159V     1.246V     520mV
976ps     590.2mV    1.194V     321.7mV
1.016ns   417.2mV    1.146V     242.9mV
1.212ns   141mV      648.8mV    52.89mV
1.372ns   59.18mV    310.4mV    12.88mV
1.764ns   9.253mV    65.21mV    2.77mV
3.848ns   916.3uV    3.167mV    169.2uV
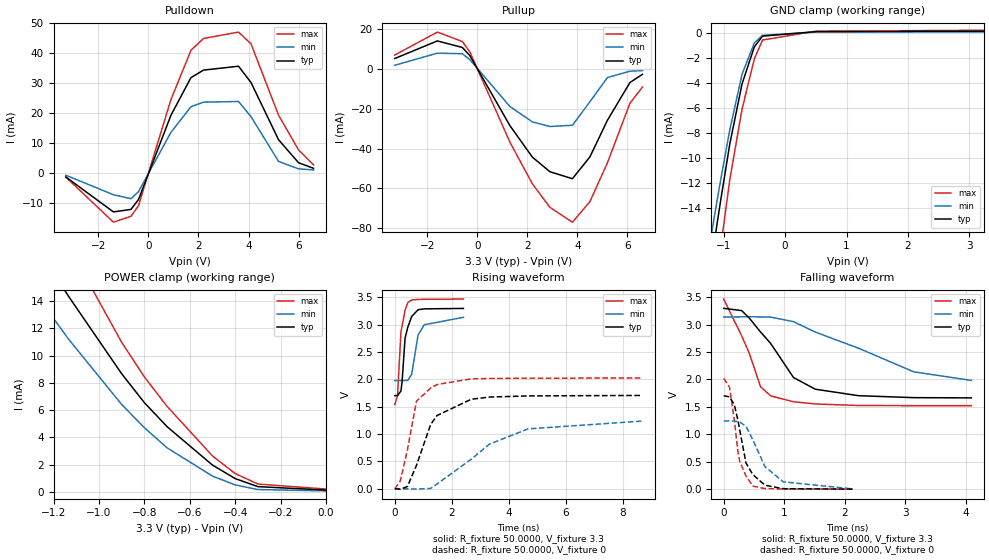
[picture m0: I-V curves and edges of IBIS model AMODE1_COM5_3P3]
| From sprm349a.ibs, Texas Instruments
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|AMODE4_IND5_3P3BUFFER IN NORMAL MODE WITH INDTEMP AT PLUS OR MINUS 5PERCENT
| VDDS
|COM AND INDE ARE TWO DIFFERENT TEMP MODES.
|COM IS 25,0,105(NOM,STRONG,WEAK)
|IND IS 25,-40,125(NOM,STRONG,WEAK)
|   Model Cell AMODE1_COM5_3P3
|AMODE1_COM5_3P3
[Model]   AMODE1_COM5_3P3
Model_type   I/O
Polarity   Non-Inverting
Enable   Active-Low
Vinl =  0.8V
Vinh =  2V
Cref =  15.0000pF
Rref =  100.0000M
Vref =  0V
Vmeas =  1.65
C_comp   1.700009p   1.656091p   1.748246p
[Model Spec]
Vinl   0.8V   0.8V   0.8V
Vinh   2V   2V   2V
[Temperature Range]   25   105   0
[Voltage Range]   3.3   3.14   3.47
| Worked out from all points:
|   slope of the pulldown table from 0 to 0.495 V, typ, clamps not added: 45.1 ohm
|   slope of the pullup table from 0 to 0.495 V, typ, clamps not added: 43.8 ohm
|   GND clamp passes 1 mA (typ) near -0.48 V on its own axis
|   POWER clamp passes 1 mA (typ) near -0.40 V on its own axis
|   rising waveform, R_fixture 50.0000, V_fixture 3.3: 20-80 % time 205ps typ, 277ps min, 168ps max; typ from 1.7 V to 3.29 V
|   rising waveform, R_fixture 50.0000, V_fixture 0: 20-80 % time 855ps typ, 2.22ns min, 474ps max; typ from 0 V to 1.71 V
|   falling waveform, R_fixture 50.0000, V_fixture 3.3: 20-80 % time 665ps typ, 1.52ns min, 413ps max; typ from 3.3 V to 1.67 V
|   falling waveform, R_fixture 50.0000, V_fixture 0: 20-80 % time 216ps typ, 386ps min, 168ps max; typ from 1.7 V to 0.002 V
[POWER_clamp]
|   voltage   I(typ)   I(min)   I(max)
-3.3V     82.99mA    64.42mA    101.3mA
-1.433V   22.51mA    18.29mA    27.82mA
-1.3V     18.69mA    15.05mA    23.32mA
-1.267V   17.8mA     14.26mA    22.25mA
-1.133V   14.33mA    11.19mA    18mA
-900mV    8.671mA    6.418mA    10.98mA
-800mV    6.552mA    4.711mA    8.44mA
-700mV    4.788mA    3.237mA    6.275mA
-500mV    1.971mA    1.163mA    2.643mA
-400mV    979.1uA    513.8uA    1.349mA
-300mV    386.8uA    172.4uA    577.5uA
0V        134.8uA    74.68uA    210uA
[Pulldown]
|   voltage   I(typ)   I(min)   I(max)
-3.3V     -1.415mA   -824.8uA   -1.453mA
-1.4V     -13.07mA   -7.326mA   -16.5mA
-700mV    -12.23mA   -8.654mA   -14.53mA
-400mV    -8.952mA   -6.328mA   -11.03mA
900mV     19.24mA    13.53mA    24.49mA
1.7V      31.8mA     22.09mA    40.92mA
2.2V      34.3mA     23.59mA    44.86mA
3.6V      35.6mA     23.82mA    47mA
4.1V      30.15mA    18.74mA    43.06mA
5.2V      11.04mA    3.801mA    19.25mA
6V        3.362mA    1.319mA    7.626mA
6.6V      1.49mA     943.6uA    2.619mA
[Pullup]
|   voltage   I(typ)   I(min)   I(max)
-3.3V     5.279mA    1.884mA    7.054mA
-1.6V     14.12mA    7.965mA    18.56mA
-600mV    10.83mA    7.699mA    13.81mA
-300mV    6.725mA    4.699mA    8.613mA
1.3V      -28.43mA   -18.84mA   -36.71mA
2.2V      -44.3mA    -26.6mA    -57.75mA
2.9V      -51.63mA   -28.89mA   -69.52mA
3.8V      -55.14mA   -28.28mA   -76.99mA
4.5V      -44.14mA   -16.42mA   -66.64mA
5.2V      -25.74mA   -4.29mA    -47.12mA
6.1V      -6.781mA   -1.092mA   -17.19mA
6.6V      -2.664mA   -796.3uA   -9.106mA
[GND_clamp]
|   voltage   I(typ)   I(min)   I(max)
-3.3V     -102mA     -80.37mA   -122.5mA
-1.3V     -22.07mA   -19.2mA    -27.08mA
-1.233V   -19.65mA   -17.2mA    -24.38mA
-1.167V   -17.32mA   -15.21mA   -21.74mA
-1.1V     -15.08mA   -13.25mA   -19.16mA
-1.033V   -12.97mA   -11.37mA   -16.65mA
-900mV    -8.917mA   -7.779mA   -11.78mA
-700mV    -4.089mA   -3.317mA   -6.11mA
-500mV    -1.121mA   -799.1uA   -2.085mA
-366.7mV  -263.6uA   -200.1uA   -576.6uA
500mV     96.1uA     57.82uA    132.1uA
3.233V    134.5uA    76.16uA    208.9uA
[Ramp]
| variable   typ   min   max
dV/dt_f  0.9847335/0.6632281n  0.7550054/1.687865n   1.171571/0.41391n
dV/dt_r   1.029496/0.8597399n  0.7642908/2.334073n   1.219066/0.4740991n
R_load = 50
[Rising Waveform]
R_fixture = 50.0000
V_fixture = 3.3
V_fixture_min = 3.14
V_fixture_max = 3.47
|   time   V(typ)   V(min)   V(max)
0s        1.701V     1.976V     1.539V
96ps      1.702V     1.977V     1.701V
216ps     1.787V     1.977V     2.871V
256ps     1.961V     1.977V     2.973V
360ps     2.751V     1.977V     3.262V
456ps     2.952V     1.98V      3.4V
592ps     3.146V     2.091V     3.448V
816ps     3.27V      2.809V     3.458V
1.032ns   3.286V     2.995V     3.461V
2.408ns   3.294V     3.132V     3.465V
[Rising Waveform]
R_fixture = 50.0000
V_fixture = 0
V_fixture_min = 0
V_fixture_max = 0
|   time   V(typ)   V(min)   V(max)
0s        45.62uV    22.84uV    73.92uV
192ps     -6.925mV   5.801uV    141.5mV
440ps     39.85mV    -1.404mV   705.1mV
760ps     428.5mV    -3.765mV   1.599V
1.256ns   1.172V     5.572mV    1.84V
1.48ns    1.338V     86.48mV    1.904V
2.68ns    1.635V     540.7mV    2.008V
3.32ns    1.675V     816mV      2.015V
4.672ns   1.696V     1.094V     2.02V
8.688ns   1.705V     1.237V     2.023V
[Falling Waveform]
R_fixture = 50.0000
V_fixture = 3.3
V_fixture_min = 3.14
V_fixture_max = 3.47
|   time   V(typ)   V(min)   V(max)
0s        3.297V     3.138V     3.466V
296ps     3.256V     3.142V     2.797V
424ps     3.117V     3.143V     2.474V
608ps     2.866V     3.141V     1.868V
776ps     2.656V     3.137V     1.701V
1.152ns   2.036V     3.055V     1.595V
1.512ns   1.823V     2.864V     1.554V
2.224ns   1.705V     2.571V     1.526V
3.136ns   1.669V     2.14V      1.523V
4.088ns   1.665V     1.983V     1.523V
[Falling Waveform]
R_fixture = 50.0000
V_fixture = 0
V_fixture_min = 0
V_fixture_max = 0
|   time   V(typ)   V(min)   V(max)
0s        1.704V     1.243V     2.021V
96ps      1.684V     1.245V     1.858V
176ps     1.538V     1.243V     1.256V
232ps     1.27V      1.234V     710.9mV
264ps     1.083V     1.226V     510.2mV
368ps     477.2mV    1.147V     240.8mV
480ps     268.2mV    902.8mV    57.32mV
680ps     73.08mV    413.2mV    10.79mV
984ps     9.355mV    134.4mV    4.46mV
2.128ns   2.376mV    6.358mV    1.067mV
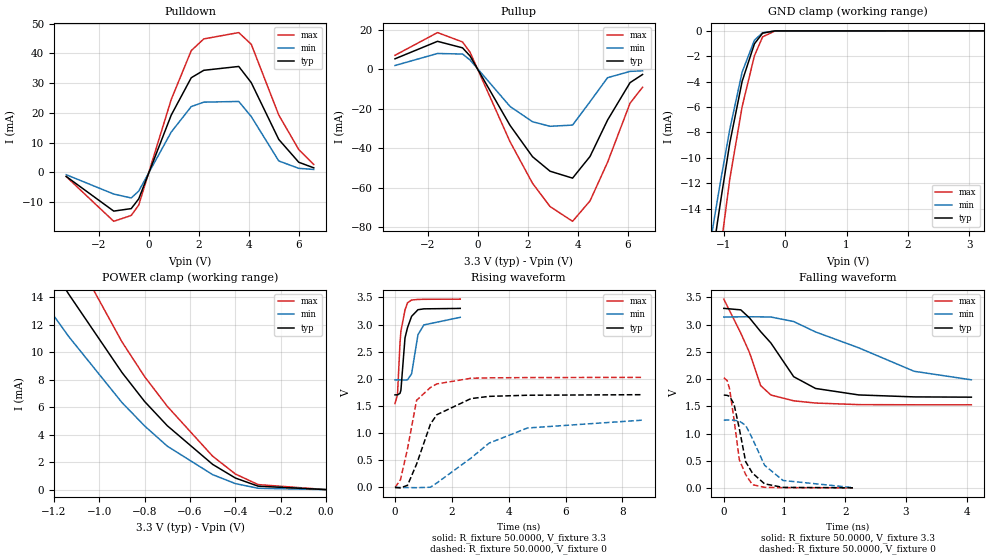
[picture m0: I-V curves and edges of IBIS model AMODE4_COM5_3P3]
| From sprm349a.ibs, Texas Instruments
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|   Model Cell AMODE4_COM5_3P3
|AMODE4_COM5_3P3
[Model]   AMODE4_COM5_3P3
Model_type   I/O
Polarity   Non-Inverting
Enable   Active-Low
Vinl =  0.8V
Vinh =  2V
Cref =  15.0000pF
Rref =  100.0000M
Vref =  0V
Vmeas =  1.65
C_comp   1.700009p   1.656091p   1.748246p
[Model Spec]
Vinl   0.8V   0.8V   0.8V
Vinh   2V   2V   2V
[Temperature Range]   25   105   0
[Voltage Range]   3.3   3.14   3.47
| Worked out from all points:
|   slope of the pulldown table from 0 to 0.495 V, typ, clamps not added: 45.1 ohm
|   slope of the pullup table from 0 to 0.495 V, typ, clamps not added: 43.8 ohm
|   GND clamp passes 1 mA (typ) near -0.50 V on its own axis
|   POWER clamp passes 1 mA (typ) near -0.42 V on its own axis
|   rising waveform, R_fixture 50.0000, V_fixture 3.3: 20-80 % time 204ps typ, 276ps min, 167ps max; typ from 1.71 V to 3.3 V
|   rising waveform, R_fixture 50.0000, V_fixture 0: 20-80 % time 851ps typ, 2.22ns min, 471ps max; typ from 0 V to 1.71 V
|   falling waveform, R_fixture 50.0000, V_fixture 3.3: 20-80 % time 667ps typ, 1.52ns min, 413ps max; typ from 3.3 V to 1.67 V
|   falling waveform, R_fixture 50.0000, V_fixture 0: 20-80 % time 218ps typ, 388ps min, 170ps max; typ from 1.71 V to 0.002 V
[POWER_clamp]
|   voltage   I(typ)   I(min)   I(max)
-3.3V     82.75mA    64.28mA    100.9mA
-1.433V   22.36mA    18.21mA    27.58mA
-1.4V     21.36mA    17.39mA    26.41mA
-1.267V   17.66mA    14.18mA    22.02mA
-1.133V   14.19mA    11.11mA    17.78mA
-900mV    8.53mA     6.341mA    10.76mA
-800mV    6.412mA    4.634mA    8.223mA
-700mV    4.649mA    3.161mA    6.059mA
-500mV    1.834mA    1.087mA    2.43mA
-400mV    842.6uA    438.3uA    1.136mA
-300mV    250.9uA    97.26uA    366uA
0V        112.1nA    124.8nA    531.9nA
[Pulldown]
|   voltage   I(typ)   I(min)   I(max)
-3.3V     -1.415mA   -824.8uA   -1.453mA
-1.4V     -13.07mA   -7.326mA   -16.5mA
-700mV    -12.23mA   -8.654mA   -14.53mA
-400mV    -8.953mA   -6.328mA   -11.04mA
900mV     19.24mA    13.53mA    24.49mA
1.7V      31.8mA     22.09mA    40.92mA
2.2V      34.3mA     23.59mA    44.86mA
3.6V      35.6mA     23.82mA    47mA
4.1V      30.15mA    18.74mA    43.06mA
5.2V      11.04mA    3.801mA    19.25mA
6V        3.362mA    1.319mA    7.625mA
6.6V      1.49mA     943.6uA    2.619mA
[Pullup]
|   voltage   I(typ)   I(min)   I(max)
-3.3V     5.279mA    1.884mA    7.054mA
-1.6V     14.12mA    7.965mA    18.56mA
-600mV    10.83mA    7.699mA    13.81mA
-300mV    6.725mA    4.699mA    8.614mA
1.3V      -28.42mA   -18.84mA   -36.71mA
2.2V      -44.3mA    -26.6mA    -57.75mA
2.9V      -51.63mA   -28.89mA   -69.52mA
3.8V      -55.14mA   -28.28mA   -76.99mA
4.5V      -44.14mA   -16.42mA   -66.64mA
5.2V      -25.74mA   -4.29mA    -47.12mA
6.1V      -6.781mA   -1.092mA   -17.19mA
6.6V      -2.664mA   -796.3uA   -9.106mA
[GND_clamp]
|   voltage   I(typ)   I(min)   I(max)
-3.3V     -102mA     -80.37mA   -122.5mA
-1.3V     -22.05mA   -19.19mA   -27.05mA
-1.233V   -19.61mA   -17.18mA   -24.34mA
-1.167V   -17.27mA   -15.2mA    -21.68mA
-1.1V     -15.01mA   -13.23mA   -19.07mA
-1.033V   -12.88mA   -11.34mA   -16.53mA
-900mV    -8.803mA   -7.73mA    -11.64mA
-700mV    -3.977mA   -3.248mA   -5.97mA
-500mV    -1.023mA   -736.2uA   -1.963mA
-366.7mV  -182.6uA   -147.5uA   -474.6uA
-166.7mV  -5.411uA   -5.006uA   -10.99uA
3.233V    80.32nA    1.448uA    401.5nA
[Ramp]
| variable   typ   min   max
dV/dt_f  0.9852716/0.6653436n  0.7553088/1.690732n   1.17234/0.4153024n
dV/dt_r   1.031409/0.8555301n  0.7657096/2.330367n   1.221644/0.4714948n
R_load = 50
[Rising Waveform]
R_fixture = 50.0000
V_fixture = 3.3
V_fixture_min = 3.14
V_fixture_max = 3.47
|   time   V(typ)   V(min)   V(max)
0s        1.706V     1.98V      1.545V
88ps      1.706V     1.981V     1.707V
176ps     1.734V     1.981V     2.661V
208ps     1.792V     1.981V     2.879V
352ps     2.756V     1.98V      3.27V
440ps     2.943V     1.982V     3.401V
584ps     3.152V     2.094V     3.453V
808ps     3.274V     2.813V     3.463V
1.016ns   3.29V      2.994V     3.466V
2.296ns   3.298V     3.134V     3.469V
[Rising Waveform]
R_fixture = 50.0000
V_fixture = 0
V_fixture_min = 0
V_fixture_max = 0
|   time   V(typ)   V(min)   V(max)
0s        45.56uV    22.78uV    73.77uV
192ps     -6.972mV   5.717uV    142mV
440ps     39.9mV     -1.409mV   710.9mV
760ps     431.3mV    -3.795mV   1.606V
1.248ns   1.169V     4.712mV    1.842V
1.472ns   1.34V      83.04mV    1.907V
2.672ns   1.637V     541mV      2.012V
3.312ns   1.678V     817.3mV    2.019V
4.664ns   1.699V     1.096V     2.024V
8.712ns   1.709V     1.24V      2.028V
[Falling Waveform]
R_fixture = 50.0000
V_fixture = 3.3
V_fixture_min = 3.14
V_fixture_max = 3.47
|   time   V(typ)   V(min)   V(max)
0s        3.3V       3.14V      3.47V
280ps     3.273V     3.145V     2.845V
424ps     3.124V     3.146V     2.487V
608ps     2.872V     3.144V     1.88V
776ps     2.664V     3.141V     1.708V
1.152ns   2.044V     3.058V     1.601V
1.512ns   1.828V     2.867V     1.56V
2.224ns   1.709V     2.575V     1.531V
3.136ns   1.673V     2.144V     1.528V
4.08ns    1.668V     1.987V     1.528V
[Falling Waveform]
R_fixture = 50.0000
V_fixture = 0
V_fixture_min = 0
V_fixture_max = 0
|   time   V(typ)   V(min)   V(max)
0s        1.707V     1.246V     2.025V
56ps      1.701V     1.247V     1.974V
96ps      1.682V     1.248V     1.817V
168ps     1.542V     1.245V     1.264V
256ps     1.089V     1.228V     517.6mV
360ps     482.6mV    1.15V      246.4mV
472ps     272.7mV    906.2mV    59.28mV
672ps     75.08mV    416.3mV    11mV
976ps     9.53mV     136.5mV    4.532mV
2.128ns   2.398mV    6.368mV    1.069mV
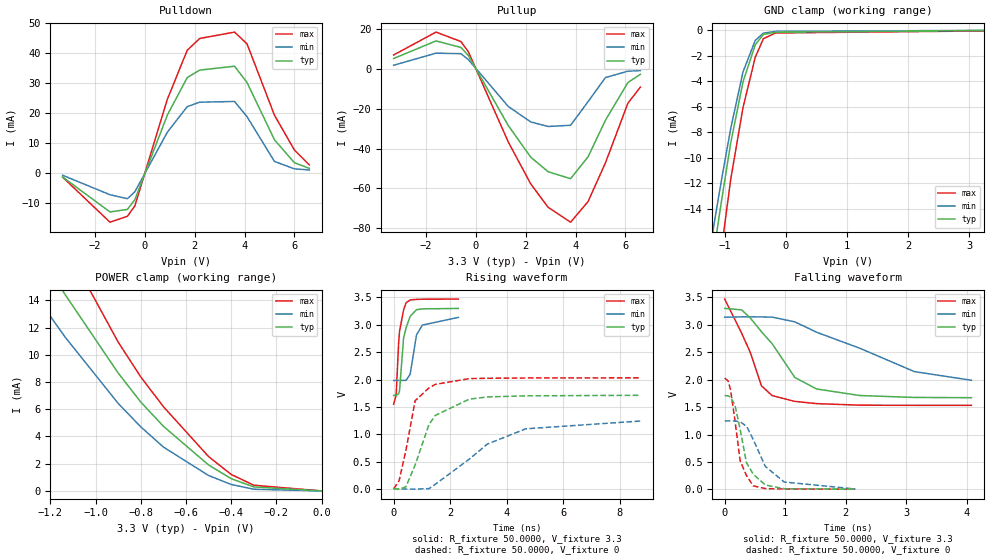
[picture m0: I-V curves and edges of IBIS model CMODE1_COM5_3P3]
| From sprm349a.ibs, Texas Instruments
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|CMODE4_IND5_3P3BUFFER OPERATING IN NORMAL MODE WITH IND TEMP AT PLUS OR MIN
|US 5PERCENT VDDS
|COM AND INDE ARE TWO DIFFERENT TEMP MODES.
|COM IS 25,0,105(NOM,STRONG,WEAK)
|IND IS 25,-40,125(NOM,STRONG,WEAK)
|   Model Cell CMODE1_COM5_3P3
|CMODE1_COM5_3P3
[Model]   CMODE1_COM5_3P3
Model_type   I/O
Polarity   Non-Inverting
Enable   Active-Low
Vinl =  0.8V
Vinh =  2V
Cref =  15.0000pF
Rref =  100.0000M
Vref =  0V
Vmeas =  1.65
C_comp   1.705749p   1.661847p   1.750916p
[Model Spec]
Vinl   0.8V   0.8V   0.8V
Vinh   2V   2V   2V
[Temperature Range]   25   105   0
[Voltage Range]   3.3   3.14   3.47
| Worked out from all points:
|   slope of the pulldown table from 0 to 0.495 V, typ, clamps not added: 45.1 ohm
|   slope of the pullup table from 0 to 0.495 V, typ, clamps not added: 43.8 ohm
|   GND clamp passes 1 mA (typ) near -0.48 V on its own axis
|   POWER clamp passes 1 mA (typ) near -0.41 V on its own axis
|   rising waveform, R_fixture 50.0000, V_fixture 3.3: 20-80 % time 204ps typ, 276ps min, 167ps max; typ from 1.71 V to 3.3 V
|   rising waveform, R_fixture 50.0000, V_fixture 0: 20-80 % time 849ps typ, 2.22ns min, 471ps max; typ from 0.003 V to 1.71 V
|   falling waveform, R_fixture 50.0000, V_fixture 3.3: 20-80 % time 669ps typ, 1.52ns min, 415ps max; typ from 3.3 V to 1.67 V
|   falling waveform, R_fixture 50.0000, V_fixture 0: 20-80 % time 218ps typ, 388ps min, 171ps max; typ from 1.71 V to 0.006 V
[POWER_clamp]
|   voltage   I(typ)   I(min)   I(max)
-3.3V     84.32mA    65.35mA    103.1mA
-1.433V   22.74mA    18.5mA     28.08mA
-1.4V     21.71mA    17.66mA    26.88mA
-1.267V   17.93mA    14.4mA     22.37mA
-1.133V   14.39mA    11.27mA    18.03mA
-900mV    8.665mA    6.433mA    10.94mA
-800mV    6.531mA    4.71mA     8.375mA
-700mV    4.753mA    3.226mA    6.191mA
-500mV    1.907mA    1.132mA    2.522mA
-400mV    899.8uA    474uA      1.209mA
-300mV    293.2uA    123.6uA    420uA
0V        111.9nA    122.5nA    531.8nA
[Pulldown]
|   voltage   I(typ)   I(min)   I(max)
-3.3V     -1.414mA   -824.1uA   -1.452mA
-1.4V     -13.07mA   -7.326mA   -16.5mA
-700mV    -12.23mA   -8.654mA   -14.53mA
-400mV    -8.953mA   -6.328mA   -11.03mA
900mV     19.23mA    13.53mA    24.49mA
1.7V      31.8mA     22.09mA    40.92mA
2.2V      34.3mA     23.59mA    44.86mA
3.6V      35.6mA     23.82mA    47mA
4.1V      30.15mA    18.74mA    43.06mA
5.2V      11.04mA    3.801mA    19.25mA
6V        3.363mA    1.319mA    7.626mA
6.6V      1.491mA    943.8uA    2.62mA
[Pullup]
|   voltage   I(typ)   I(min)   I(max)
-3.3V     5.279mA    1.884mA    7.054mA
-1.6V     14.12mA    7.965mA    18.56mA
-600mV    10.83mA    7.699mA    13.81mA
-300mV    6.725mA    4.699mA    8.613mA
1.3V      -28.42mA   -18.84mA   -36.71mA
2.2V      -44.3mA    -26.6mA    -57.75mA
2.9V      -51.63mA   -28.89mA   -69.52mA
3.8V      -55.14mA   -28.28mA   -77mA
4.5V      -44.15mA   -16.42mA   -66.65mA
5.2V      -25.74mA   -4.289mA   -47.12mA
6.1V      -6.779mA   -1.091mA   -17.19mA
6.6V      -2.662mA   -795.8uA   -9.106mA
[GND_clamp]
|   voltage   I(typ)   I(min)   I(max)
-3.3V     -100.5mA   -79.35mA   -120.4mA
-1.3V     -21.87mA   -19.02mA   -26.83mA
-1.233V   -19.47mA   -17.03mA   -24.18mA
-1.167V   -17.17mA   -15.07mA   -21.57mA
-1.1V     -14.95mA   -13.14mA   -19.02mA
-1.033V   -12.86mA   -11.27mA   -16.52mA
-900mV    -8.833mA   -7.703mA   -11.7mA
-700mV    -4.051mA   -3.271mA   -6.08mA
-500mV    -1.133mA   -786.3uA   -2.116mA
-366.7mV  -308.6uA   -210uA     -649.4uA
-166.7mV  -140.1uA   -74.78uA   -198.2uA
3.233V    -8.681uA   9.343uA    -38.22uA
[Ramp]
| variable   typ   min   max
dV/dt_f  0.9827887/0.667889n   0.7538234/1.694902n   1.169384/0.4169941n
dV/dt_r   1.030693/0.8543755n   0.765609/2.330513n   1.220524/0.4706604n
R_load = 50
[Rising Waveform]
R_fixture = 50.0000
V_fixture = 3.3
V_fixture_min = 3.14
V_fixture_max = 3.47
|   time   V(typ)   V(min)   V(max)
0s        1.71V      1.983V     1.55V
88ps      1.711V     1.984V     1.713V
176ps     1.739V     1.984V     2.665V
208ps     1.797V     1.984V     2.881V
352ps     2.759V     1.983V     3.272V
440ps     2.945V     1.985V     3.401V
584ps     3.153V     2.097V     3.453V
808ps     3.275V     2.813V     3.463V
1.016ns   3.29V      2.994V     3.466V
2.288ns   3.298V     3.134V     3.469V
[Rising Waveform]
R_fixture = 50.0000
V_fixture = 0
V_fixture_min = 0
V_fixture_max = 0
|   time   V(typ)   V(min)   V(max)
0s        3.18mV     1.956mV    3.875mV
192ps     -1.892mV   1.939mV    151.2mV
432ps     39.79mV    649.9uV    701.7mV
760ps     438.2mV    -669.7uV   1.613V
1.248ns   1.177V     8.143mV    1.847V
1.472ns   1.345V     86.29mV    1.911V
2.672ns   1.641V     544.8mV    2.016V
3.312ns   1.682V     820.7mV    2.023V
4.672ns   1.702V     1.1V       2.028V
8.728ns   1.712V     1.242V     2.031V
[Falling Waveform]
R_fixture = 50.0000
V_fixture = 3.3
V_fixture_min = 3.14
V_fixture_max = 3.47
|   time   V(typ)   V(min)   V(max)
0s        3.3V       3.14V      3.47V
280ps     3.273V     3.145V     2.849V
424ps     3.125V     3.146V     2.495V
608ps     2.874V     3.144V     1.889V
784ps     2.657V     3.141V     1.71V
1.16ns    2.041V     3.055V     1.605V
1.52ns    1.831V     2.865V     1.564V
2.232ns   1.712V     2.575V     1.536V
3.136ns   1.677V     2.148V     1.533V
4.08ns    1.672V     1.99V      1.533V
[Falling Waveform]
R_fixture = 50.0000
V_fixture = 0
V_fixture_min = 0
V_fixture_max = 0
|   time   V(typ)   V(min)   V(max)
0s        1.711V     1.249V     2.029V
56ps      1.705V     1.249V     1.978V
96ps      1.685V     1.25V      1.821V
168ps     1.545V     1.248V     1.269V
256ps     1.094V     1.231V     523.4mV
360ps     487.7mV    1.153V     253.1mV
472ps     277.9mV    909.9mV    65.01mV
672ps     80.63mV    419.6mV    15.38mV
984ps     12.98mV    135.2mV    8.566mV
2.16ns    5.644mV    8.324mV    4.933mV
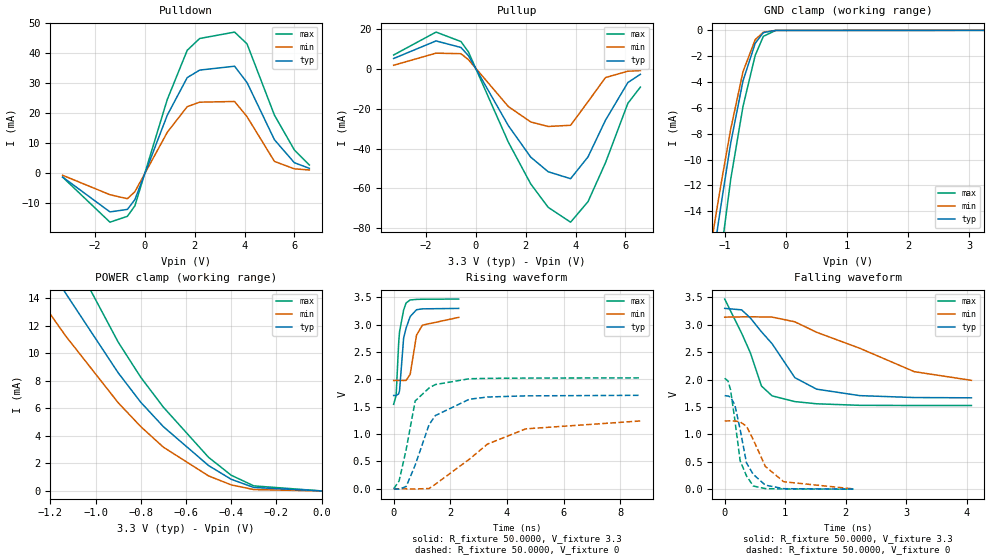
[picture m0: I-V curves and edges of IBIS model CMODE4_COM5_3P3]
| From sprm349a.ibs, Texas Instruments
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|   Model Cell CMODE4_COM5_3P3
|CMODE4_COM5_3P3
[Model]   CMODE4_COM5_3P3
Model_type   I/O
Polarity   Non-Inverting
Enable   Active-Low
Vinl =  0.8V
Vinh =  2V
Cref =  15.0000pF
Rref =  100.0000M
Vref =  0V
Vmeas =  1.65
C_comp   1.705749p   1.661847p   1.750916p
[Model Spec]
Vinl   0.8V   0.8V   0.8V
Vinh   2V   2V   2V
[Temperature Range]   25   105   0
[Voltage Range]   3.3   3.14   3.47
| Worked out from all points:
|   slope of the pulldown table from 0 to 0.495 V, typ, clamps not added: 45.1 ohm
|   slope of the pullup table from 0 to 0.495 V, typ, clamps not added: 43.8 ohm
|   GND clamp passes 1 mA (typ) near -0.50 V on its own axis
|   POWER clamp passes 1 mA (typ) near -0.42 V on its own axis
|   rising waveform, R_fixture 50.0000, V_fixture 3.3: 20-80 % time 205ps typ, 278ps min, 169ps max; typ from 1.71 V to 3.3 V
|   rising waveform, R_fixture 50.0000, V_fixture 0: 20-80 % time 851ps typ, 2.22ns min, 472ps max; typ from 0 V to 1.71 V
|   falling waveform, R_fixture 50.0000, V_fixture 3.3: 20-80 % time 668ps typ, 1.52ns min, 414ps max; typ from 3.3 V to 1.67 V
|   falling waveform, R_fixture 50.0000, V_fixture 0: 20-80 % time 217ps typ, 387ps min, 170ps max; typ from 1.71 V to 0.002 V
[POWER_clamp]
|   voltage   I(typ)   I(min)   I(max)
-3.3V     84.32mA    65.35mA    103.1mA
-1.433V   22.73mA    18.49mA    28.07mA
-1.4V     21.7mA     17.66mA    26.87mA
-1.267V   17.92mA    14.39mA    22.36mA
-1.133V   14.37mA    11.27mA    17.99mA
-900mV    8.579mA    6.408mA    10.81mA
-800mV    6.436mA    4.67mA     8.251mA
-700mV    4.665mA    3.176mA    6.079mA
-500mV    1.84mA     1.09mA     2.437mA
-400mV    844.9uA    439.4uA    1.139mA
-300mV    251.4uA    97.42uA    366.8uA
0V        112.2nA    122.7nA    532.8nA
[Pulldown]
|   voltage   I(typ)   I(min)   I(max)
-3.3V     -1.414mA   -824.1uA   -1.452mA
-1.4V     -13.07mA   -7.325mA   -16.5mA
-700mV    -12.23mA   -8.654mA   -14.53mA
-400mV    -8.953mA   -6.328mA   -11.04mA
900mV     19.24mA    13.53mA    24.49mA
1.7V      31.8mA     22.09mA    40.92mA
2.2V      34.3mA     23.59mA    44.86mA
3.6V      35.6mA     23.82mA    47mA
4.1V      30.15mA    18.74mA    43.06mA
5.2V      11.04mA    3.801mA    19.25mA
6V        3.363mA    1.319mA    7.626mA
6.6V      1.491mA    943.8uA    2.62mA
[Pullup]
|   voltage   I(typ)   I(min)   I(max)
-3.3V     5.279mA    1.884mA    7.054mA
-1.6V     14.12mA    7.965mA    18.56mA
-600mV    10.83mA    7.699mA    13.81mA
-300mV    6.725mA    4.699mA    8.614mA
1.3V      -28.42mA   -18.84mA   -36.71mA
2.2V      -44.3mA    -26.6mA    -57.75mA
2.9V      -51.63mA   -28.89mA   -69.52mA
3.8V      -55.14mA   -28.28mA   -77mA
4.5V      -44.15mA   -16.42mA   -66.65mA
5.2V      -25.74mA   -4.289mA   -47.12mA
6.1V      -6.779mA   -1.091mA   -17.19mA
6.6V      -2.662mA   -795.8uA   -9.106mA
[GND_clamp]
|   voltage   I(typ)   I(min)   I(max)
-3.3V     -100.4mA   -79.29mA   -120.2mA
-1.3V     -21.74mA   -18.95mA   -26.65mA
-1.233V   -19.35mA   -16.97mA   -24mA
-1.167V   -17.04mA   -15.01mA   -21.4mA
-1.1V     -14.82mA   -13.07mA   -18.84mA
-1.033V   -12.73mA   -11.2mA    -16.34mA
-900mV    -8.706mA   -7.637mA   -11.52mA
-700mV    -3.917mA   -3.203mA   -5.893mA
-500mV    -997.2uA   -716uA     -1.928mA
-366.7mV  -173.2uA   -139.7uA   -460.9uA
-166.7mV  -4.979uA   -4.712uA   -10.06uA
3.233V    80.04nA    1.448uA    400.3nA
[Ramp]
| variable   typ   min   max
dV/dt_f  0.9852606/0.6661147n  0.7553803/1.692241n   1.172374/0.4159186n
dV/dt_r   1.031423/0.8563272n  0.7657462/2.331803n   1.221672/0.4717767n
R_load = 50
[Rising Waveform]
R_fixture = 50.0000
V_fixture = 3.3
V_fixture_min = 3.14
V_fixture_max = 3.47
|   time   V(typ)   V(min)   V(max)
0s        1.706V     1.98V      1.545V
88ps      1.706V     1.981V     1.707V
176ps     1.735V     1.981V     2.657V
208ps     1.792V     1.981V     2.874V
352ps     2.753V     1.98V      3.267V
440ps     2.94V      1.982V     3.399V
584ps     3.15V      2.094V     3.453V
808ps     3.274V     2.81V      3.463V
1.016ns   3.29V      2.992V     3.466V
2.296ns   3.298V     3.134V     3.469V
[Rising Waveform]
R_fixture = 50.0000
V_fixture = 0
V_fixture_min = 0
V_fixture_max = 0
|   time   V(typ)   V(min)   V(max)
0s        39.15uV    22.51uV    60.16uV
192ps     -6.987mV   5.496uV    142.7mV
440ps     40.33mV    -1.407mV   712mV
760ps     431.9mV    -3.798mV   1.606V
1.248ns   1.169V     4.712mV    1.842V
1.472ns   1.339V     82.86mV    1.906V
2.672ns   1.637V     540.6mV    2.012V
3.312ns   1.678V     816.9mV    2.019V
4.664ns   1.699V     1.096V     2.024V
8.712ns   1.709V     1.24V      2.028V
[Falling Waveform]
R_fixture = 50.0000
V_fixture = 3.3
V_fixture_min = 3.14
V_fixture_max = 3.47
|   time   V(typ)   V(min)   V(max)
0s        3.3V       3.14V      3.47V
280ps     3.273V     3.145V     2.847V
424ps     3.125V     3.146V     2.49V
608ps     2.873V     3.144V     1.883V
784ps     2.655V     3.141V     1.704V
1.16ns    2.036V     3.055V     1.599V
1.52ns    1.826V     2.864V     1.559V
2.232ns   1.708V     2.573V     1.531V
3.136ns   1.673V     2.145V     1.528V
4.08ns    1.668V     1.987V     1.528V
[Falling Waveform]
R_fixture = 50.0000
V_fixture = 0
V_fixture_min = 0
V_fixture_max = 0
|   time   V(typ)   V(min)   V(max)
0s        1.707V     1.246V     2.025V
56ps      1.701V     1.247V     1.974V
96ps      1.682V     1.248V     1.817V
168ps     1.541V     1.245V     1.263V
256ps     1.088V     1.228V     516.2mV
360ps     481.7mV    1.15V      245.3mV
472ps     271.8mV    906.5mV    58.87mV
672ps     74.68mV    416.3mV    11.01mV
976ps     9.519mV    136.2mV    4.551mV
2.128ns   2.401mV    6.371mV    1.075mV
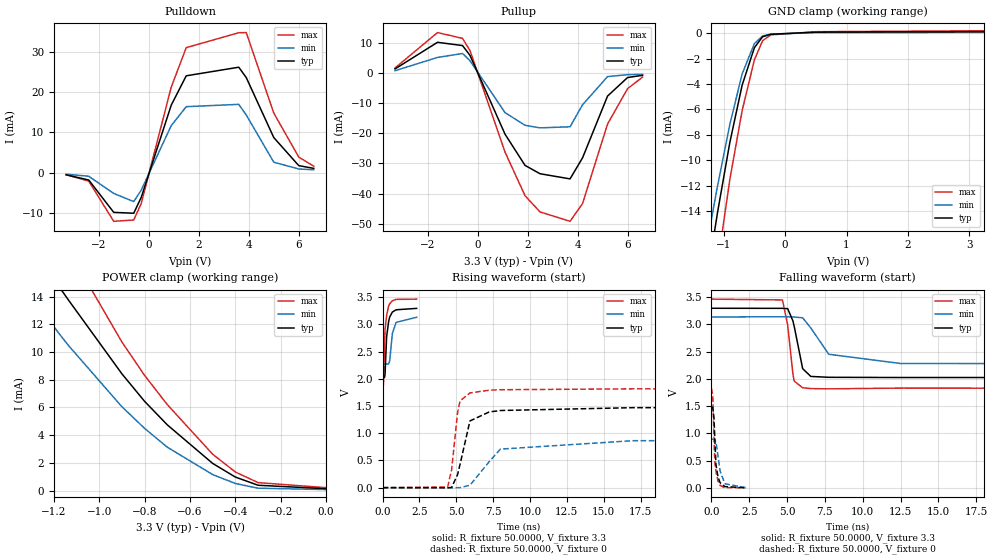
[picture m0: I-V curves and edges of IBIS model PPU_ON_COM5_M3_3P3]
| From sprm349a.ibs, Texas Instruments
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|   Model Cell PPU_ON_COM5_M3_3P3
|PPU_ON_COM5_M3_3P3
[Model]   PPU_ON_COM5_M3_3P3
Model_type   I/O
Polarity   Non-Inverting
Enable   Active-Low
Vinl =  0.8V
Vinh =  2V
Cref =  15.0000pF
Rref =  100.0000M
Vref =  0V
Vmeas =  1.65
C_comp   1.471252p   1.43537p   1.511509p
[Model Spec]
Vinl   0.8V   0.8V   0.8V
Vinh   2V   2V   2V
[Temperature Range]   25   105   0
[Voltage Range]   3.3   3.14   3.47
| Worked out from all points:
|   slope of the pulldown table from 0 to 0.495 V, typ, clamps not added: 50.8 ohm
|   slope of the pullup table from 0 to 0.495 V, typ, clamps not added: 51.2 ohm
|   GND clamp passes 1 mA (typ) near -0.48 V on its own axis
|   POWER clamp passes 1 mA (typ) near -0.40 V on its own axis
|   rising waveform, R_fixture 50.0000, V_fixture 3.3: 20-80 % time 200ps typ, 273ps min, 168ps max; typ from 2.02 V to 3.29 V
|   rising waveform, R_fixture 50.0000, V_fixture 0: 20-80 % time 706ps typ, 1.65ns min, 426ps max; typ from 0 V to 1.48 V
|   falling waveform, R_fixture 50.0000, V_fixture 3.3: 20-80 % time 553ps typ, 1.54ns min, 406ps max; typ from 3.3 V to 2.02 V
|   falling waveform, R_fixture 50.0000, V_fixture 0: 20-80 % time 185ps typ, 317ps min, 148ps max; typ from 1.49 V to 0.002 V
[POWER_clamp]
|   voltage   I(typ)   I(min)   I(max)
-3.3V     77.91mA    59.72mA    95.29mA
-1.467V   22.2mA     17.74mA    27.49mA
-1.3V     17.73mA    13.98mA    22.25mA
-1.167V   14.48mA    11.12mA    18.27mA
-1.133V   13.69mA    10.42mA    17.29mA
-900mV    8.425mA    6.05mA     10.72mA
-800mV    6.438mA    4.488mA    8.31mA
-700mV    4.744mA    3.133mA    6.204mA
-500mV    1.961mA    1.156mA    2.623mA
-400mV    976.4uA    512.8uA    1.342mA
-300mV    387.1uA    172.9uA    577.2uA
0V        135.7uA    75.28uA    210.9uA
[Pulldown]
|   voltage   I(typ)   I(min)   I(max)
-3.3V     -544.2uA   -400.3uA   -550.1uA
-2.4V     -1.845mA   -905.6uA   -2.119mA
-1.4V     -9.905mA   -5.191mA   -12.13mA
-600mV    -10.12mA   -7.213mA   -11.81mA
-300mV    -6.173mA   -4.366mA   -7.707mA
900mV     16.8mA     11.71mA    21.28mA
1.5V      24.11mA    16.42mA    31.12mA
3.6V      26.25mA    17mA       34.84mA
3.9V      23.67mA    14.35mA    34.88mA
5V        8.731mA    2.591mA    14.83mA
6V        1.731mA    900uA      3.86mA
6.6V      1.052mA    698.2uA    1.588mA
[Pullup]
|   voltage   I(typ)   I(min)   I(max)
-3.3V     1.325mA    742.3uA    1.643mA
-1.6V     10.17mA    5.149mA    13.4mA
-600mV    9.081mA    6.451mA    11.47mA
-300mV    5.824mA    4.052mA    7.406mA
1.1V      -20.32mA   -13.16mA   -26.27mA
1.9V      -30.67mA   -17.37mA   -40.73mA
2.5V      -33.44mA   -18.22mA   -46.11mA
3.7V      -35.15mA   -17.86mA   -49.22mA
4.2V      -28.16mA   -10.56mA   -43.32mA
5.2V      -7.672mA   -1.2mA     -16.95mA
6V        -1.511mA   -580.1uA   -5.196mA
6.6V      -790.2uA   -430.8uA   -1.375mA
[GND_clamp]
|   voltage   I(typ)   I(min)   I(max)
-3.3V     -92.33mA   -71.68mA   -112mA
-1.367V   -22.63mA   -19.12mA   -27.94mA
-1.3V     -20.32mA   -17.3mA    -25.37mA
-1.233V   -18.17mA   -15.52mA   -22.94mA
-1.1V     -14.11mA   -12.02mA   -18.22mA
-900mV    -8.592mA   -7.171mA   -11.51mA
-700mV    -4.086mA   -3.198mA   -6.093mA
-500mV    -1.121mA   -799.3uA   -2.081mA
-366.7mV  -263.9uA   -200.4uA   -575.9uA
-233.3mV  -71.45uA   -52.67uA   -115.9uA
500mV     96.72uA    58.31uA    132.4uA
3.233V    135.4uA    76.76uA    209.8uA
[Ramp]
| variable   typ   min   max
dV/dt_f  0.7714156/0.5567396n  0.5284734/1.292152n   1.002511/0.4090988n
dV/dt_r   0.895255/0.7081965n  0.5352647/1.670398n   1.101182/0.4273976n
R_load = 50
[Rising Waveform]
R_fixture = 50.0000
V_fixture = 3.3
V_fixture_min = 3.14
V_fixture_max = 3.47
|   time   V(typ)   V(min)   V(max)
0s        2.017V     2.272V     1.805V
60ps      2.018V     2.274V     1.902V
135ps     2.027V     2.274V     2.697V
165ps     2.089V     2.274V     2.904V
270ps     2.771V     2.273V     3.162V
405ps     3.048V     2.273V     3.333V
480ps     3.137V     2.333V     3.378V
660ps     3.227V     2.832V     3.435V
915ps     3.269V     3.038V     3.46V
2.31ns    3.295V     3.131V     3.465V
[Rising Waveform]
R_fixture = 50.0000
V_fixture = 0
V_fixture_min = 0
V_fixture_max = 0
|   time   V(typ)   V(min)   V(max)
0s        52.1uV     27.83uV    83.14uV
4.41ns    -1.898mV   -1.253mV   12.54mV
4.68ns    3.144mV    -3.691mV   325.5mV
5.085ns   238.9mV    -397.1uV   1.375V
5.25ns    423.9mV    -105.3uV   1.593V
5.925ns   1.226V     45.03mV    1.741V
7.23ns    1.391V     476.5mV    1.791V
7.995ns   1.418V     708.2mV    1.8V
16.98ns   1.47V      863.3mV    1.816V
115.8ns   1.482V     884.6mV    1.828V
[Falling Waveform]
R_fixture = 50.0000
V_fixture = 3.3
V_fixture_min = 3.14
V_fixture_max = 3.47
|   time   V(typ)   V(min)   V(max)
0s        3.297V     3.138V     3.465V
4.695ns   3.296V     3.141V     3.45V
5.04ns    3.29V      3.14V      2.991V
5.385ns   3.067V     3.137V     2.094V
5.475ns   2.961V     3.136V     1.96V
6.03ns    2.189V     3.122V     1.838V
6.57ns    2.046V     2.935V     1.823V
7.755ns   2.03V      2.453V     1.818V
12.51ns   2.026V     2.283V     1.832V
121.9ns   2.024V     2.269V     1.806V
[Falling Waveform]
R_fixture = 50.0000
V_fixture = 0
V_fixture_min = 0
V_fixture_max = 0
|   time   V(typ)   V(min)   V(max)
0s        1.489V     892.5mV    1.829V
90ps      1.472V     894mV      1.695V
165ps     1.29V      894.3mV    1.011V
195ps     1.114V     891mV      678.7mV
225ps     895.8mV    884.5mV    481.9mV
300ps     430.2mV    843.9mV    300.3mV
435ps     199.4mV    583.7mV    124.7mV
570ps     96.85mV    315.7mV    45.9mV
885ps     23.96mV    75.05mV    3.734mV
2.25ns    1.506mV    6.59mV     478.3uV
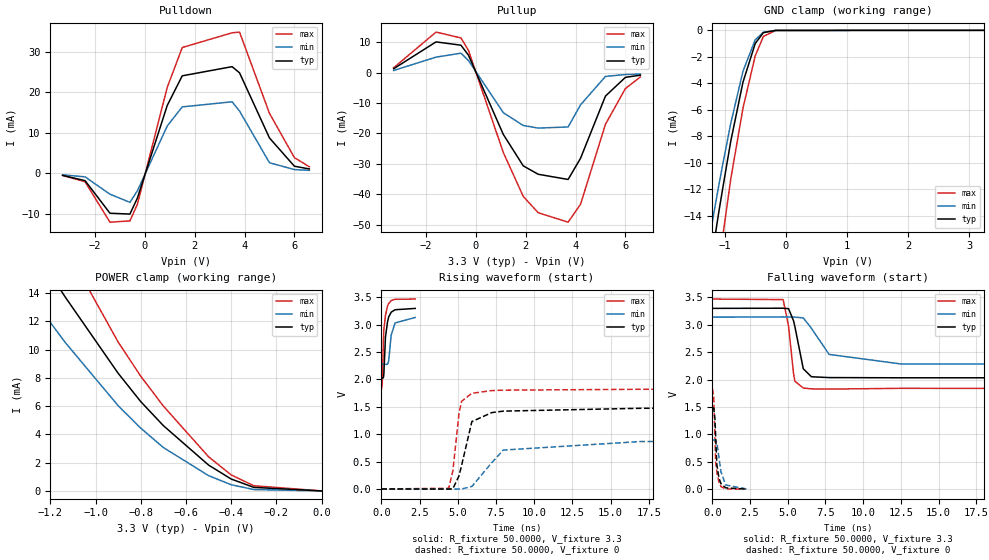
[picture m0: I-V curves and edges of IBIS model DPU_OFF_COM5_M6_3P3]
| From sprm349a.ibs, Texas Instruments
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|DPU_ON_IND5_M3_3P3BUFFER OPERATING AT 100UA IN SLOWEST MODE WITH INDTEMP AT
| PLUS OR MINUS 5PERCENT VDDS WITH PULLDOWN ON
|COM AND INDE ARE TWO DIFFERENT TEMP MODES.
|COM IS 25,0,105(NOM,STRONG,WEAK)
|IND IS 25,-40,125(NOM,STRONG,WEAK)
|   Model Cell DPU_OFF_COM5_M6_3P3
|DPU_OFF_COM5_M6_3P3
[Model]   DPU_OFF_COM5_M6_3P3
Model_type   I/O
Polarity   Non-Inverting
Enable   Active-Low
Vinl =  0.8V
Vinh =  2V
Cref =  15.0000pF
Rref =  100.0000M
Vref =  0V
Vmeas =  1.65
C_comp   1.482056p   1.446471p   1.52328p
[Model Spec]
Vinl   0.8V   0.8V   0.8V
Vinh   2V   2V   2V
[Temperature Range]   25   105   0
[Voltage Range]   3.3   3.14   3.47
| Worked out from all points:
|   slope of the pulldown table from 0 to 0.495 V, typ, clamps not added: 50.8 ohm
|   slope of the pullup table from 0 to 0.495 V, typ, clamps not added: 51.2 ohm
|   GND clamp passes 1 mA (typ) near -0.50 V on its own axis
|   POWER clamp passes 1 mA (typ) near -0.42 V on its own axis
|   rising waveform, R_fixture 50.0000, V_fixture 3.3: 20-80 % time 200ps typ, 273ps min, 169ps max; typ from 2.02 V to 3.3 V
|   rising waveform, R_fixture 50.0000, V_fixture 0: 20-80 % time 703ps typ, 1.64ns min, 425ps max; typ from 0 V to 1.49 V
|   falling waveform, R_fixture 50.0000, V_fixture 3.3: 20-80 % time 554ps typ, 1.6ns min, 405ps max; typ from 3.3 V to 2.03 V
|   falling waveform, R_fixture 50.0000, V_fixture 0: 20-80 % time 186ps typ, 319ps min, 150ps max; typ from 1.49 V to 0.002 V
[POWER_clamp]
|   voltage   I(typ)   I(min)   I(max)
-3.3V     79.08mA    60.56mA    96.76mA
-1.467V   22.39mA    17.93mA    27.69mA
-1.433V   21.44mA    17.15mA    26.58mA
-1.267V   16.99mA    13.37mA    21.3mA
-1.133V   13.7mA     10.49mA    17.24mA
-900mV    8.328mA    6.033mA    10.54mA
-800mV    6.321mA    4.443mA    8.119mA
-700mV    4.621mA    3.071mA    6.007mA
-500mV    1.829mA    1.083mA    2.416mA
-400mV    841.5uA    437.9uA    1.132mA
-300mV    250.9uA    97.3uA     365.7uA
0V        112.3nA    122.8nA    533.2nA
[Pulldown]
|   voltage   I(typ)   I(min)   I(max)
-3.3V     -543.5uA   -399.7uA   -549.7uA
-2.4V     -1.843mA   -904.8uA   -2.118mA
-1.4V     -9.906mA   -5.191mA   -12.13mA
-600mV    -10.12mA   -7.213mA   -11.81mA
-300mV    -6.174mA   -4.366mA   -7.708mA
900mV     16.8mA     11.71mA    21.29mA
1.5V      24.11mA    16.42mA    31.12mA
3.5V      26.38mA    17.68mA    34.76mA
3.8V      24.85mA    15.38mA    34.94mA
5V        8.731mA    2.592mA    14.83mA
6V        1.731mA    900.9uA    3.861mA
6.6V      1.052mA    699uA      1.588mA
[Pullup]
|   voltage   I(typ)   I(min)   I(max)
-3.3V     1.325mA    743.3uA    1.642mA
-1.6V     10.17mA    5.149mA    13.4mA
-600mV    9.081mA    6.451mA    11.47mA
-300mV    5.824mA    4.053mA    7.407mA
1.1V      -20.32mA   -13.16mA   -26.27mA
1.9V      -30.67mA   -17.37mA   -40.73mA
2.5V      -33.44mA   -18.22mA   -46.11mA
3.7V      -35.15mA   -17.86mA   -49.23mA
4.2V      -28.16mA   -10.56mA   -43.32mA
5.2V      -7.671mA   -1.199mA   -16.95mA
6V        -1.51mA    -579.6uA   -5.192mA
6.6V      -789.4uA   -430.3uA   -1.374mA
[GND_clamp]
|   voltage   I(typ)   I(min)   I(max)
-3.3V     -90.71mA   -70.6mA    -109.8mA
-1.367V   -22.26mA   -18.84mA   -27.46mA
-1.3V     -19.99mA   -17.05mA   -24.94mA
-1.233V   -17.87mA   -15.29mA   -22.56mA
-1.1V     -13.86mA   -11.83mA   -17.9mA
-1.033V   -11.99mA   -10.18mA   -15.64mA
-900mV    -8.38mA    -7.029mA   -11.24mA
-700mV    -3.914mA   -3.084mA   -5.876mA
-500mV    -997.1uA   -715.8uA   -1.924mA
-366.7mV  -173uA     -139.6uA   -460uA
-166.7mV  -4.976uA   -4.706uA   -10.04uA
3.233V    80.1nA     1.448uA    400.3nA
[Ramp]
| variable   typ   min   max
dV/dt_f  0.7705457/0.5583509n  0.5282233/1.286517n   1.001345/0.4095409n
dV/dt_r   0.897847/0.7057053n  0.5371786/1.660811n   1.104416/0.4260268n
R_load = 50
[Rising Waveform]
R_fixture = 50.0000
V_fixture = 3.3
V_fixture_min = 3.14
V_fixture_max = 3.47
|   time   V(typ)   V(min)   V(max)
0s        2.024V     2.275V     1.813V
60ps      2.024V     2.278V     1.912V
135ps     2.033V     2.278V     2.705V
165ps     2.094V     2.278V     2.908V
270ps     2.771V     2.277V     3.168V
405ps     3.05V      2.277V     3.341V
480ps     3.141V     2.335V     3.387V
645ps     3.229V     2.809V     3.441V
900ps     3.274V     3.033V     3.465V
2.22ns    3.298V     3.133V     3.469V
[Rising Waveform]
R_fixture = 50.0000
V_fixture = 0
V_fixture_min = 0
V_fixture_max = 0
|   time   V(typ)   V(min)   V(max)
0s        45.31uV    27.5uV     68.49uV
4.41ns    -1.951mV   -1.202mV   12.48mV
4.68ns    3.126mV    -3.605mV   326.7mV
5.085ns   240.4mV    -394.6uV   1.382V
5.25ns    426.8mV    -104.2uV   1.6V
5.925ns   1.231V     45.76mV    1.748V
7.23ns    1.395V     480.9mV    1.797V
7.98ns    1.422V     710.5mV    1.805V
16.98ns   1.474V     866.7mV    1.821V
116ns     1.487V     887.8mV    1.834V
[Falling Waveform]
R_fixture = 50.0000
V_fixture = 3.3
V_fixture_min = 3.14
V_fixture_max = 3.47
|   time   V(typ)   V(min)   V(max)
0s        3.3V       3.14V      3.47V
4.695ns   3.303V     3.144V     3.46V
5.055ns   3.295V     3.143V     2.973V
5.385ns   3.073V     3.14V      2.109V
5.475ns   2.966V     3.14V      1.97V
6.03ns    2.198V     3.126V     1.847V
6.57ns    2.052V     2.937V     1.831V
7.74ns    2.037V     2.46V      1.827V
12.5ns    2.033V     2.286V     1.841V
122.1ns   2.03V      2.273V     1.815V
[Falling Waveform]
R_fixture = 50.0000
V_fixture = 0
V_fixture_min = 0
V_fixture_max = 0
|   time   V(typ)   V(min)   V(max)
0s        1.493V     895.8mV    1.834V
90ps      1.478V     897.3mV    1.702V
165ps     1.306V     897.5mV    1.023V
195ps     1.135V     894.3mV    690.6mV
225ps     919.5mV    887.8mV    489.9mV
300ps     443.8mV    847.1mV    306.9mV
435ps     205.9mV    586.5mV    128.6mV
570ps     100.2mV    317.6mV    47.74mV
885ps     24.79mV    76.12mV    3.823mV
2.25ns    1.54mV     6.519mV    490.8uV
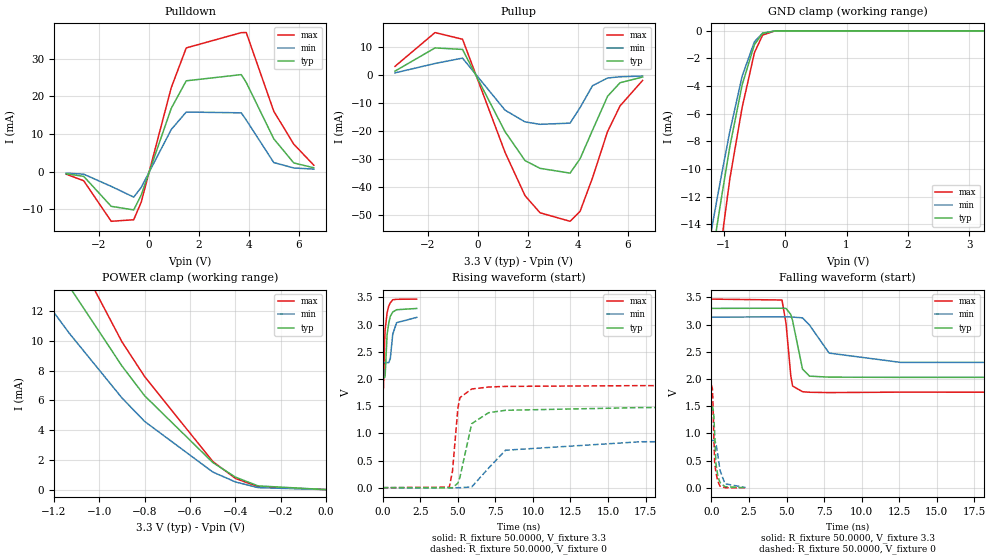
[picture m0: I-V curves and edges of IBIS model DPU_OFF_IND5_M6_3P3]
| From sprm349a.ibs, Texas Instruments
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|   Model Cell DPU_OFF_IND5_M6_3P3
|DPU_OFF_IND5_M6_3P3
[Model]   DPU_OFF_IND5_M6_3P3
Model_type   I/O
Polarity   Non-Inverting
Enable   Active-Low
Vinl =  0.8V
Vinh =  2V
Cref =  15.0000pF
Rref =  100.0000M
Vref =  0V
Vmeas =  1.65
C_comp   1.482056p   1.447507p   1.522513p
[Model Spec]
Vinl   0.8V   0.8V   0.8V
Vinh   2V   2V   2V
[Temperature Range]   25   125   -40
[Voltage Range]   3.3   3.14   3.47
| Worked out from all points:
|   slope of the pulldown table from 0 to 0.495 V, typ, clamps not added: 50.8 ohm
|   slope of the pullup table from 0 to 0.495 V, typ, clamps not added: 51.2 ohm
|   GND clamp passes 1 mA (typ) near -0.50 V on its own axis
|   POWER clamp passes 1 mA (typ) near -0.42 V on its own axis
|   rising waveform, R_fixture 50.0000, V_fixture 3.3: 20-80 % time 200ps typ, 279ps min, 163ps max; typ from 2.02 V to 3.3 V
|   rising waveform, R_fixture 50.0000, V_fixture 0: 20-80 % time 704ps typ, 1.7ns min, 350ps max; typ from 0 V to 1.49 V
|   falling waveform, R_fixture 50.0000, V_fixture 3.3: 20-80 % time 552ps typ, 1.59ns min, 356ps max; typ from 3.3 V to 2.03 V
|   falling waveform, R_fixture 50.0000, V_fixture 0: 20-80 % time 186ps typ, 329ps min, 145ps max; typ from 1.49 V to 0.002 V
[POWER_clamp]
|   voltage   I(typ)   I(min)   I(max)
-3.3V     79.08mA    58.44mA    96.49mA
-1.433V   21.44mA    16.95mA    26.18mA
-1.4V     20.49mA    16.21mA    25.11mA
-1.267V   16.99mA    13.32mA    20.88mA
-1.233V   16.16mA    12.62mA    19.83mA
-1.133V   13.7mA     10.55mA    16.72mA
-900mV    8.328mA    6.175mA    9.956mA
-800mV    6.321mA    4.593mA    7.613mA
-500mV    1.829mA    1.188mA    1.9mA
-400mV    841.5uA    516.4uA    754.4uA
-300mV    250.9uA    130.9uA    193.4uA
0V        112.3nA    202.2nA    235.2nA
[Pulldown]
|   voltage   I(typ)   I(min)   I(max)
-3.3V     -543.5uA   -373.2uA   -648.8uA
-2.6V     -1.225mA   -644.4uA   -2.395mA
-1.5V     -9.17mA    -3.874mA   -13.14mA
-600mV    -10.12mA   -6.728mA   -12.73mA
-300mV    -6.174mA   -4.15mA    -8.053mA
900mV     16.8mA     11.19mA    22.28mA
1.5V      24.11mA    15.83mA    32.83mA
3.7V      25.75mA    15.62mA    36.88mA
3.9V      23.67mA    13.71mA    36.9mA
5V        8.732mA    2.436mA    16.05mA
5.8V      2.332mA    999.4uA    7.305mA
6.6V      1.052mA    693.6uA    1.743mA
[Pullup]
|   voltage   I(typ)   I(min)   I(max)
-3.3V     1.325mA    694.3uA    3.025mA
-1.7V     9.619mA    4.052mA    15.11mA
-600mV    9.081mA    5.972mA    12.73mA
1.1V      -20.32mA   -12.63mA   -27.71mA
1.9V      -30.67mA   -16.84mA   -43.22mA
2.5V      -33.44mA   -17.7mA    -49.34mA
3.7V      -35.15mA   -17.28mA   -52.38mA
4.1V      -30.02mA   -11.73mA   -48.83mA
4.6V      -19.78mA   -3.878mA   -36.81mA
5.2V      -7.669mA   -1.144mA   -20.29mA
5.7V      -2.833mA   -699.6uA   -11.11mA
6.6V      -789.3uA   -429.7uA   -2.015mA
[GND_clamp]
|   voltage   I(typ)   I(min)   I(max)
-3.3V     -90.71mA   -68.17mA   -109.4mA
-1.3V     -19.99mA   -16.99mA   -24.66mA
-1.233V   -17.87mA   -15.3mA    -22.25mA
-1.167V   -15.83mA   -13.63mA   -19.86mA
-1.1V     -13.86mA   -11.98mA   -17.49mA
-1.033V   -11.99mA   -10.37mA   -15.16mA
-900mV    -8.38mA    -7.275mA   -10.71mA
-700mV    -3.914mA   -3.285mA   -5.554mA
-500mV    -997.1uA   -788uA     -1.586mA
-366.7mV  -173uA     -169.5uA   -301.8uA
-166.7mV  -4.976uA   -6.042uA   -6.589uA
3.233V    80.1nA     2.438uA    205.2nA
[Ramp]
| variable   typ   min   max
dV/dt_f  0.7706225/0.5584326n  0.5145051/1.313012n   1.04949/0.3599065n
dV/dt_r  0.8978173/0.7058892n  0.5229487/1.666188n   1.137833/0.3496137n
R_load = 50
[Rising Waveform]
R_fixture = 50.0000
V_fixture = 3.3
V_fixture_min = 3.14
V_fixture_max = 3.47
|   time   V(typ)   V(min)   V(max)
0s        2.024V     2.301V     1.734V
60ps      2.025V     2.303V     1.833V
135ps     2.025V     2.304V     2.704V
165ps     2.05V      2.304V     2.901V
300ps     2.824V     2.302V     3.222V
405ps     3.023V     2.301V     3.341V
510ps     3.152V     2.374V     3.402V
675ps     3.233V     2.825V     3.458V
930ps     3.275V     3.036V     3.467V
2.265ns   3.298V     3.134V     3.47V
[Rising Waveform]
R_fixture = 50.0000
V_fixture = 0
V_fixture_min = 0
V_fixture_max = 0
|   time   V(typ)   V(min)   V(max)
0s        45.3uV     29.13uV    68.26uV
4.44ns    -3.373mV   -60.21uV   9.119mV
4.65ns    -165.5uV   -2.279mV   306.3mV
5.01ns    84.41mV    -1.081mV   1.47V
5.145ns   194.1mV    -518.1uV   1.657V
5.925ns   1.177V     12.75mV    1.816V
7.05ns    1.38V      359.7mV    1.852V
8.175ns   1.424V     689.4mV    1.864V
17.18ns   1.474V     845.6mV    1.878V
116.1ns   1.487V     863.9mV    1.889V
[Falling Waveform]
R_fixture = 50.0000
V_fixture = 3.3
V_fixture_min = 3.14
V_fixture_max = 3.47
|   time   V(typ)   V(min)   V(max)
0s        3.3V       3.14V      3.47V
4.695ns   3.303V     3.143V     3.454V
4.965ns   3.299V     3.145V     3.022V
5.28ns    3.188V     3.141V     2.063V
5.4ns     3.075V     3.14V      1.873V
6.06ns    2.185V     3.126V     1.768V
6.525ns   2.054V     2.994V     1.758V
7.83ns    2.036V     2.478V     1.752V
12.59ns   2.032V     2.307V     1.76V
122ns     2.03V      2.297V     1.735V
[Falling Waveform]
R_fixture = 50.0000
V_fixture = 0
V_fixture_min = 0
V_fixture_max = 0
|   time   V(typ)   V(min)   V(max)
0s        1.493V     871.2mV    1.89V
60ps      1.492V     871.7mV    1.833V
90ps      1.479V     872.6mV    1.681V
150ps     1.371V     873.4mV    1.06V
210ps     1.037V     867mV      489.8mV
300ps     447.4mV    825.9mV    278.5mV
435ps     207mV      589.8mV    114.8mV
570ps     100.6mV    326mV      32.77mV
900ps     23.13mV    75.49mV    3.12mV
2.265ns   1.52mV     6.656mV    366.4uV
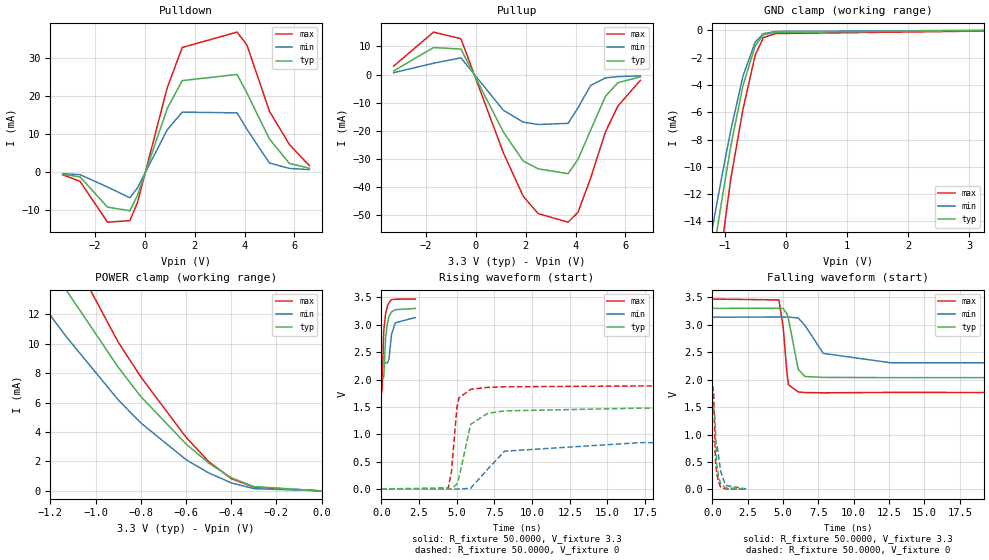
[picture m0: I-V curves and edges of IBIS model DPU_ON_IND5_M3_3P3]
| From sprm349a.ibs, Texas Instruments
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|   Model Cell DPU_ON_IND5_M3_3P3
|DPU_ON_IND5_M3_3P3
[Model]   DPU_ON_IND5_M3_3P3
Model_type   I/O
Polarity   Non-Inverting
Enable   Active-Low
Vinl =  0.8V
Vinh =  2V
Cref =  15.0000pF
Rref =  100.0000M
Vref =  0V
Vmeas =  1.65
C_comp   1.482056p   1.447507p   1.522513p
[Model Spec]
Vinl   0.8V   0.8V   0.8V
Vinh   2V   2V   2V
[Temperature Range]   25   125   -40
[Voltage Range]   3.3   3.14   3.47
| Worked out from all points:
|   slope of the pulldown table from 0 to 0.495 V, typ, clamps not added: 50.8 ohm
|   slope of the pullup table from 0 to 0.495 V, typ, clamps not added: 51.2 ohm
|   GND clamp passes 1 mA (typ) near -0.48 V on its own axis
|   POWER clamp passes 1 mA (typ) near -0.41 V on its own axis
|   rising waveform, R_fixture 50.0000, V_fixture 3.3: 20-80 % time 199ps typ, 278ps min, 161ps max; typ from 2.03 V to 3.3 V
|   rising waveform, R_fixture 50.0000, V_fixture 0: 20-80 % time 703ps typ, 1.67ns min, 350ps max; typ from 0.003 V to 1.49 V
|   falling waveform, R_fixture 50.0000, V_fixture 3.3: 20-80 % time 554ps typ, 1.61ns min, 357ps max; typ from 3.3 V to 2.04 V
|   falling waveform, R_fixture 50.0000, V_fixture 0: 20-80 % time 187ps typ, 331ps min, 147ps max; typ from 1.5 V to 0.005 V
[POWER_clamp]
|   voltage   I(typ)   I(min)   I(max)
-3.3V     79.08mA    58.44mA    96.49mA
-1.433V   21.45mA    16.95mA    26.2mA
-1.267V   17.01mA    13.33mA    20.92mA
-1.233V   16.17mA    12.62mA    19.88mA
-1.133V   13.73mA    10.55mA    16.81mA
-900mV    8.413mA    6.194mA    10.12mA
-800mV    6.415mA    4.625mA    7.762mA
-600mV    3.197mA    2.127mA    3.652mA
-500mV    1.895mA    1.228mA    2.001mA
-400mV    896.1uA    549uA      837.2uA
-300mV    292.5uA    155.7uA    256.1uA
0V        123.7nA    205.1nA    267.1nA
[Pulldown]
|   voltage   I(typ)   I(min)   I(max)
-3.3V     -543.6uA   -373.2uA   -648.9uA
-2.6V     -1.225mA   -644.4uA   -2.395mA
-1.5V     -9.17mA    -3.874mA   -13.14mA
-600mV    -10.12mA   -6.728mA   -12.73mA
-300mV    -6.174mA   -4.15mA    -8.052mA
900mV     16.8mA     11.19mA    22.28mA
1.5V      24.11mA    15.83mA    32.83mA
3.7V      25.74mA    15.62mA    36.88mA
4.1V      20.79mA    11.29mA    33.42mA
5V        8.732mA    2.436mA    16.05mA
5.8V      2.332mA    999.4uA    7.305mA
6.6V      1.052mA    693.6uA    1.743mA
[Pullup]
|   voltage   I(typ)   I(min)   I(max)
-3.3V     1.325mA    694.3uA    3.025mA
-1.7V     9.619mA    4.052mA    15.11mA
-600mV    9.081mA    5.972mA    12.73mA
1.1V      -20.32mA   -12.63mA   -27.71mA
1.9V      -30.67mA   -16.84mA   -43.22mA
2.5V      -33.44mA   -17.7mA    -49.34mA
3.7V      -35.15mA   -17.28mA   -52.38mA
4.1V      -30.02mA   -11.73mA   -48.83mA
4.6V      -19.78mA   -3.878mA   -36.81mA
5.2V      -7.67mA    -1.144mA   -20.29mA
5.7V      -2.834mA   -699.6uA   -11.11mA
6.6V      -789.3uA   -429.7uA   -2.016mA
[GND_clamp]
|   voltage   I(typ)   I(min)   I(max)
-3.3V     -90.84mA   -68.23mA   -109.6mA
-1.3V     -20.12mA   -17.05mA   -24.86mA
-1.233V   -18mA      -15.36mA   -22.46mA
-1.167V   -15.95mA   -13.69mA   -20.07mA
-1.1V     -13.98mA   -12.04mA   -17.69mA
-1.033V   -12.11mA   -10.43mA   -15.37mA
-900mV    -8.507mA   -7.337mA   -10.92mA
-700mV    -4.047mA   -3.349mA   -5.775mA
-500mV    -1.132mA   -854.9uA   -1.806mA
-366.7mV  -307.9uA   -236.6uA   -522.8uA
-166.7mV  -139.7uA   -72.98uA   -227.4uA
3.233V    -8.646uA   9.934uA    -44.79uA
[Ramp]
| variable   typ   min   max
dV/dt_f  0.7673103/0.5592351n  0.5129729/1.314723n   1.044558/0.3605954n
dV/dt_r  0.8976985/0.7047991n  0.5232642/1.663408n   1.136826/0.3490993n
R_load = 50
[Rising Waveform]
R_fixture = 50.0000
V_fixture = 3.3
V_fixture_min = 3.14
V_fixture_max = 3.47
|   time   V(typ)   V(min)   V(max)
0s        2.029V     2.303V     1.742V
60ps      2.03V      2.306V     1.841V
135ps     2.03V      2.306V     2.713V
165ps     2.056V     2.306V     2.907V
285ps     2.768V     2.305V     3.202V
405ps     3.027V     2.304V     3.345V
510ps     3.155V     2.377V     3.404V
675ps     3.234V     2.827V     3.459V
930ps     3.276V     3.037V     3.467V
2.25ns    3.298V     3.133V     3.47V
[Rising Waveform]
R_fixture = 50.0000
V_fixture = 0
V_fixture_min = 0
V_fixture_max = 0
|   time   V(typ)   V(min)   V(max)
0s        3.341mV    1.996mV    4.729mV
4.44ns    2.497mV    1.907mV    19.6mV
4.65ns    6.357mV    -116.4uV   316.4mV
5.01ns    90.89mV    2.129mV    1.48V
5.145ns   200.6mV    2.759mV    1.664V
5.925ns   1.184V     16.05mV    1.822V
7.05ns    1.384V     362.9mV    1.858V
8.175ns   1.429V     693.5mV    1.869V
17.11ns   1.478V     848.5mV    1.883V
115.5ns   1.491V     867.1mV    1.894V
[Falling Waveform]
R_fixture = 50.0000
V_fixture = 3.3
V_fixture_min = 3.14
V_fixture_max = 3.47
|   time   V(typ)   V(min)   V(max)
0s        3.3V       3.14V      3.47V
4.71ns    3.303V     3.143V     3.454V
5.01ns    3.299V     3.145V     2.957V
5.28ns    3.201V     3.141V     2.115V
5.385ns   3.107V     3.141V     1.907V
6.075ns   2.19V      3.126V     1.777V
6.54ns    2.059V     2.994V     1.766V
7.845ns   2.042V     2.48V      1.761V
12.62ns   2.038V     2.309V     1.769V
122.4ns   2.036V     2.299V     1.743V
[Falling Waveform]
R_fixture = 50.0000
V_fixture = 0
V_fixture_min = 0
V_fixture_max = 0
|   time   V(typ)   V(min)   V(max)
0s        1.498V     874.4mV    1.895V
90ps      1.491V     875.4mV    1.78V
165ps     1.376V     876.6mV    1.069V
195ps     1.24V      874.7mV    715.1mV
225ps     1.043V     870.2mV    498.1mV
315ps     453.2mV    829.1mV    288.3mV
450ps     213.5mV    593.2mV    125.5mV
585ps     107.4mV    328.8mV    42.06mV
930ps     27.91mV    74.54mV    7.996mV
2.4ns     4.931mV    8.545mV    5.136mV
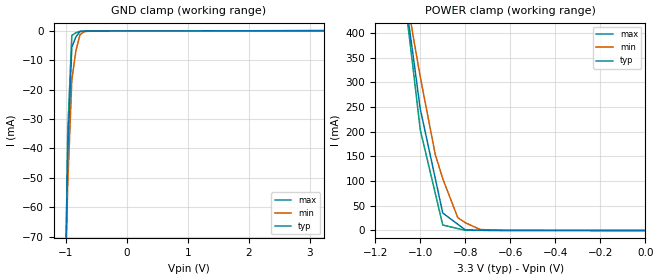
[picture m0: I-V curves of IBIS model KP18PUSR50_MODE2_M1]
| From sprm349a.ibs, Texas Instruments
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|   Model Cell KP18PUSR50_MODE2_M1
[Model]   KP18PUSR50_MODE2_M1
Model_type   Input
Polarity   Non-Inverting
Vinl =  0.8V
Vinh =  2V
C_comp   0.5006264p   0.4546714p   0.5618888p
[Model Spec]
Vinl   0.8V   0.8V   0.8V
Vinh   2V   2V   2V
[Temperature Range]   25   125   -40
[Voltage Range]   3.3   3.14   3.47
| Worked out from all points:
|   GND clamp passes 1 mA (typ) near -0.79 V on its own axis
|   POWER clamp passes 1 mA (typ) near -0.78 V on its own axis
[POWER_clamp]
|   voltage   I(typ)   I(min)   I(max)
-3.3V     9.936A     8.461A     11.24A
-1.067V   472.1mA    495.3mA    462.5mA
-1.033V   359.2mA    397.5mA    333.3mA
-1V       246.3mA    311.2mA    204.1mA
-933.3mV  105.6mA    154mA      75.38mA
-900mV    35.32mA    104.8mA    11.03mA
-833.3mV  12.6mA     25.99mA    3.86mA
-800mV    1.234mA    15.69mA    276.3uA
-733.3mV  498uA      1.891mA    196.7uA
-633.3mV  102.9uA    189.5uA    140.5uA
-11.55fV  95.23nA    127nA      222.7nA
[GND_clamp]
|   voltage   I(typ)   I(min)   I(max)
-3.3V     -13.46A    -11.36A    -15.18A
-1.033V   -115.5mA   -109.9mA   -127.9mA
-966.7mV  -41.01mA   -52.17mA   -34mA
-900mV    -5.577mA   -16.76mA   -1.644mA
-833.3mV  -2.123mA   -6.88mA    -716.3uA
-766.7mV  -314.7uA   -1.418mA   -243.7uA
-700mV    -151.3uA   -374.8uA   -226.4uA
-633.3mV  -142.3uA   -207.1uA   -225.8uA
3.233V    -8.718uA   7.659uA    -45.2uA
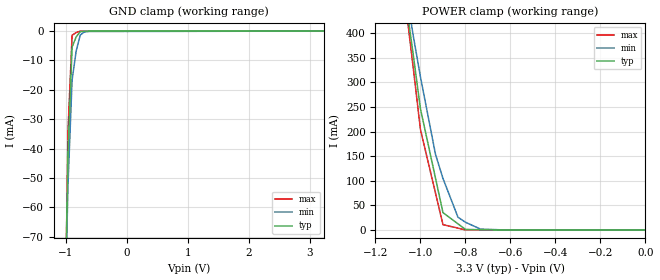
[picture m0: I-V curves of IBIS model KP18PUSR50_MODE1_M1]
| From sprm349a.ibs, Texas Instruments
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|   Model Cell KP18PUSR50_MODE1_M1
[Model]   KP18PUSR50_MODE1_M1
Model_type   Input
Polarity   Non-Inverting
Vinl =  0.8V
Vinh =  2V
C_comp   0.5006264p   0.4546714p   0.5618888p
[Model Spec]
Vinl   0.8V   0.8V   0.8V
Vinh   2V   2V   2V
[Temperature Range]   25   125   -40
[Voltage Range]   3.3   3.14   3.47
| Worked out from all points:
|   GND clamp passes 1 mA (typ) near -0.80 V on its own axis
|   POWER clamp passes 1 mA (typ) near -0.79 V on its own axis
[POWER_clamp]
|   voltage   I(typ)   I(min)   I(max)
-3.3V     9.936A     8.461A     11.24A
-1.067V   472.1mA    495.3mA    462.4mA
-1.033V   359.2mA    397.5mA    333.2mA
-1V       246.2mA    311.2mA    204mA
-933.3mV  105.6mA    154mA      75.24mA
-900mV    35.25mA    104.8mA    10.87mA
-833.3mV  12.51mA    25.96mA    3.706mA
-800mV    1.138mA    15.66mA    124.4uA
-733.3mV  407uA      1.851mA    55uA
-633.3mV  21.13uA    144.1uA    14.79uA
-11.55fV  95.71nA    92.71nA    222.9nA
[GND_clamp]
|   voltage   I(typ)   I(min)   I(max)
-3.3V     -13.46A    -11.36A    -15.18A
-1.033V   -115.4mA   -109.9mA   -127.7mA
-966.7mV  -40.89mA   -52.11mA   -33.8mA
-900mV    -5.45mA    -16.7mA    -1.431mA
-833.3mV  -1.994mA   -6.818mA   -498.3uA
-766.7mV  -182.5uA   -1.354mA   -22.34uA
-700mV    -16.43uA   -310.5uA   -3.203uA
-633.3mV  -6.588uA   -141.5uA   -2.606uA
3.233V    94.11nA    98.58nA    210.4nA
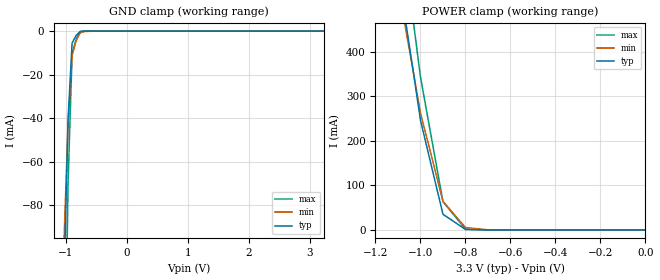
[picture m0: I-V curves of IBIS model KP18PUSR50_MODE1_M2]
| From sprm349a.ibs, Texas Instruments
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|   Model Cell KP18PUSR50_MODE1_M2
[Model]   KP18PUSR50_MODE1_M2
Model_type   Input
Polarity   Non-Inverting
Vinl =  0.8V
Vinh =  2V
C_comp   0.5006264p   0.4551273p   0.5623334p
[Model Spec]
Vinl   0.8V   0.8V   0.8V
Vinh   2V   2V   2V
[Temperature Range]   25   105   0
[Voltage Range]   3.3   3.14   3.47
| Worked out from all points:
|   GND clamp passes 1 mA (typ) near -0.80 V on its own axis
|   POWER clamp passes 1 mA (typ) near -0.79 V on its own axis
[POWER_clamp]
|   voltage   I(typ)   I(min)   I(max)
-3.3V     9.936A     8.589A     10.91A
-1.067V   472.1mA    454mA      602.9mA
-1.033V   359.2mA    358.5mA    473.2mA
-1V       246.2mA    263mA      343.5mA
-900mV    35.25mA    64.31mA    63.51mA
-800mV    1.138mA    5.458mA    1.805mA
-700mV    41.72uA    337.7uA    49.41uA
-11.55fV  95.72nA    66.54nA    459.6nA
[GND_clamp]
|   voltage   I(typ)   I(min)   I(max)
-3.3V     -13.46A    -11.58A    -14.63A
-1.033V   -115.4mA   -96.29mA   -194.1mA
-966.7mV  -40.89mA   -42.85mA   -70.19mA
-900mV    -5.45mA    -11.19mA   -10.34mA
-833.3mV  -1.994mA   -4.465mA   -3.636mA
-766.7mV  -182.5uA   -799.5uA   -194uA
-700mV    -16.43uA   -196.4uA   -16.82uA
-500mV    -941.1nA   -1.697uA   -2.047uA
3.233V    94.11nA    70.14nA    435.3nA
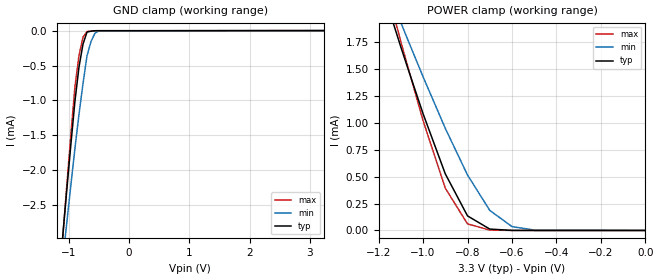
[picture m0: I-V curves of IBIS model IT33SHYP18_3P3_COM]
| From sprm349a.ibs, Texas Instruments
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|IT33SHYP18_3P3BUFFER WITHOUT PULLUP/PULLDOWN
|IN,CM,COM,IND REFERS TO TWO TEMPERATURE  MODES COM AND IND.
|   Model Cell IT33SHYP18_3P3_COM
|IT33SHYP18_3P3
[Model]   IT33SHYP18_3P3_COM
Model_type   Input
Polarity   Non-Inverting
Vinl =  0.8V
Vinh =  2V
C_comp   0.7465841p   0.68548p   0.8226742p
[Model Spec]
Vinl   0.8V   0.8V   0.8V
Vinh   2V   2V   2V
[Temperature Range]   25   105   0
[Voltage Range]   3.3   3.14   3.47
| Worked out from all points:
|   GND clamp passes 1 mA (typ) near -0.90 V on its own axis
|   POWER clamp passes 1 mA (typ) near -0.98 V on its own axis
[POWER_clamp]
|   voltage   I(typ)   I(min)   I(max)
-3.3V     16.09mA    13.56mA    18.62mA
-1.133V   1.92mA     2.103mA    2.013mA
-1.1V     1.705mA    1.931mA    1.755mA
-1.067V   1.498mA    1.764mA    1.511mA
-1V       1.085mA    1.428mA    1.021mA
-900mV    526.2uA    948.7uA    393.3uA
-800mV    135.4uA    515.1uA    61.39uA
-700mV    13.19uA    186.7uA    3.589uA
-600mV    617.4nA    36.18uA    584.4nA
-500mV    119.1nA    3.804uA    512.5nA
-11.55fV  95.15nA    66.44nA    457.6nA
[GND_clamp]
|   voltage   I(typ)   I(min)   I(max)
-3.3V     -25.77mA   -21.96mA   -28.61mA
-1.1V     -2.914mA   -3.271mA   -2.94mA
-1.033V   -2.256mA   -2.732mA   -2.19mA
-966.7mV  -1.62mA    -2.203mA   -1.477mA
-900mV    -1.008mA   -1.684mA   -799.3uA
-833.3mV  -523.5uA   -1.201mA   -356.2uA
-766.7mV  -194.5uA   -760.3uA   -94.11uA
-700mV    -20.9uA    -361.2uA   -12.99uA
-633.3mV  -8.234uA   -155.2uA   -6.41uA
-566.7mV  -1.665uA   -35.97uA   -2.969uA
-500mV    -1.19uA    -3.34uA    -2.672uA
3.233V    93.9nA     67.56nA    435.3nA
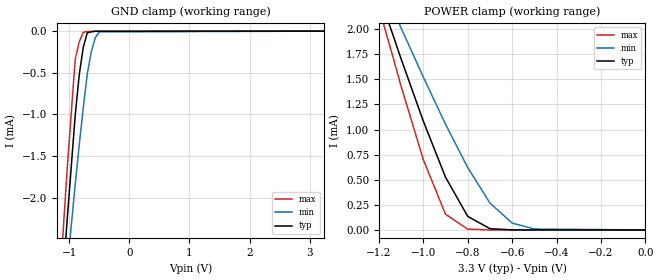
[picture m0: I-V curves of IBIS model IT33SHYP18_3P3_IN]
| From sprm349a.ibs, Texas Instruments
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|   Model Cell IT33SHYP18_3P3_IN
|IT33SHYP18_3P3
[Model]   IT33SHYP18_3P3_IN
Model_type   Input
Polarity   Non-Inverting
Vinl =  0.8V
Vinh =  2V
C_comp   0.7465841p   0.6831479p   0.8220855p
[Model Spec]
Vinl   0.8V   0.8V   0.8V
Vinh   2V   2V   2V
[Temperature Range]   25   125   -40
[Voltage Range]   3.3   3.14   3.47
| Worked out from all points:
|   GND clamp passes 1 mA (typ) near -0.90 V on its own axis
|   POWER clamp passes 1 mA (typ) near -0.98 V on its own axis
[POWER_clamp]
|   voltage   I(typ)   I(min)   I(max)
-3.3V     16.09mA    13.31mA    18.74mA
-1.2V     2.351mA    2.515mA    2.222mA
-1.167V   2.136mA    2.348mA    1.959mA
-1.133V   1.92mA     2.18mA     1.696mA
-1.1V     1.705mA    2.013mA    1.433mA
-1V       1.085mA    1.524mA    701.6uA
-900mV    526.2uA    1.054mA    157.3uA
-800mV    135.4uA    621.7uA    8.318uA
-700mV    13.19uA    268.3uA    366.4nA
-600mV    617.4nA    68.73uA    259.6nA
-500mV    119.1nA    9.651uA    252.1nA
-11.55fV  95.16nA    92.02nA    222.9nA
[GND_clamp]
|   voltage   I(typ)   I(min)   I(max)
-3.3V     -25.77mA   -21.29mA   -28.7mA
-1.167V   -3.595mA   -3.893mA   -3.188mA
-1.1V     -2.914mA   -3.365mA   -2.394mA
-1.033V   -2.256mA   -2.848mA   -1.643mA
-900mV    -1.008mA   -1.837mA   -339.1uA
-833.3mV  -523.5uA   -1.365mA   -128.6uA
-766.7mV  -194.5uA   -923.9uA   -16.71uA
-700mV    -20.9uA    -513.2uA   -3.547uA
-633.3mV  -8.234uA   -247.5uA   -3.137uA
-566.7mV  -1.665uA   -79.77uA   -2.932uA
-500mV    -1.19uA    -9.903uA   -2.932uA
3.233V    93.9nA     93.89nA    210.6nA
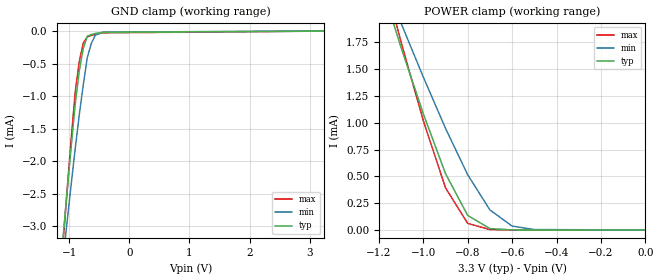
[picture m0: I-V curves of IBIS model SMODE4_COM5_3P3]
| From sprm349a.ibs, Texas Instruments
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|   Model Cell SMODE4_COM5_3P3
|SMODE4_COM5_3P3
[Model]   SMODE4_COM5_3P3
Model_type   Input
Polarity   Non-Inverting
Vinl =  0.8V
Vinh =  2V
C_comp   0.7732787p   0.7118968p   0.8502484p
[Model Spec]
Vinl   0.8V   0.8V   0.8V
Vinh   2V   2V   2V
[Temperature Range]   25   105   0
[Voltage Range]   3.3   3.14   3.47
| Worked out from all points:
|   GND clamp passes 1 mA (typ) near -0.88 V on its own axis
|   POWER clamp passes 1 mA (typ) near -0.98 V on its own axis
[POWER_clamp]
|   voltage   I(typ)   I(min)   I(max)
-3.3V     16.1mA     13.57mA    18.64mA
-1.133V   1.92mA     2.103mA    2.013mA
-1.1V     1.705mA    1.931mA    1.755mA
-1.067V   1.498mA    1.764mA    1.511mA
-1V       1.085mA    1.428mA    1.021mA
-900mV    526.2uA    948.7uA    393.3uA
-800mV    135.4uA    515.1uA    61.4uA
-700mV    13.19uA    186.7uA    3.592uA
-600mV    619nA      36.19uA    587.3nA
-500mV    120.7nA    3.807uA    515.4nA
-11.55fV  96.74nA    70.15nA    460.4nA
[GND_clamp]
|   voltage   I(typ)   I(min)   I(max)
-3.3V     -27.76mA   -23.33mA   -31.26mA
-1.1V     -3.153mA   -3.485mA   -3.231mA
-1.033V   -2.448mA   -2.914mA   -2.42mA
-966.7mV  -1.77mA    -2.354mA   -1.654mA
-900mV    -1.12mA    -1.804mA   -934.3uA
-833.3mV  -613.5uA   -1.293mA   -468.4uA
-766.7mV  -265.9uA   -828.5uA   -185.8uA
-700mV    -77.68uA   -409uA     -86.69uA
-633.3mV  -53.63uA   -191.3uA   -65.8uA
-566.7mV  -36.51uA   -62.44uA   -49.09uA
-433.3mV  -18.08uA   -14.35uA   -26.08uA
3.233V    95.48nA    71.28nA    438.1nA
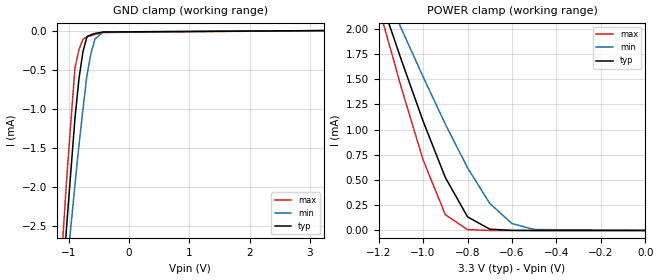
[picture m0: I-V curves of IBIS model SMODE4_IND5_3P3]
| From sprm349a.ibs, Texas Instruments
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|   Model Cell SMODE4_IND5_3P3
|SMODE4_IND5_3P3
[Model]   SMODE4_IND5_3P3
Model_type   Input
Polarity   Non-Inverting
Vinl =  0.8V
Vinh =  2V
C_comp   0.7732787p   0.7094674p   0.8496547p
[Model Spec]
Vinl   0.8V   0.8V   0.8V
Vinh   2V   2V   2V
[Temperature Range]   25   125   -40
[Voltage Range]   3.3   3.14   3.47
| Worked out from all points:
|   GND clamp passes 1 mA (typ) near -0.88 V on its own axis
|   POWER clamp passes 1 mA (typ) near -0.98 V on its own axis
[POWER_clamp]
|   voltage   I(typ)   I(min)   I(max)
-3.3V     16.1mA     13.31mA    18.76mA
-1.2V     2.351mA    2.515mA    2.222mA
-1.167V   2.136mA    2.348mA    1.959mA
-1.133V   1.92mA     2.18mA     1.696mA
-1.1V     1.705mA    2.013mA    1.433mA
-1V       1.085mA    1.524mA    701.6uA
-900mV    526.2uA    1.055mA    157.3uA
-800mV    135.4uA    621.7uA    8.32uA
-700mV    13.19uA    268.3uA    368.7nA
-600mV    619nA      68.74uA    261.7nA
-500mV    120.7nA    9.658uA    254.3nA
-11.55fV  96.74nA    98.76nA    225.1nA
[GND_clamp]
|   voltage   I(typ)   I(min)   I(max)
-3.3V     -27.76mA   -22.61mA   -31.33mA
-1.167V   -3.884mA   -4.144mA   -3.501mA
-1.1V     -3.153mA   -3.584mA   -2.642mA
-1.033V   -2.448mA   -3.036mA   -1.843mA
-900mV    -1.12mA    -1.965mA   -474.8uA
-833.3mV  -613.5uA   -1.465mA   -242.5uA
-766.7mV  -265.9uA   -999.1uA   -110.9uA
-700mV    -77.68uA   -566.1uA   -80uA
-633.3mV  -53.63uA   -286.4uA   -64.14uA
-566.7mV  -36.51uA   -107.5uA   -49.31uA
-433.3mV  -18.08uA   -17.46uA   -24.18uA
3.233V    95.48nA    100.6nA    212.7nA
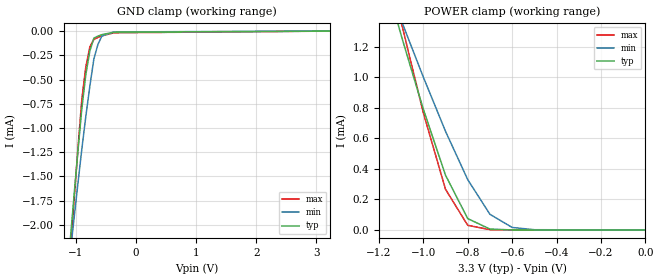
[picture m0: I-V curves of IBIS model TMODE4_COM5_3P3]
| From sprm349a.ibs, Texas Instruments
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|   Model Cell TMODE4_COM5_3P3
|TMODE4_COM5_3P3
[Model]   TMODE4_COM5_3P3
Model_type   Input
Polarity   Non-Inverting
Vinl =  0.8V
Vinh =  2V
C_comp   0.5121187p   0.4653713p   0.5743862p
[Model Spec]
Vinl   0.8V   0.8V   0.8V
Vinh   2V   2V   2V
[Temperature Range]   25   105   0
[Voltage Range]   3.3   3.14   3.47
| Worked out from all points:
|   GND clamp passes 1 mA (typ) near -0.93 V on its own axis
|   POWER clamp passes 1 mA (typ) near -1.04 V on its own axis
[POWER_clamp]
|   voltage   I(typ)   I(min)   I(max)
-3.3V     12.49mA    10mA       14.97mA
-1.133V   1.449mA    1.507mA    1.578mA
-1.1V     1.279mA    1.378mA    1.367mA
-1.067V   1.117mA    1.253mA    1.168mA
-1V       792.6uA    1.003mA    768.9uA
-900mV    359.3uA    647.1uA    266.8uA
-800mV    74.63uA    330.2uA    30.79uA
-700mV    5.938uA    102.8uA    1.858uA
-600mV    327.3nA    16.62uA    552.1nA
-500mV    113.5nA    1.676uA    514.6nA
-11.55fV  96.58nA    70nA       460.2nA
[GND_clamp]
|   voltage   I(typ)   I(min)   I(max)
-3.3V     -19.06mA   -15.34mA   -22.43mA
-1.1V     -2.21mA    -2.33mA    -2.372mA
-1.033V   -1.719mA   -1.951mA   -1.779mA
-966.7mV  -1.248mA   -1.579mA   -1.222mA
-900mV    -796.5uA   -1.215mA   -699.5uA
-833.3mV  -445.7uA   -875.6uA   -365.4uA
-766.7mV  -204.2uA   -566.1uA   -160.8uA
-700mV    -72.07uA   -286uA     -85.7uA
-633.3mV  -51.67uA   -138.1uA   -65.46uA
-566.7mV  -36.41uA   -49.84uA   -49.08uA
-366.7mV  -11.04uA   -8.124uA   -16.99uA
3.233V    95.33nA    71.08nA    437.9nA
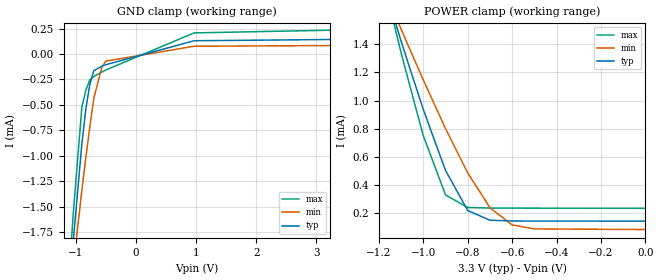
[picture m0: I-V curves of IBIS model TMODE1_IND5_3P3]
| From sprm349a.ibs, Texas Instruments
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|   Model Cell TMODE1_IND5_3P3
|TMODE1_IND5_3P3
[Model]   TMODE1_IND5_3P3
Model_type   Input
Polarity   Non-Inverting
Vinl =  0.8V
Vinh =  2V
C_comp   0.5121187p   0.4644821p   0.5740407p
[Model Spec]
Vinl   0.8V   0.8V   0.8V
Vinh   2V   2V   2V
[Temperature Range]   25   125   -40
[Voltage Range]   3.3   3.14   3.47
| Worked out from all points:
|   GND clamp passes 1 mA (typ) near -0.92 V on its own axis
|   POWER clamp passes 1 mA (typ) near -1.01 V on its own axis
[POWER_clamp]
|   voltage   I(typ)   I(min)   I(max)
-3.3V     12.69mA    9.849mA    15.28mA
-1.133V   1.594mA    1.633mA    1.554mA
-1.1V     1.424mA    1.509mA    1.341mA
-1.067V   1.261mA    1.388mA    1.144mA
-1V       936.9uA    1.147mA    750.2uA
-900mV    503.4uA    801.2uA    329.1uA
-800mV    218.4uA    486.1uA    239.9uA
-700mV    149.5uA    238.2uA    235.9uA
-600mV    143.7uA    116.2uA    235.5uA
-500mV    143.3uA    87.54uA    235.2uA
-11.55fV  142.7uA    83.08uA    234uA
[GND_clamp]
|   voltage   I(typ)   I(min)   I(max)
-3.3V     -19.06mA   -14.84mA   -22.38mA
-1.167V   -2.741mA   -2.766mA   -2.637mA
-1.1V     -2.241mA   -2.397mA   -2.047mA
-1.033V   -1.769mA   -2.037mA   -1.49mA
-900mV    -882.4uA   -1.335mA   -521.2uA
-833.3mV  -536.1uA   -1.012mA   -353uA
-766.7mV  -296.2uA   -710.5uA   -252.5uA
-700mV    -162.5uA   -431.1uA   -219.7uA
-566.7mV  -119.3uA   -125uA     -177.1uA
-500mV    -104.6uA   -69.49uA   -156.2uA
966.7mV   130.3uA    76.27uA    207.4uA
3.233V    142.6uA    83.12uA    233.8uA
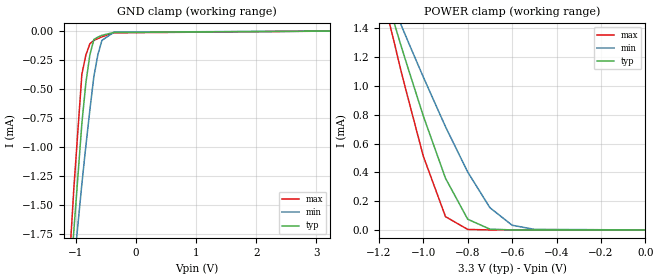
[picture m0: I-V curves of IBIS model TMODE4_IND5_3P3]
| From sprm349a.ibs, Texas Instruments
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|   Model Cell TMODE4_IND5_3P3
|TMODE4_IND5_3P3
[Model]   TMODE4_IND5_3P3
Model_type   Input
Polarity   Non-Inverting
Vinl =  0.8V
Vinh =  2V
C_comp   0.5121187p   0.4644821p   0.5740407p
[Model Spec]
Vinl   0.8V   0.8V   0.8V
Vinh   2V   2V   2V
[Temperature Range]   25   125   -40
[Voltage Range]   3.3   3.14   3.47
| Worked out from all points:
|   GND clamp passes 1 mA (typ) near -0.93 V on its own axis
|   POWER clamp passes 1 mA (typ) near -1.04 V on its own axis
[POWER_clamp]
|   voltage   I(typ)   I(min)   I(max)
-3.3V     12.49mA    9.733mA    14.95mA
-1.167V   1.619mA    1.672mA    1.53mA
-1.133V   1.449mA    1.549mA    1.317mA
-1.1V     1.279mA    1.425mA    1.103mA
-1.067V   1.117mA    1.304mA    906.6uA
-1V       792.6uA    1.063mA    513.3uA
-900mV    359.3uA    717.5uA    92.68uA
-800mV    74.63uA    402.5uA    3.83uA
-700mV    5.938uA    154.7uA    310.5nA
-600mV    327.3nA    32.88uA    261nA
-500mV    113.5nA    4.258uA    254.1nA
-11.55fV  96.58nA    98.61nA    224.9nA
[GND_clamp]
|   voltage   I(typ)   I(min)   I(max)
-3.3V     -19.06mA   -14.84mA   -22.38mA
-1.167V   -2.718mA   -2.76mA    -2.557mA
-1.1V     -2.21mA    -2.39mA    -1.932mA
-1.033V   -1.719mA   -2.028mA   -1.354mA
-900mV    -796.5uA   -1.319mA   -372.5uA
-833.3mV  -445.7uA   -988.2uA   -206.2uA
-766.7mV  -204.2uA   -678.7uA   -108.7uA
-700mV    -72.07uA   -390.6uA   -79.98uA
-633.3mV  -51.67uA   -201.8uA   -64.13uA
-566.7mV  -36.41uA   -80.2uA    -49.31uA
-366.7mV  -11.04uA   -8.932uA   -14.83uA
3.233V    95.33nA    100.3nA    212.6nA
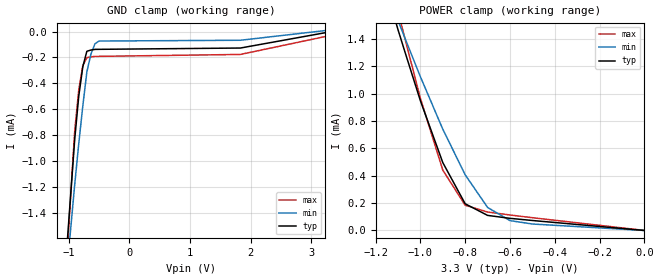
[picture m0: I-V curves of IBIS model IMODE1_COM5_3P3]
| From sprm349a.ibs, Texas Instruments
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|IMODE4_IND5_3P3BUFFER IN NORMAL MODE WITH INDTEMP AT 5PERCENT VDDS
|   Model Cell IMODE1_COM5_3P3
|IMODE1_COM5_3P3
[Model]   IMODE1_COM5_3P3
Model_type   Input
Polarity   Non-Inverting
Vinl =  0.8V
Vinh =  2V
C_comp   0.5019789p   0.4562502p   0.5648978p
[Model Spec]
Vinl   0.8V   0.8V   0.8V
Vinh   2V   2V   2V
[Temperature Range]   25   105   0
[Voltage Range]   3.3   3.14   3.47
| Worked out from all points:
|   GND clamp passes 1 mA (typ) near -0.93 V on its own axis
|   POWER clamp passes 1 mA (typ) near -1.01 V on its own axis
[POWER_clamp]
|   voltage   I(typ)   I(min)   I(max)
-3.3V     14.1mA     11.1mA     17.16mA
-1.1V     1.468mA    1.535mA    1.602mA
-1.067V   1.295mA    1.398mA    1.39mA
-1V       948.5uA    1.124mA    966.3uA
-900mV    496.3uA    740.6uA    441.5uA
-800mV    195.1uA    407uA      184.4uA
-700mV    110.3uA    168.5uA    134.9uA
-600mV    88.8uA     72.15uA    113.3uA
-500mV    72.99uA    47.31uA    93.37uA
-11.55fV  95.4nA     66.49nA    458.4nA
[GND_clamp]
|   voltage   I(typ)   I(min)   I(max)
-3.3V     -17.51mA   -14.27mA   -20.29mA
-1.1V     -2.139mA   -2.219mA   -2.308mA
-1.033V   -1.688mA   -1.867mA   -1.769mA
-900mV    -831.9uA   -1.182mA   -767.7uA
-833.3mV  -498.6uA   -865.5uA   -450.5uA
-766.7mV  -272.1uA   -575.7uA   -261.9uA
-700mV    -152.2uA   -312.4uA   -202uA
-633.3mV  -142.6uA   -174.5uA   -195.4uA
-566.7mV  -137.6uA   -94.71uA   -191.9uA
-500mV    -137.1uA   -73.03uA   -191.4uA
1.833V    -127.1uA   -67.09uA   -176.6uA
3.233V    -8.718uA   8.017uA    -38.34uA
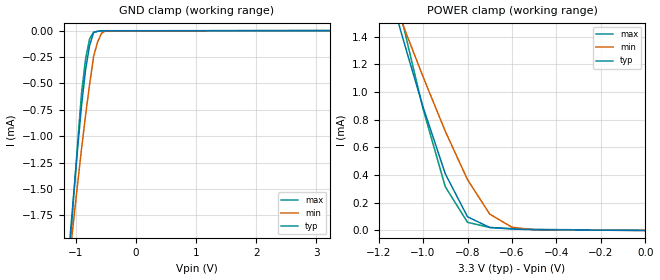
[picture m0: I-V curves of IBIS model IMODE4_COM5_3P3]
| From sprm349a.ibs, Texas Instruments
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|   Model Cell IMODE4_COM5_3P3
|IMODE4_COM5_3P3
[Model]   IMODE4_COM5_3P3
Model_type   Input
Polarity   Non-Inverting
Vinl =  0.8V
Vinh =  2V
C_comp   0.5019789p   0.4562502p   0.5648978p
[Model Spec]
Vinl   0.8V   0.8V   0.8V
Vinh   2V   2V   2V
[Temperature Range]   25   105   0
[Voltage Range]   3.3   3.14   3.47
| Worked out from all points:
|   GND clamp passes 1 mA (typ) near -0.95 V on its own axis
|   POWER clamp passes 1 mA (typ) near -1.02 V on its own axis
[POWER_clamp]
|   voltage   I(typ)   I(min)   I(max)
-3.3V     14.1mA     11.1mA     17.16mA
-1.1V     1.439mA    1.525mA    1.558mA
-1.067V   1.256mA    1.387mA    1.331mA
-1V       892.2uA    1.11mA     878.1uA
-900mV    409.2uA    716.1uA    315.8uA
-800mV    98.79uA    366.7uA    59.01uA
-700mV    21.73uA    118.1uA    21.64uA
-600mV    10.46uA    23.32uA    13.42uA
-500mV    5.709uA    4.812uA    7.749uA
-11.55fV  95.88nA    66.7nA     459.7nA
[GND_clamp]
|   voltage   I(typ)   I(min)   I(max)
-3.3V     -17.38mA   -14.21mA   -20.11mA
-1.1V     -2.012mA   -2.154mA   -2.129mA
-1.033V   -1.56mA    -1.802mA   -1.589mA
-966.7mV  -1.124mA   -1.456mA   -1.075mA
-900mV    -703.5uA   -1.116mA   -587.1uA
-833.3mV  -368.4uA   -799.4uA   -268uA
-766.7mV  -139.7uA   -508.8uA   -77.05uA
-700mV    -17.32uA   -244.4uA   -14.16uA
-633.3mV  -6.9uA     -105.2uA   -6.487uA
-566.7mV  -1.44uA    -24.48uA   -2.446uA
-500mV    -938.8nA   -2.383uA   -2.041uA
3.233V    94.27nA    70.33nA    435.5nA
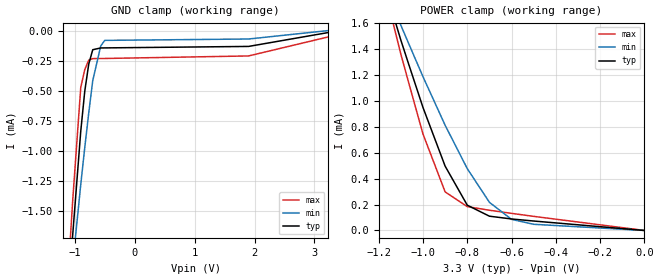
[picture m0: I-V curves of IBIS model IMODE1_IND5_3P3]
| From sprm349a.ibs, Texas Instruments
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|   Model Cell IMODE1_IND5_3P3
|IMODE1_IND5_3P3
[Model]   IMODE1_IND5_3P3
Model_type   Input
Polarity   Non-Inverting
Vinl =  0.8V
Vinh =  2V
C_comp   0.5019789p   0.455762p   0.5644586p
[Model Spec]
Vinl   0.8V   0.8V   0.8V
Vinh   2V   2V   2V
[Temperature Range]   25   125   -40
[Voltage Range]   3.3   3.14   3.47
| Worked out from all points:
|   GND clamp passes 1 mA (typ) near -0.93 V on its own axis
|   POWER clamp passes 1 mA (typ) near -1.01 V on its own axis
[POWER_clamp]
|   voltage   I(typ)   I(min)   I(max)
-3.3V     14.1mA     10.79mA    17.12mA
-1.133V   1.655mA    1.72mA     1.586mA
-1.1V     1.468mA    1.583mA    1.36mA
-1.067V   1.295mA    1.451mA    1.155mA
-1V       948.5uA    1.186mA    743.7uA
-900mV    496.3uA    811.5uA    297.7uA
-800mV    195.1uA    477.1uA    184uA
-700mV    110.3uA    217.4uA    156.1uA
-600mV    88.81uA    85.76uA    132.2uA
-500mV    73uA       47.7uA     108.9uA
-11.55fV  95.4nA     92.24nA    222.9nA
[GND_clamp]
|   voltage   I(typ)   I(min)   I(max)
-3.3V     -17.51mA   -13.81mA   -20.34mA
-1.167V   -2.606mA   -2.617mA   -2.506mA
-1.1V     -2.139mA   -2.273mA   -1.937mA
-1.033V   -1.688mA   -1.936mA   -1.399mA
-900mV    -831.9uA   -1.277mA   -466.8uA
-833.3mV  -498.6uA   -969.1uA   -318.4uA
-766.7mV  -272.1uA   -680uA     -238.3uA
-700mV    -152.2uA   -410.3uA   -226.3uA
-566.7mV  -137.6uA   -121.2uA   -225.4uA
-500mV    -137.1uA   -74.36uA   -225.3uA
1.9V      -124.8uA   -62.96uA   -204.2uA
3.233V    -8.72uA    7.659uA    -45.2uA
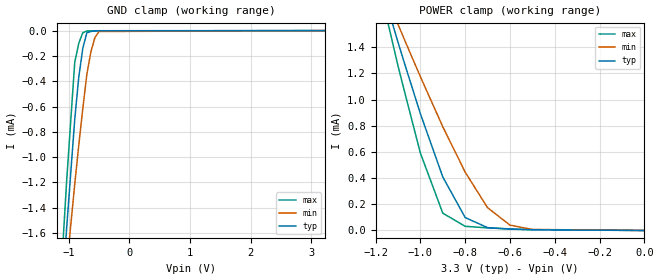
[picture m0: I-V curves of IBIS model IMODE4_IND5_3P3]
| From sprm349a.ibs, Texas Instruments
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|   Model Cell IMODE4_IND5_3P3
|IMODE4_IND5_3P3
[Model]   IMODE4_IND5_3P3
Model_type   Input
Polarity   Non-Inverting
Vinl =  0.8V
Vinh =  2V
C_comp   0.5019789p   0.455762p   0.5644586p
[Model Spec]
Vinl   0.8V   0.8V   0.8V
Vinh   2V   2V   2V
[Temperature Range]   25   125   -40
[Voltage Range]   3.3   3.14   3.47
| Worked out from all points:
|   GND clamp passes 1 mA (typ) near -0.95 V on its own axis
|   POWER clamp passes 1 mA (typ) near -1.02 V on its own axis
[POWER_clamp]
|   voltage   I(typ)   I(min)   I(max)
-3.3V     14.1mA     10.79mA    17.11mA
-1.167V   1.821mA    1.849mA    1.743mA
-1.133V   1.63mA     1.712mA    1.501mA
-1.1V     1.439mA    1.575mA    1.258mA
-1.067V   1.256mA    1.442mA    1.036mA
-1V       892.2uA    1.175mA    591.5uA
-900mV    409.2uA    792.8uA    132.3uA
-800mV    98.79uA    445.5uA    31.99uA
-700mV    21.73uA    174uA      19.58uA
-600mV    10.46uA    40.81uA    12.02uA
-500mV    5.709uA    7.864uA    6.166uA
-11.55fV  95.89nA    92.64nA    223.1nA
[GND_clamp]
|   voltage   I(typ)   I(min)   I(max)
-3.3V     -17.38mA   -13.75mA   -20.13mA
-1.167V   -2.479mA   -2.555mA   -2.297mA
-1.1V     -2.012mA   -2.211mA   -1.728mA
-1.033V   -1.56mA    -1.874mA   -1.188mA
-900mV    -703.5uA   -1.215mA   -252.5uA
-833.3mV  -368.4uA   -906uA     -100uA
-766.7mV  -139.7uA   -616.4uA   -16.92uA
-700mV    -17.32uA   -345.9uA   -3.121uA
-633.3mV  -6.9uA     -167.5uA   -2.574uA
-566.7mV  -1.44uA    -54.51uA   -2.296uA
-500mV    -938.8nA   -6.897uA   -2.286uA
3.233V    94.28nA    98.84nA    210.5nA
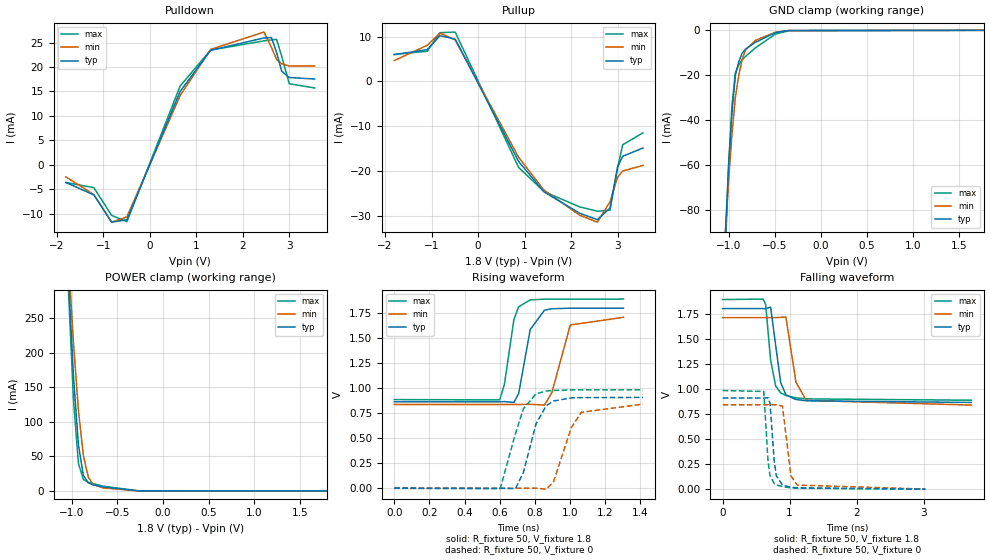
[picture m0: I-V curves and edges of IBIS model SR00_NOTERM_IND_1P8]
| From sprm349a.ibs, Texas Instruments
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|BUFFER OPERATES IN FASTEST MODE AT COM TEMP WHEN SR0=SR1=0
|COM AND IND ARE TWO DIFF TEMP MODES WITH DIFFERENT TEMP RANGES
|   Model Cell SR00_NOTERM_IND_1P8
[Model]   SR00_NOTERM_IND_1P8
Model_type   3-state
Polarity   Non-Inverting
Enable   Active-Low
Cref =  15.0000pF
Rref =  100.0000M
Vref =  0V
Vmeas =  0.9
C_comp   1.442955p   1.395583p   1.48531p
[Temperature Range]   25   125   -40
[Voltage Range]   1.8   1.71   1.89
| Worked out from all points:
|   slope of the pulldown table from 0 to 0.27 V, typ, clamps not added: 40.2 ohm
|   slope of the pullup table from 0 to 0.27 V, typ, clamps not added: 43.4 ohm
|   GND clamp passes 1 mA (typ) near -0.49 V on its own axis
|   POWER clamp passes 1 mA (typ) near -0.39 V on its own axis
|   rising waveform, R_fixture 50, V_fixture 1.8: 20-80 % time 58.5ps typ, 66.1ps min, 50.9ps max; typ from 0.864 V to 1.8 V
|   rising waveform, R_fixture 50, V_fixture 0: 20-80 % time 88.4ps typ, 95.6ps min, 85.5ps max; typ from 0 V to 0.907 V
|   falling waveform, R_fixture 50, V_fixture 1.8: 20-80 % time 108ps typ, 123ps min, 105ps max; typ from 1.8 V to 0.865 V
|   falling waveform, R_fixture 50, V_fixture 0: 20-80 % time 68.3ps typ, 80.9ps min, 61.3ps max; typ from 0.908 V to 0.001 V
[POWER_clamp]
|   voltage   I(typ)   I(min)   I(max)
-1.8V     2.924A     2.487A     3.338A
-1.055V   360.4mA    379.2mA    352.9mA
-1.036V   307mA      335.2mA    290.5mA
-1.018V   260.5mA    295.4mA    238.1mA
-981.8mV  167.5mA    215.8mA    133.1mA
-927.3mV  67.32mA    117.4mA    40.14mA
-872.7mV  22.56mA    51.06mA    16.61mA
-818.2mV  11.6mA     19.66mA    12.51mA
-763.6mV  8.74mA     9.202mA    10.43mA
-654.5mV  5.816mA    4.325mA    6.849mA
-272.7mV  209.5uA    104.6uA    156.2uA
1.8V      20.65nA    121nA      17.98nA
[Pulldown]
|   voltage   I(typ)   I(min)   I(max)
-1.8V     -3.616mA   -2.48mA    -3.623mA
-1.2V     -6.175mA   -6.104mA   -4.679mA
-818.2mV  -11.73mA   -11.74mA   -10.36mA
-490.9mV  -11.25mA   -10.65mA   -11.63mA
654.5mV   15.01mA    14.16mA    16.12mA
1.309V    23.41mA    23.6mA     23.46mA
2.455V    25.94mA    27.14mA    25.35mA
2.618V    26.01mA    23.98mA    25.55mA
2.727V    22.94mA    21.54mA    25.65mA
2.836V    19.15mA    20.65mA    22.22mA
3V        17.85mA    20.21mA    16.58mA
3.545V    17.54mA    20.19mA    15.71mA
[Pullup]
|   voltage   I(typ)   I(min)   I(max)
-1.8V     5.97mA     4.648mA    6.042mA
-1.091V   7.105mA    8.064mA    6.729mA
-818.2mV  10.22mA    10.77mA    10.87mA
-490.9mV  9.425mA    9.254mA    11mA
872.7mV   -17.83mA   -16.9mA    -19.16mA
1.418V    -24.61mA   -24.22mA   -24.52mA
2.182V    -29.34mA   -29.77mA   -27.93mA
2.564V    -30.79mA   -31.35mA   -28.9mA
2.836V    -28.2mA    -26.82mA   -28.68mA
3V        -19.04mA   -21.3mA    -19.15mA
3.109V    -16.66mA   -19.95mA   -14.1mA
3.545V    -14.83mA   -18.7mA    -11.44mA
[GND_clamp]
|   voltage   I(typ)   I(min)   I(max)
-1.8V     -3.609A    -2.849A    -4.282A
-1.036V   -90.86mA   -90.81mA   -98.4mA
-1V       -59.97mA   -66.44mA   -59.97mA
-963.6mV  -36.36mA   -46.14mA   -33.47mA
-927.3mV  -20.02mA   -29.92mA   -18.88mA
-890.9mV  -14.12mA   -20.26mA   -15.57mA
-854.5mV  -10.24mA   -13.24mA   -13.16mA
-818.2mV  -8.387mA   -8.861mA   -11.65mA
-709.1mV  -5.316mA   -4.454mA   -7.779mA
-490.9mV  -974.7uA   -808.7uA   -1.627mA
-345.5mV  -83.88uA   -97.13uA   -147.7uA
1.764V    -13.07nA   612.8nA    1.397nA
[Ramp]
| variable   typ   min   max
dV/dt_f  0.7628051/0.1778337n  0.7138702/0.1997126n  0.8151664/0.1776904n
dV/dt_r  0.7327228/0.1398565n  0.6819614/0.153565n   0.792663/0.1343565n
R_load = 50
[Rising Waveform]
R_fixture = 50
V_fixture = 1.8
V_fixture_min = 1.71
V_fixture_max = 1.89
|   time   V(typ)   V(min)   V(max)
0s        863.6mV    836.9mV    886mV
600ps     863.5mV    836.9mV    882.8mV
627ps     865.9mV    836.9mV    1.039V
681ps     857.8mV    836.9mV    1.685V
708ps     945.4mV    836.8mV    1.813V
774ps     1.586V     838.9mV    1.882V
855ps     1.779V     831mV      1.889V
897ps     1.793V     954.5mV    1.889V
1.002ns   1.799V     1.631V     1.889V
1.305ns   1.799V     1.708V     1.89V
[Rising Waveform]
R_fixture = 50
V_fixture = 0
V_fixture_min = 0
V_fixture_max = 0
|   time   V(typ)   V(min)   V(max)
0s        46.69uV    44.04uV    44.81uV
603ps     28.01uV    43.84uV    -4.422mV
690ps     -3.474mV   36.54uV    547.1mV
735ps     157.9mV    36.75uV    794.6mV
807ps     642.7mV    168.9uV    943mV
864ps     822.1mV    -9.005mV   971.5mV
906ps     871.7mV    60.08mV    978.1mV
1.008ns   902.7mV    607.2mV    982.2mV
1.065ns   905.7mV    758.8mV    982.7mV
1.416ns   907.3mV    840.5mV    983.3mV
[Falling Waveform]
R_fixture = 50
V_fixture = 1.8
V_fixture_min = 1.71
V_fixture_max = 1.89
|   time   V(typ)   V(min)   V(max)
0s        1.8V       1.71V      1.89V
603ps     1.8V       1.71V      1.895V
642ps     1.799V     1.71V      1.842V
717ps     1.815V     1.71V      1.285V
792ps     1.435V     1.71V      1.029V
867ps     1.063V     1.713V     960.5mV
945ps     941.1mV    1.716V     933.7mV
1.095ns   894.3mV    1.067V     910.7mV
1.248ns   881.4mV    885.2mV    900.4mV
3.714ns   864.8mV    838.6mV    886.9mV
[Falling Waveform]
R_fixture = 50
V_fixture = 0
V_fixture_min = 0
V_fixture_max = 0
|   time   V(typ)   V(min)   V(max)
0s        908.3mV    842.3mV    983.8mV
615ps     908.4mV    842.3mV    974.3mV
678ps     912.2mV    842.3mV    280.5mV
708ps     857.3mV    842.3mV    134mV
771ps     278.7mV    842.3mV    55.94mV
801ps     137mV      841.5mV    44.15mV
894ps     39.97mV    826.7mV    25.81mV
1.02ns    19.66mV    134.5mV    14.42mV
1.113ns   13.87mV    41.59mV    10.05mV
3.027ns   1.196mV    1.757mV    795.2uV
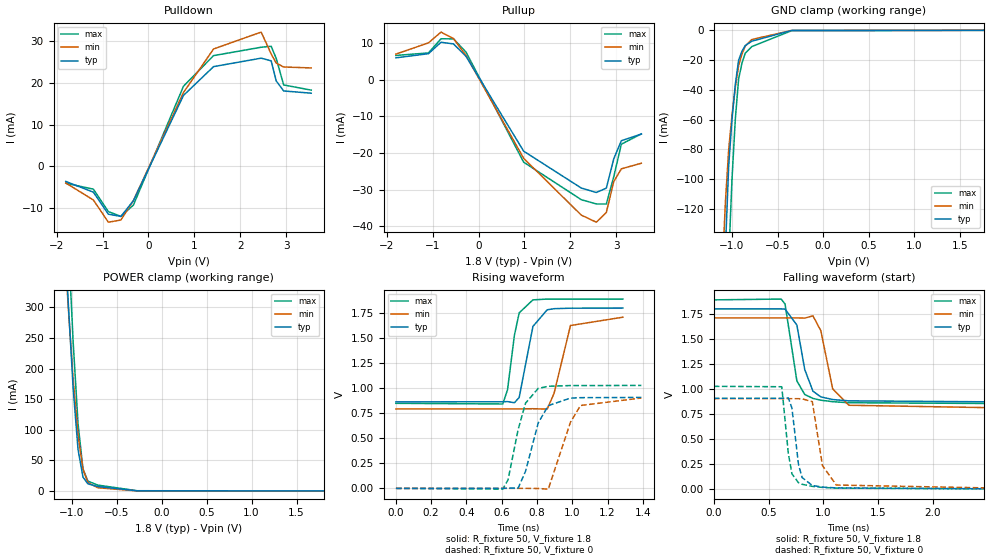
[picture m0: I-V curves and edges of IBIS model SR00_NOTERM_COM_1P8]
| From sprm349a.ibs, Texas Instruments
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|   Model Cell SR00_NOTERM_COM_1P8
[Model]   SR00_NOTERM_COM_1P8
Model_type   3-state
Polarity   Non-Inverting
Enable   Active-Low
Cref =  15.0000pF
Rref =  100.0000M
Vref =  0V
Vmeas =  0.9
C_comp   1.442955p   1.396886p   1.485379p
[Temperature Range]   25   105   0
[Voltage Range]   1.8   1.71   1.89
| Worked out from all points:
|   slope of the pulldown table from 0 to 0.27 V, typ, clamps not added: 40.2 ohm
|   slope of the pullup table from 0 to 0.27 V, typ, clamps not added: 43.4 ohm
|   GND clamp passes 1 mA (typ) near -0.49 V on its own axis
|   POWER clamp passes 1 mA (typ) near -0.39 V on its own axis
|   rising waveform, R_fixture 50, V_fixture 1.8: 20-80 % time 57.9ps typ, 61.6ps min, 49.8ps max; typ from 0.864 V to 1.8 V
|   rising waveform, R_fixture 50, V_fixture 0: 20-80 % time 88.5ps typ, 84.7ps min, 76.3ps max; typ from 0 V to 0.907 V
|   falling waveform, R_fixture 50, V_fixture 1.8: 20-80 % time 106ps typ, 109ps min, 96.3ps max; typ from 1.8 V to 0.865 V
|   falling waveform, R_fixture 50, V_fixture 0: 20-80 % time 67.6ps typ, 77.6ps min, 59.9ps max; typ from 0.908 V to 0.001 V
[POWER_clamp]
|   voltage   I(typ)   I(min)   I(max)
-1.8V     2.924A     2.499A     3.314A
-1.073V   413.7mA    389mA      534mA
-1.055V   360.4mA    344.6mA    472.5mA
-1.036V   307mA      300.3mA    411mA
-1.018V   260.5mA    261mA      355.2mA
-981.8mV  167.5mA    182.4mA    243.4mA
-927.3mV  67.32mA    90.2mA     109.4mA
-872.7mV  22.56mA    35.19mA    35.94mA
-818.2mV  11.6mA     13.66mA    16.02mA
-709.1mV  7.157mA    5.17mA     9.556mA
-272.7mV  209.5uA    73.78uA    321.6uA
1.8V      20.65nA    62.23nA    115.8nA
[Pulldown]
|   voltage   I(typ)   I(min)   I(max)
-1.8V     -3.616mA   -3.987mA   -4.045mA
-1.2V     -6.175mA   -8.051mA   -5.458mA
-872.7mV  -11.46mA   -13.38mA   -10.84mA
-600mV    -12mA      -12.86mA   -11.99mA
-327.3mV  -8.221mA   -8.179mA   -9.268mA
763.6mV   17.02mA    17.72mA    19.22mA
1.418V    23.91mA    28.14mA    26.55mA
2.455V    25.94mA    32.19mA    28.56mA
2.673V    25.3mA     26.94mA    28.78mA
2.782V    20.49mA    24.77mA    25.89mA
2.945V    18.08mA    23.82mA    19.52mA
3.545V    17.54mA    23.6mA     18.28mA
[Pullup]
|   voltage   I(typ)   I(min)   I(max)
-1.8V     5.97mA     6.99mA     6.621mA
-1.091V   7.105mA    10.06mA    7.317mA
-818.2mV  10.22mA    13mA       11.18mA
-545.5mV  9.773mA    11.22mA    11.15mA
-272.7mV  6.365mA    6.583mA    7.526mA
981.8mV   -19.51mA   -21.46mA   -22.51mA
2.236V    -29.57mA   -36.96mA   -32.75mA
2.564V    -30.79mA   -38.9mA    -33.92mA
2.782V    -29.61mA   -36.26mA   -33.94mA
2.945V    -21.58mA   -27.77mA   -26.43mA
3.109V    -16.66mA   -24.34mA   -17.6mA
3.545V    -14.83mA   -22.8mA    -14.79mA
[GND_clamp]
|   voltage   I(typ)   I(min)   I(max)
-1.8V     -3.609A    -2.898A    -4.16A
-1.109V   -225.9mA   -165.2mA   -373.1mA
-1.073V   -148mA     -116.3mA   -252.5mA
-1.036V   -90.86mA   -79.86mA   -153.7mA
-1V       -59.97mA   -57.09mA   -100.1mA
-963.6mV  -36.36mA   -38.37mA   -59.81mA
-927.3mV  -20.02mA   -23.72mA   -32.75mA
-890.9mV  -14.12mA   -16mA      -22.13mA
-854.5mV  -10.24mA   -10.6mA    -15.34mA
-781.8mV  -7.291mA   -6.156mA   -10.91mA
-345.5mV  -83.88uA   -75.59uA   -264.7uA
1.764V    -13.07nA   327.4nA    -6.816nA
[Ramp]
| variable   typ   min   max
dV/dt_f  0.7627899/0.1777987n  0.7514688/0.1803569n  0.8465891/0.1630979n
dV/dt_r  0.7327243/0.1398548n  0.7326515/0.1378742n  0.8282323/0.1196498n
R_load = 50
[Rising Waveform]
R_fixture = 50
V_fixture = 1.8
V_fixture_min = 1.71
V_fixture_max = 1.89
|   time   V(typ)   V(min)   V(max)
0s        863.6mV    792.8mV    848.8mV
606ps     863.9mV    792.8mV    842.2mV
633ps     866mV      792.8mV    984mV
672ps     854.6mV    792.8mV    1.527V
699ps     906.5mV    792.8mV    1.751V
777ps     1.616V     794.9mV    1.881V
858ps     1.782V     791mV      1.889V
897ps     1.793V     948.8mV    1.889V
990ps     1.798V     1.625V     1.889V
1.287ns   1.799V     1.708V     1.889V
[Rising Waveform]
R_fixture = 50
V_fixture = 0
V_fixture_min = 0
V_fixture_max = 0
|   time   V(typ)   V(min)   V(max)
0s        46.69uV    39.88uV    55.13uV
606ps     262uV      39.66uV    -7.56mV
636ps     2.826mV    40.58uV    85.95mV
693ps     2.198mV    17.91uV    586mV
735ps     170.3mV    90.98uV    849.9mV
807ps     652.6mV    -1.03mV    997.3mV
864ps     825.6mV    -7.817mV   1.019V
990ps     901mV      660.8mV    1.026V
1.047ns   905.1mV    827mV      1.026V
1.392ns   907.3mV    901.9mV    1.027V
[Falling Waveform]
R_fixture = 50
V_fixture = 1.8
V_fixture_min = 1.71
V_fixture_max = 1.89
|   time   V(typ)   V(min)   V(max)
0s        1.8V       1.71V      1.89V
615ps     1.8V       1.71V      1.898V
651ps     1.798V     1.71V      1.849V
759ps     1.639V     1.71V      1.081V
831ps     1.194V     1.708V     945.8mV
906ps     978.5mV    1.73V      906.3mV
978ps     921.6mV    1.582V     888.6mV
1.086ns   895.3mV    1.002V     873.8mV
1.233ns   882.2mV    838.2mV    863.5mV
3.555ns   864.9mV    794.5mV    849.7mV
[Falling Waveform]
R_fixture = 50
V_fixture = 0
V_fixture_min = 0
V_fixture_max = 0
|   time   V(typ)   V(min)   V(max)
0s        908.3mV    903.6mV    1.027V
621ps     908.2mV    903.6mV    1.023V
681ps     911.6mV    903.6mV    356.4mV
714ps     810mV      903.6mV    154.1mV
774ps     245.7mV    903.6mV    64.72mV
807ps     116.8mV    902.7mV    49.5mV
900ps     37.58mV    873.9mV    28.71mV
993ps     21.97mV    235.3mV    18.44mV
1.119ns   13.5mV     42.1mV     11.14mV
3.042ns   1.184mV    1.753mV    839.3uV
